VERSION 5.8 ;
BUSBITCHARS "[]" ;
DIVIDERCHAR "/" ;
UNITS
    DATABASE MICRONS 1000 ;
END UNITS

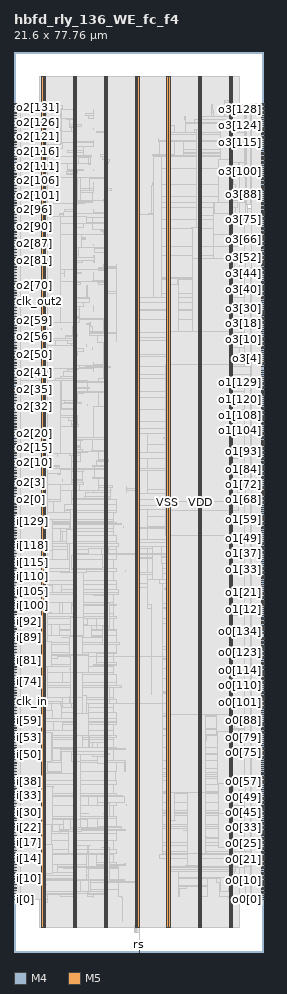
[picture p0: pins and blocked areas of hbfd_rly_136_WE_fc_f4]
MACRO hbfd_rly_136_WE_fc_f4
  FOREIGN hbfd_rly_136_WE_fc_f4 0 0 ;
  CLASS BLOCK ;
  SIZE 21.6 BY 77.76 ;
  PIN clk_in
    DIRECTION INPUT ;
    USE SIGNAL ;
    PORT
      LAYER M4 ;
        RECT  0 21.6 0.192 21.624 ;
    END
  END clk_in
  PIN clk_out0
    DIRECTION OUTPUT ;
    USE SIGNAL ;
    PORT
      LAYER M4 ;
        RECT  21.408 15.84 21.6 15.864 ;
    END
  END clk_out0
  PIN clk_out1
    DIRECTION OUTPUT ;
    USE SIGNAL ;
    PORT
      LAYER M4 ;
        RECT  21.408 38.88 21.6 38.904 ;
    END
  END clk_out1
  PIN clk_out2
    DIRECTION OUTPUT ;
    USE SIGNAL ;
    PORT
      LAYER M4 ;
        RECT  0 56.16 0.192 56.184 ;
    END
  END clk_out2
  PIN clk_out3
    DIRECTION OUTPUT ;
    USE SIGNAL ;
    PORT
      LAYER M4 ;
        RECT  21.408 61.92 21.6 61.944 ;
    END
  END clk_out3
  PIN i[0]
    DIRECTION INPUT ;
    USE SIGNAL ;
    PORT
      LAYER M4 ;
        RECT  0 4.512 0.192 4.536 ;
    END
  END i[0]
  PIN i[100]
    DIRECTION INPUT ;
    USE SIGNAL ;
    PORT
      LAYER M4 ;
        RECT  0 29.904 0.192 29.928 ;
    END
  END i[100]
  PIN i[101]
    DIRECTION INPUT ;
    USE SIGNAL ;
    PORT
      LAYER M4 ;
        RECT  0 30.144 0.192 30.168 ;
    END
  END i[101]
  PIN i[102]
    DIRECTION INPUT ;
    USE SIGNAL ;
    PORT
      LAYER M4 ;
        RECT  0 30.384 0.192 30.408 ;
    END
  END i[102]
  PIN i[103]
    DIRECTION INPUT ;
    USE SIGNAL ;
    PORT
      LAYER M4 ;
        RECT  0 30.672 0.192 30.696 ;
    END
  END i[103]
  PIN i[104]
    DIRECTION INPUT ;
    USE SIGNAL ;
    PORT
      LAYER M4 ;
        RECT  0 30.912 0.192 30.936 ;
    END
  END i[104]
  PIN i[105]
    DIRECTION INPUT ;
    USE SIGNAL ;
    PORT
      LAYER M4 ;
        RECT  0 31.152 0.192 31.176 ;
    END
  END i[105]
  PIN i[106]
    DIRECTION INPUT ;
    USE SIGNAL ;
    PORT
      LAYER M4 ;
        RECT  0 31.392 0.192 31.416 ;
    END
  END i[106]
  PIN i[107]
    DIRECTION INPUT ;
    USE SIGNAL ;
    PORT
      LAYER M4 ;
        RECT  0 31.68 0.192 31.704 ;
    END
  END i[107]
  PIN i[108]
    DIRECTION INPUT ;
    USE SIGNAL ;
    PORT
      LAYER M4 ;
        RECT  0 31.92 0.192 31.944 ;
    END
  END i[108]
  PIN i[109]
    DIRECTION INPUT ;
    USE SIGNAL ;
    PORT
      LAYER M4 ;
        RECT  0 32.16 0.192 32.184 ;
    END
  END i[109]
  PIN i[10]
    DIRECTION INPUT ;
    USE SIGNAL ;
    PORT
      LAYER M4 ;
        RECT  0 7.056 0.192 7.08 ;
    END
  END i[10]
  PIN i[110]
    DIRECTION INPUT ;
    USE SIGNAL ;
    PORT
      LAYER M4 ;
        RECT  0 32.4 0.192 32.424 ;
    END
  END i[110]
  PIN i[111]
    DIRECTION INPUT ;
    USE SIGNAL ;
    PORT
      LAYER M4 ;
        RECT  0 32.64 0.192 32.664 ;
    END
  END i[111]
  PIN i[112]
    DIRECTION INPUT ;
    USE SIGNAL ;
    PORT
      LAYER M4 ;
        RECT  0 32.928 0.192 32.952 ;
    END
  END i[112]
  PIN i[113]
    DIRECTION INPUT ;
    USE SIGNAL ;
    PORT
      LAYER M4 ;
        RECT  0 33.168 0.192 33.192 ;
    END
  END i[113]
  PIN i[114]
    DIRECTION INPUT ;
    USE SIGNAL ;
    PORT
      LAYER M4 ;
        RECT  0 33.408 0.192 33.432 ;
    END
  END i[114]
  PIN i[115]
    DIRECTION INPUT ;
    USE SIGNAL ;
    PORT
      LAYER M4 ;
        RECT  0 33.648 0.192 33.672 ;
    END
  END i[115]
  PIN i[116]
    DIRECTION INPUT ;
    USE SIGNAL ;
    PORT
      LAYER M4 ;
        RECT  0 33.936 0.192 33.96 ;
    END
  END i[116]
  PIN i[117]
    DIRECTION INPUT ;
    USE SIGNAL ;
    PORT
      LAYER M4 ;
        RECT  0 34.176 0.192 34.2 ;
    END
  END i[117]
  PIN i[118]
    DIRECTION INPUT ;
    USE SIGNAL ;
    PORT
      LAYER M4 ;
        RECT  0 34.416 0.192 34.44 ;
    END
  END i[118]
  PIN i[119]
    DIRECTION INPUT ;
    USE SIGNAL ;
    PORT
      LAYER M4 ;
        RECT  0 34.656 0.192 34.68 ;
    END
  END i[119]
  PIN i[11]
    DIRECTION INPUT ;
    USE SIGNAL ;
    PORT
      LAYER M4 ;
        RECT  0 7.296 0.192 7.32 ;
    END
  END i[11]
  PIN i[120]
    DIRECTION INPUT ;
    USE SIGNAL ;
    PORT
      LAYER M4 ;
        RECT  0 34.944 0.192 34.968 ;
    END
  END i[120]
  PIN i[121]
    DIRECTION INPUT ;
    USE SIGNAL ;
    PORT
      LAYER M4 ;
        RECT  0 35.184 0.192 35.208 ;
    END
  END i[121]
  PIN i[122]
    DIRECTION INPUT ;
    USE SIGNAL ;
    PORT
      LAYER M4 ;
        RECT  0 35.424 0.192 35.448 ;
    END
  END i[122]
  PIN i[123]
    DIRECTION INPUT ;
    USE SIGNAL ;
    PORT
      LAYER M4 ;
        RECT  0 35.664 0.192 35.688 ;
    END
  END i[123]
  PIN i[124]
    DIRECTION INPUT ;
    USE SIGNAL ;
    PORT
      LAYER M4 ;
        RECT  0 35.952 0.192 35.976 ;
    END
  END i[124]
  PIN i[125]
    DIRECTION INPUT ;
    USE SIGNAL ;
    PORT
      LAYER M4 ;
        RECT  0 36.192 0.192 36.216 ;
    END
  END i[125]
  PIN i[126]
    DIRECTION INPUT ;
    USE SIGNAL ;
    PORT
      LAYER M4 ;
        RECT  0 36.432 0.192 36.456 ;
    END
  END i[126]
  PIN i[127]
    DIRECTION INPUT ;
    USE SIGNAL ;
    PORT
      LAYER M4 ;
        RECT  0 36.672 0.192 36.696 ;
    END
  END i[127]
  PIN i[128]
    DIRECTION INPUT ;
    USE SIGNAL ;
    PORT
      LAYER M4 ;
        RECT  0 36.912 0.192 36.936 ;
    END
  END i[128]
  PIN i[129]
    DIRECTION INPUT ;
    USE SIGNAL ;
    PORT
      LAYER M4 ;
        RECT  0 37.2 0.192 37.224 ;
    END
  END i[129]
  PIN i[12]
    DIRECTION INPUT ;
    USE SIGNAL ;
    PORT
      LAYER M4 ;
        RECT  0 7.536 0.192 7.56 ;
    END
  END i[12]
  PIN i[130]
    DIRECTION INPUT ;
    USE SIGNAL ;
    PORT
      LAYER M4 ;
        RECT  0 37.44 0.192 37.464 ;
    END
  END i[130]
  PIN i[131]
    DIRECTION INPUT ;
    USE SIGNAL ;
    PORT
      LAYER M4 ;
        RECT  0 37.68 0.192 37.704 ;
    END
  END i[131]
  PIN i[132]
    DIRECTION INPUT ;
    USE SIGNAL ;
    PORT
      LAYER M4 ;
        RECT  0 37.92 0.192 37.944 ;
    END
  END i[132]
  PIN i[133]
    DIRECTION INPUT ;
    USE SIGNAL ;
    PORT
      LAYER M4 ;
        RECT  0 38.208 0.192 38.232 ;
    END
  END i[133]
  PIN i[134]
    DIRECTION INPUT ;
    USE SIGNAL ;
    PORT
      LAYER M4 ;
        RECT  0 38.448 0.192 38.472 ;
    END
  END i[134]
  PIN i[135]
    DIRECTION INPUT ;
    USE SIGNAL ;
    PORT
      LAYER M4 ;
        RECT  0 38.688 0.192 38.712 ;
    END
  END i[135]
  PIN i[13]
    DIRECTION INPUT ;
    USE SIGNAL ;
    PORT
      LAYER M4 ;
        RECT  0 7.776 0.192 7.8 ;
    END
  END i[13]
  PIN i[14]
    DIRECTION INPUT ;
    USE SIGNAL ;
    PORT
      LAYER M4 ;
        RECT  0 8.064 0.192 8.088 ;
    END
  END i[14]
  PIN i[15]
    DIRECTION INPUT ;
    USE SIGNAL ;
    PORT
      LAYER M4 ;
        RECT  0 8.304 0.192 8.328 ;
    END
  END i[15]
  PIN i[16]
    DIRECTION INPUT ;
    USE SIGNAL ;
    PORT
      LAYER M4 ;
        RECT  0 8.544 0.192 8.568 ;
    END
  END i[16]
  PIN i[17]
    DIRECTION INPUT ;
    USE SIGNAL ;
    PORT
      LAYER M4 ;
        RECT  0 8.784 0.192 8.808 ;
    END
  END i[17]
  PIN i[18]
    DIRECTION INPUT ;
    USE SIGNAL ;
    PORT
      LAYER M4 ;
        RECT  0 9.072 0.192 9.096 ;
    END
  END i[18]
  PIN i[19]
    DIRECTION INPUT ;
    USE SIGNAL ;
    PORT
      LAYER M4 ;
        RECT  0 9.312 0.192 9.336 ;
    END
  END i[19]
  PIN i[1]
    DIRECTION INPUT ;
    USE SIGNAL ;
    PORT
      LAYER M4 ;
        RECT  0 4.8 0.192 4.824 ;
    END
  END i[1]
  PIN i[20]
    DIRECTION INPUT ;
    USE SIGNAL ;
    PORT
      LAYER M4 ;
        RECT  0 9.552 0.192 9.576 ;
    END
  END i[20]
  PIN i[21]
    DIRECTION INPUT ;
    USE SIGNAL ;
    PORT
      LAYER M4 ;
        RECT  0 9.792 0.192 9.816 ;
    END
  END i[21]
  PIN i[22]
    DIRECTION INPUT ;
    USE SIGNAL ;
    PORT
      LAYER M4 ;
        RECT  0 10.08 0.192 10.104 ;
    END
  END i[22]
  PIN i[23]
    DIRECTION INPUT ;
    USE SIGNAL ;
    PORT
      LAYER M4 ;
        RECT  0 10.32 0.192 10.344 ;
    END
  END i[23]
  PIN i[24]
    DIRECTION INPUT ;
    USE SIGNAL ;
    PORT
      LAYER M4 ;
        RECT  0 10.56 0.192 10.584 ;
    END
  END i[24]
  PIN i[25]
    DIRECTION INPUT ;
    USE SIGNAL ;
    PORT
      LAYER M4 ;
        RECT  0 10.8 0.192 10.824 ;
    END
  END i[25]
  PIN i[26]
    DIRECTION INPUT ;
    USE SIGNAL ;
    PORT
      LAYER M4 ;
        RECT  0 11.04 0.192 11.064 ;
    END
  END i[26]
  PIN i[27]
    DIRECTION INPUT ;
    USE SIGNAL ;
    PORT
      LAYER M4 ;
        RECT  0 11.328 0.192 11.352 ;
    END
  END i[27]
  PIN i[28]
    DIRECTION INPUT ;
    USE SIGNAL ;
    PORT
      LAYER M4 ;
        RECT  0 11.568 0.192 11.592 ;
    END
  END i[28]
  PIN i[29]
    DIRECTION INPUT ;
    USE SIGNAL ;
    PORT
      LAYER M4 ;
        RECT  0 11.808 0.192 11.832 ;
    END
  END i[29]
  PIN i[2]
    DIRECTION INPUT ;
    USE SIGNAL ;
    PORT
      LAYER M4 ;
        RECT  0 5.04 0.192 5.064 ;
    END
  END i[2]
  PIN i[30]
    DIRECTION INPUT ;
    USE SIGNAL ;
    PORT
      LAYER M4 ;
        RECT  0 12.048 0.192 12.072 ;
    END
  END i[30]
  PIN i[31]
    DIRECTION INPUT ;
    USE SIGNAL ;
    PORT
      LAYER M4 ;
        RECT  0 12.336 0.192 12.36 ;
    END
  END i[31]
  PIN i[32]
    DIRECTION INPUT ;
    USE SIGNAL ;
    PORT
      LAYER M4 ;
        RECT  0 12.576 0.192 12.6 ;
    END
  END i[32]
  PIN i[33]
    DIRECTION INPUT ;
    USE SIGNAL ;
    PORT
      LAYER M4 ;
        RECT  0 12.816 0.192 12.84 ;
    END
  END i[33]
  PIN i[34]
    DIRECTION INPUT ;
    USE SIGNAL ;
    PORT
      LAYER M4 ;
        RECT  0 13.056 0.192 13.08 ;
    END
  END i[34]
  PIN i[35]
    DIRECTION INPUT ;
    USE SIGNAL ;
    PORT
      LAYER M4 ;
        RECT  0 13.344 0.192 13.368 ;
    END
  END i[35]
  PIN i[36]
    DIRECTION INPUT ;
    USE SIGNAL ;
    PORT
      LAYER M4 ;
        RECT  0 13.584 0.192 13.608 ;
    END
  END i[36]
  PIN i[37]
    DIRECTION INPUT ;
    USE SIGNAL ;
    PORT
      LAYER M4 ;
        RECT  0 13.824 0.192 13.848 ;
    END
  END i[37]
  PIN i[38]
    DIRECTION INPUT ;
    USE SIGNAL ;
    PORT
      LAYER M4 ;
        RECT  0 14.064 0.192 14.088 ;
    END
  END i[38]
  PIN i[39]
    DIRECTION INPUT ;
    USE SIGNAL ;
    PORT
      LAYER M4 ;
        RECT  0 14.304 0.192 14.328 ;
    END
  END i[39]
  PIN i[3]
    DIRECTION INPUT ;
    USE SIGNAL ;
    PORT
      LAYER M4 ;
        RECT  0 5.28 0.192 5.304 ;
    END
  END i[3]
  PIN i[40]
    DIRECTION INPUT ;
    USE SIGNAL ;
    PORT
      LAYER M4 ;
        RECT  0 14.592 0.192 14.616 ;
    END
  END i[40]
  PIN i[41]
    DIRECTION INPUT ;
    USE SIGNAL ;
    PORT
      LAYER M4 ;
        RECT  0 14.832 0.192 14.856 ;
    END
  END i[41]
  PIN i[42]
    DIRECTION INPUT ;
    USE SIGNAL ;
    PORT
      LAYER M4 ;
        RECT  0 15.072 0.192 15.096 ;
    END
  END i[42]
  PIN i[43]
    DIRECTION INPUT ;
    USE SIGNAL ;
    PORT
      LAYER M4 ;
        RECT  0 15.312 0.192 15.336 ;
    END
  END i[43]
  PIN i[44]
    DIRECTION INPUT ;
    USE SIGNAL ;
    PORT
      LAYER M4 ;
        RECT  0 15.6 0.192 15.624 ;
    END
  END i[44]
  PIN i[45]
    DIRECTION INPUT ;
    USE SIGNAL ;
    PORT
      LAYER M4 ;
        RECT  0 15.84 0.192 15.864 ;
    END
  END i[45]
  PIN i[46]
    DIRECTION INPUT ;
    USE SIGNAL ;
    PORT
      LAYER M4 ;
        RECT  0 16.08 0.192 16.104 ;
    END
  END i[46]
  PIN i[47]
    DIRECTION INPUT ;
    USE SIGNAL ;
    PORT
      LAYER M4 ;
        RECT  0 16.32 0.192 16.344 ;
    END
  END i[47]
  PIN i[48]
    DIRECTION INPUT ;
    USE SIGNAL ;
    PORT
      LAYER M4 ;
        RECT  0 16.608 0.192 16.632 ;
    END
  END i[48]
  PIN i[49]
    DIRECTION INPUT ;
    USE SIGNAL ;
    PORT
      LAYER M4 ;
        RECT  0 16.848 0.192 16.872 ;
    END
  END i[49]
  PIN i[4]
    DIRECTION INPUT ;
    USE SIGNAL ;
    PORT
      LAYER M4 ;
        RECT  0 5.52 0.192 5.544 ;
    END
  END i[4]
  PIN i[50]
    DIRECTION INPUT ;
    USE SIGNAL ;
    PORT
      LAYER M4 ;
        RECT  0 17.088 0.192 17.112 ;
    END
  END i[50]
  PIN i[51]
    DIRECTION INPUT ;
    USE SIGNAL ;
    PORT
      LAYER M4 ;
        RECT  0 17.328 0.192 17.352 ;
    END
  END i[51]
  PIN i[52]
    DIRECTION INPUT ;
    USE SIGNAL ;
    PORT
      LAYER M4 ;
        RECT  0 17.616 0.192 17.64 ;
    END
  END i[52]
  PIN i[53]
    DIRECTION INPUT ;
    USE SIGNAL ;
    PORT
      LAYER M4 ;
        RECT  0 17.856 0.192 17.88 ;
    END
  END i[53]
  PIN i[54]
    DIRECTION INPUT ;
    USE SIGNAL ;
    PORT
      LAYER M4 ;
        RECT  0 18.096 0.192 18.12 ;
    END
  END i[54]
  PIN i[55]
    DIRECTION INPUT ;
    USE SIGNAL ;
    PORT
      LAYER M4 ;
        RECT  0 18.336 0.192 18.36 ;
    END
  END i[55]
  PIN i[56]
    DIRECTION INPUT ;
    USE SIGNAL ;
    PORT
      LAYER M4 ;
        RECT  0 18.576 0.192 18.6 ;
    END
  END i[56]
  PIN i[57]
    DIRECTION INPUT ;
    USE SIGNAL ;
    PORT
      LAYER M4 ;
        RECT  0 18.864 0.192 18.888 ;
    END
  END i[57]
  PIN i[58]
    DIRECTION INPUT ;
    USE SIGNAL ;
    PORT
      LAYER M4 ;
        RECT  0 19.104 0.192 19.128 ;
    END
  END i[58]
  PIN i[59]
    DIRECTION INPUT ;
    USE SIGNAL ;
    PORT
      LAYER M4 ;
        RECT  0 19.344 0.192 19.368 ;
    END
  END i[59]
  PIN i[5]
    DIRECTION INPUT ;
    USE SIGNAL ;
    PORT
      LAYER M4 ;
        RECT  0 5.808 0.192 5.832 ;
    END
  END i[5]
  PIN i[60]
    DIRECTION INPUT ;
    USE SIGNAL ;
    PORT
      LAYER M4 ;
        RECT  0 19.584 0.192 19.608 ;
    END
  END i[60]
  PIN i[61]
    DIRECTION INPUT ;
    USE SIGNAL ;
    PORT
      LAYER M4 ;
        RECT  0 19.872 0.192 19.896 ;
    END
  END i[61]
  PIN i[62]
    DIRECTION INPUT ;
    USE SIGNAL ;
    PORT
      LAYER M4 ;
        RECT  0 20.112 0.192 20.136 ;
    END
  END i[62]
  PIN i[63]
    DIRECTION INPUT ;
    USE SIGNAL ;
    PORT
      LAYER M4 ;
        RECT  0 20.352 0.192 20.376 ;
    END
  END i[63]
  PIN i[64]
    DIRECTION INPUT ;
    USE SIGNAL ;
    PORT
      LAYER M4 ;
        RECT  0 20.592 0.192 20.616 ;
    END
  END i[64]
  PIN i[65]
    DIRECTION INPUT ;
    USE SIGNAL ;
    PORT
      LAYER M4 ;
        RECT  0 20.88 0.192 20.904 ;
    END
  END i[65]
  PIN i[66]
    DIRECTION INPUT ;
    USE SIGNAL ;
    PORT
      LAYER M4 ;
        RECT  0 21.12 0.192 21.144 ;
    END
  END i[66]
  PIN i[67]
    DIRECTION INPUT ;
    USE SIGNAL ;
    PORT
      LAYER M4 ;
        RECT  0 21.36 0.192 21.384 ;
    END
  END i[67]
  PIN i[68]
    DIRECTION INPUT ;
    USE SIGNAL ;
    PORT
      LAYER M4 ;
        RECT  0 21.84 0.192 21.864 ;
    END
  END i[68]
  PIN i[69]
    DIRECTION INPUT ;
    USE SIGNAL ;
    PORT
      LAYER M4 ;
        RECT  0 22.128 0.192 22.152 ;
    END
  END i[69]
  PIN i[6]
    DIRECTION INPUT ;
    USE SIGNAL ;
    PORT
      LAYER M4 ;
        RECT  0 6.048 0.192 6.072 ;
    END
  END i[6]
  PIN i[70]
    DIRECTION INPUT ;
    USE SIGNAL ;
    PORT
      LAYER M4 ;
        RECT  0 22.368 0.192 22.392 ;
    END
  END i[70]
  PIN i[71]
    DIRECTION INPUT ;
    USE SIGNAL ;
    PORT
      LAYER M4 ;
        RECT  0 22.608 0.192 22.632 ;
    END
  END i[71]
  PIN i[72]
    DIRECTION INPUT ;
    USE SIGNAL ;
    PORT
      LAYER M4 ;
        RECT  0 22.848 0.192 22.872 ;
    END
  END i[72]
  PIN i[73]
    DIRECTION INPUT ;
    USE SIGNAL ;
    PORT
      LAYER M4 ;
        RECT  0 23.136 0.192 23.16 ;
    END
  END i[73]
  PIN i[74]
    DIRECTION INPUT ;
    USE SIGNAL ;
    PORT
      LAYER M4 ;
        RECT  0 23.376 0.192 23.4 ;
    END
  END i[74]
  PIN i[75]
    DIRECTION INPUT ;
    USE SIGNAL ;
    PORT
      LAYER M4 ;
        RECT  0 23.616 0.192 23.64 ;
    END
  END i[75]
  PIN i[76]
    DIRECTION INPUT ;
    USE SIGNAL ;
    PORT
      LAYER M4 ;
        RECT  0 23.856 0.192 23.88 ;
    END
  END i[76]
  PIN i[77]
    DIRECTION INPUT ;
    USE SIGNAL ;
    PORT
      LAYER M4 ;
        RECT  0 24.144 0.192 24.168 ;
    END
  END i[77]
  PIN i[78]
    DIRECTION INPUT ;
    USE SIGNAL ;
    PORT
      LAYER M4 ;
        RECT  0 24.384 0.192 24.408 ;
    END
  END i[78]
  PIN i[79]
    DIRECTION INPUT ;
    USE SIGNAL ;
    PORT
      LAYER M4 ;
        RECT  0 24.624 0.192 24.648 ;
    END
  END i[79]
  PIN i[7]
    DIRECTION INPUT ;
    USE SIGNAL ;
    PORT
      LAYER M4 ;
        RECT  0 6.288 0.192 6.312 ;
    END
  END i[7]
  PIN i[80]
    DIRECTION INPUT ;
    USE SIGNAL ;
    PORT
      LAYER M4 ;
        RECT  0 24.864 0.192 24.888 ;
    END
  END i[80]
  PIN i[81]
    DIRECTION INPUT ;
    USE SIGNAL ;
    PORT
      LAYER M4 ;
        RECT  0 25.152 0.192 25.176 ;
    END
  END i[81]
  PIN i[82]
    DIRECTION INPUT ;
    USE SIGNAL ;
    PORT
      LAYER M4 ;
        RECT  0 25.392 0.192 25.416 ;
    END
  END i[82]
  PIN i[83]
    DIRECTION INPUT ;
    USE SIGNAL ;
    PORT
      LAYER M4 ;
        RECT  0 25.632 0.192 25.656 ;
    END
  END i[83]
  PIN i[84]
    DIRECTION INPUT ;
    USE SIGNAL ;
    PORT
      LAYER M4 ;
        RECT  0 25.872 0.192 25.896 ;
    END
  END i[84]
  PIN i[85]
    DIRECTION INPUT ;
    USE SIGNAL ;
    PORT
      LAYER M4 ;
        RECT  0 26.112 0.192 26.136 ;
    END
  END i[85]
  PIN i[86]
    DIRECTION INPUT ;
    USE SIGNAL ;
    PORT
      LAYER M4 ;
        RECT  0 26.4 0.192 26.424 ;
    END
  END i[86]
  PIN i[87]
    DIRECTION INPUT ;
    USE SIGNAL ;
    PORT
      LAYER M4 ;
        RECT  0 26.64 0.192 26.664 ;
    END
  END i[87]
  PIN i[88]
    DIRECTION INPUT ;
    USE SIGNAL ;
    PORT
      LAYER M4 ;
        RECT  0 26.88 0.192 26.904 ;
    END
  END i[88]
  PIN i[89]
    DIRECTION INPUT ;
    USE SIGNAL ;
    PORT
      LAYER M4 ;
        RECT  0 27.12 0.192 27.144 ;
    END
  END i[89]
  PIN i[8]
    DIRECTION INPUT ;
    USE SIGNAL ;
    PORT
      LAYER M4 ;
        RECT  0 6.528 0.192 6.552 ;
    END
  END i[8]
  PIN i[90]
    DIRECTION INPUT ;
    USE SIGNAL ;
    PORT
      LAYER M4 ;
        RECT  0 27.408 0.192 27.432 ;
    END
  END i[90]
  PIN i[91]
    DIRECTION INPUT ;
    USE SIGNAL ;
    PORT
      LAYER M4 ;
        RECT  0 27.648 0.192 27.672 ;
    END
  END i[91]
  PIN i[92]
    DIRECTION INPUT ;
    USE SIGNAL ;
    PORT
      LAYER M4 ;
        RECT  0 27.888 0.192 27.912 ;
    END
  END i[92]
  PIN i[93]
    DIRECTION INPUT ;
    USE SIGNAL ;
    PORT
      LAYER M4 ;
        RECT  0 28.128 0.192 28.152 ;
    END
  END i[93]
  PIN i[94]
    DIRECTION INPUT ;
    USE SIGNAL ;
    PORT
      LAYER M4 ;
        RECT  0 28.416 0.192 28.44 ;
    END
  END i[94]
  PIN i[95]
    DIRECTION INPUT ;
    USE SIGNAL ;
    PORT
      LAYER M4 ;
        RECT  0 28.656 0.192 28.68 ;
    END
  END i[95]
  PIN i[96]
    DIRECTION INPUT ;
    USE SIGNAL ;
    PORT
      LAYER M4 ;
        RECT  0 28.896 0.192 28.92 ;
    END
  END i[96]
  PIN i[97]
    DIRECTION INPUT ;
    USE SIGNAL ;
    PORT
      LAYER M4 ;
        RECT  0 29.136 0.192 29.16 ;
    END
  END i[97]
  PIN i[98]
    DIRECTION INPUT ;
    USE SIGNAL ;
    PORT
      LAYER M4 ;
        RECT  0 29.376 0.192 29.4 ;
    END
  END i[98]
  PIN i[99]
    DIRECTION INPUT ;
    USE SIGNAL ;
    PORT
      LAYER M4 ;
        RECT  0 29.664 0.192 29.688 ;
    END
  END i[99]
  PIN i[9]
    DIRECTION INPUT ;
    USE SIGNAL ;
    PORT
      LAYER M4 ;
        RECT  0 6.816 0.192 6.84 ;
    END
  END i[9]
  PIN o0[0]
    DIRECTION OUTPUT ;
    USE SIGNAL ;
    PORT
      LAYER M4 ;
        RECT  21.408 4.512 21.6 4.536 ;
    END
  END o0[0]
  PIN o0[100]
    DIRECTION OUTPUT ;
    USE SIGNAL ;
    PORT
      LAYER M4 ;
        RECT  21.408 21.36 21.6 21.384 ;
    END
  END o0[100]
  PIN o0[101]
    DIRECTION OUTPUT ;
    USE SIGNAL ;
    PORT
      LAYER M4 ;
        RECT  21.408 21.504 21.6 21.528 ;
    END
  END o0[101]
  PIN o0[102]
    DIRECTION OUTPUT ;
    USE SIGNAL ;
    PORT
      LAYER M4 ;
        RECT  21.408 21.696 21.6 21.72 ;
    END
  END o0[102]
  PIN o0[103]
    DIRECTION OUTPUT ;
    USE SIGNAL ;
    PORT
      LAYER M4 ;
        RECT  21.408 21.84 21.6 21.864 ;
    END
  END o0[103]
  PIN o0[104]
    DIRECTION OUTPUT ;
    USE SIGNAL ;
    PORT
      LAYER M4 ;
        RECT  21.408 22.032 21.6 22.056 ;
    END
  END o0[104]
  PIN o0[105]
    DIRECTION OUTPUT ;
    USE SIGNAL ;
    PORT
      LAYER M4 ;
        RECT  21.408 22.176 21.6 22.2 ;
    END
  END o0[105]
  PIN o0[106]
    DIRECTION OUTPUT ;
    USE SIGNAL ;
    PORT
      LAYER M4 ;
        RECT  21.408 22.368 21.6 22.392 ;
    END
  END o0[106]
  PIN o0[107]
    DIRECTION OUTPUT ;
    USE SIGNAL ;
    PORT
      LAYER M4 ;
        RECT  21.408 22.512 21.6 22.536 ;
    END
  END o0[107]
  PIN o0[108]
    DIRECTION OUTPUT ;
    USE SIGNAL ;
    PORT
      LAYER M4 ;
        RECT  21.408 22.656 21.6 22.68 ;
    END
  END o0[108]
  PIN o0[109]
    DIRECTION OUTPUT ;
    USE SIGNAL ;
    PORT
      LAYER M4 ;
        RECT  21.408 22.848 21.6 22.872 ;
    END
  END o0[109]
  PIN o0[10]
    DIRECTION OUTPUT ;
    USE SIGNAL ;
    PORT
      LAYER M4 ;
        RECT  21.408 6.192 21.6 6.216 ;
    END
  END o0[10]
  PIN o0[110]
    DIRECTION OUTPUT ;
    USE SIGNAL ;
    PORT
      LAYER M4 ;
        RECT  21.408 22.992 21.6 23.016 ;
    END
  END o0[110]
  PIN o0[111]
    DIRECTION OUTPUT ;
    USE SIGNAL ;
    PORT
      LAYER M4 ;
        RECT  21.408 23.184 21.6 23.208 ;
    END
  END o0[111]
  PIN o0[112]
    DIRECTION OUTPUT ;
    USE SIGNAL ;
    PORT
      LAYER M4 ;
        RECT  21.408 23.328 21.6 23.352 ;
    END
  END o0[112]
  PIN o0[113]
    DIRECTION OUTPUT ;
    USE SIGNAL ;
    PORT
      LAYER M4 ;
        RECT  21.408 23.52 21.6 23.544 ;
    END
  END o0[113]
  PIN o0[114]
    DIRECTION OUTPUT ;
    USE SIGNAL ;
    PORT
      LAYER M4 ;
        RECT  21.408 23.664 21.6 23.688 ;
    END
  END o0[114]
  PIN o0[115]
    DIRECTION OUTPUT ;
    USE SIGNAL ;
    PORT
      LAYER M4 ;
        RECT  21.408 23.856 21.6 23.88 ;
    END
  END o0[115]
  PIN o0[116]
    DIRECTION OUTPUT ;
    USE SIGNAL ;
    PORT
      LAYER M4 ;
        RECT  21.408 24 21.6 24.024 ;
    END
  END o0[116]
  PIN o0[117]
    DIRECTION OUTPUT ;
    USE SIGNAL ;
    PORT
      LAYER M4 ;
        RECT  21.408 24.192 21.6 24.216 ;
    END
  END o0[117]
  PIN o0[118]
    DIRECTION OUTPUT ;
    USE SIGNAL ;
    PORT
      LAYER M4 ;
        RECT  21.408 24.336 21.6 24.36 ;
    END
  END o0[118]
  PIN o0[119]
    DIRECTION OUTPUT ;
    USE SIGNAL ;
    PORT
      LAYER M4 ;
        RECT  21.408 24.528 21.6 24.552 ;
    END
  END o0[119]
  PIN o0[11]
    DIRECTION OUTPUT ;
    USE SIGNAL ;
    PORT
      LAYER M4 ;
        RECT  21.408 6.384 21.6 6.408 ;
    END
  END o0[11]
  PIN o0[120]
    DIRECTION OUTPUT ;
    USE SIGNAL ;
    PORT
      LAYER M4 ;
        RECT  21.408 24.672 21.6 24.696 ;
    END
  END o0[120]
  PIN o0[121]
    DIRECTION OUTPUT ;
    USE SIGNAL ;
    PORT
      LAYER M4 ;
        RECT  21.408 24.864 21.6 24.888 ;
    END
  END o0[121]
  PIN o0[122]
    DIRECTION OUTPUT ;
    USE SIGNAL ;
    PORT
      LAYER M4 ;
        RECT  21.408 25.008 21.6 25.032 ;
    END
  END o0[122]
  PIN o0[123]
    DIRECTION OUTPUT ;
    USE SIGNAL ;
    PORT
      LAYER M4 ;
        RECT  21.408 25.152 21.6 25.176 ;
    END
  END o0[123]
  PIN o0[124]
    DIRECTION OUTPUT ;
    USE SIGNAL ;
    PORT
      LAYER M4 ;
        RECT  21.408 25.344 21.6 25.368 ;
    END
  END o0[124]
  PIN o0[125]
    DIRECTION OUTPUT ;
    USE SIGNAL ;
    PORT
      LAYER M4 ;
        RECT  21.408 25.488 21.6 25.512 ;
    END
  END o0[125]
  PIN o0[126]
    DIRECTION OUTPUT ;
    USE SIGNAL ;
    PORT
      LAYER M4 ;
        RECT  21.408 25.68 21.6 25.704 ;
    END
  END o0[126]
  PIN o0[127]
    DIRECTION OUTPUT ;
    USE SIGNAL ;
    PORT
      LAYER M4 ;
        RECT  21.408 25.824 21.6 25.848 ;
    END
  END o0[127]
  PIN o0[128]
    DIRECTION OUTPUT ;
    USE SIGNAL ;
    PORT
      LAYER M4 ;
        RECT  21.408 26.016 21.6 26.04 ;
    END
  END o0[128]
  PIN o0[129]
    DIRECTION OUTPUT ;
    USE SIGNAL ;
    PORT
      LAYER M4 ;
        RECT  21.408 26.16 21.6 26.184 ;
    END
  END o0[129]
  PIN o0[12]
    DIRECTION OUTPUT ;
    USE SIGNAL ;
    PORT
      LAYER M4 ;
        RECT  21.408 6.528 21.6 6.552 ;
    END
  END o0[12]
  PIN o0[130]
    DIRECTION OUTPUT ;
    USE SIGNAL ;
    PORT
      LAYER M4 ;
        RECT  21.408 26.352 21.6 26.376 ;
    END
  END o0[130]
  PIN o0[131]
    DIRECTION OUTPUT ;
    USE SIGNAL ;
    PORT
      LAYER M4 ;
        RECT  21.408 26.496 21.6 26.52 ;
    END
  END o0[131]
  PIN o0[132]
    DIRECTION OUTPUT ;
    USE SIGNAL ;
    PORT
      LAYER M4 ;
        RECT  21.408 26.688 21.6 26.712 ;
    END
  END o0[132]
  PIN o0[133]
    DIRECTION OUTPUT ;
    USE SIGNAL ;
    PORT
      LAYER M4 ;
        RECT  21.408 26.832 21.6 26.856 ;
    END
  END o0[133]
  PIN o0[134]
    DIRECTION OUTPUT ;
    USE SIGNAL ;
    PORT
      LAYER M4 ;
        RECT  21.408 27.024 21.6 27.048 ;
    END
  END o0[134]
  PIN o0[135]
    DIRECTION OUTPUT ;
    USE SIGNAL ;
    PORT
      LAYER M4 ;
        RECT  21.408 27.168 21.6 27.192 ;
    END
  END o0[135]
  PIN o0[13]
    DIRECTION OUTPUT ;
    USE SIGNAL ;
    PORT
      LAYER M4 ;
        RECT  21.408 6.72 21.6 6.744 ;
    END
  END o0[13]
  PIN o0[14]
    DIRECTION OUTPUT ;
    USE SIGNAL ;
    PORT
      LAYER M4 ;
        RECT  21.408 6.864 21.6 6.888 ;
    END
  END o0[14]
  PIN o0[15]
    DIRECTION OUTPUT ;
    USE SIGNAL ;
    PORT
      LAYER M4 ;
        RECT  21.408 7.008 21.6 7.032 ;
    END
  END o0[15]
  PIN o0[16]
    DIRECTION OUTPUT ;
    USE SIGNAL ;
    PORT
      LAYER M4 ;
        RECT  21.408 7.2 21.6 7.224 ;
    END
  END o0[16]
  PIN o0[17]
    DIRECTION OUTPUT ;
    USE SIGNAL ;
    PORT
      LAYER M4 ;
        RECT  21.408 7.344 21.6 7.368 ;
    END
  END o0[17]
  PIN o0[18]
    DIRECTION OUTPUT ;
    USE SIGNAL ;
    PORT
      LAYER M4 ;
        RECT  21.408 7.536 21.6 7.56 ;
    END
  END o0[18]
  PIN o0[19]
    DIRECTION OUTPUT ;
    USE SIGNAL ;
    PORT
      LAYER M4 ;
        RECT  21.408 7.68 21.6 7.704 ;
    END
  END o0[19]
  PIN o0[1]
    DIRECTION OUTPUT ;
    USE SIGNAL ;
    PORT
      LAYER M4 ;
        RECT  21.408 4.704 21.6 4.728 ;
    END
  END o0[1]
  PIN o0[20]
    DIRECTION OUTPUT ;
    USE SIGNAL ;
    PORT
      LAYER M4 ;
        RECT  21.408 7.872 21.6 7.896 ;
    END
  END o0[20]
  PIN o0[21]
    DIRECTION OUTPUT ;
    USE SIGNAL ;
    PORT
      LAYER M4 ;
        RECT  21.408 8.016 21.6 8.04 ;
    END
  END o0[21]
  PIN o0[22]
    DIRECTION OUTPUT ;
    USE SIGNAL ;
    PORT
      LAYER M4 ;
        RECT  21.408 8.208 21.6 8.232 ;
    END
  END o0[22]
  PIN o0[23]
    DIRECTION OUTPUT ;
    USE SIGNAL ;
    PORT
      LAYER M4 ;
        RECT  21.408 8.352 21.6 8.376 ;
    END
  END o0[23]
  PIN o0[24]
    DIRECTION OUTPUT ;
    USE SIGNAL ;
    PORT
      LAYER M4 ;
        RECT  21.408 8.544 21.6 8.568 ;
    END
  END o0[24]
  PIN o0[25]
    DIRECTION OUTPUT ;
    USE SIGNAL ;
    PORT
      LAYER M4 ;
        RECT  21.408 8.688 21.6 8.712 ;
    END
  END o0[25]
  PIN o0[26]
    DIRECTION OUTPUT ;
    USE SIGNAL ;
    PORT
      LAYER M4 ;
        RECT  21.408 8.88 21.6 8.904 ;
    END
  END o0[26]
  PIN o0[27]
    DIRECTION OUTPUT ;
    USE SIGNAL ;
    PORT
      LAYER M4 ;
        RECT  21.408 9.024 21.6 9.048 ;
    END
  END o0[27]
  PIN o0[28]
    DIRECTION OUTPUT ;
    USE SIGNAL ;
    PORT
      LAYER M4 ;
        RECT  21.408 9.216 21.6 9.24 ;
    END
  END o0[28]
  PIN o0[29]
    DIRECTION OUTPUT ;
    USE SIGNAL ;
    PORT
      LAYER M4 ;
        RECT  21.408 9.36 21.6 9.384 ;
    END
  END o0[29]
  PIN o0[2]
    DIRECTION OUTPUT ;
    USE SIGNAL ;
    PORT
      LAYER M4 ;
        RECT  21.408 4.848 21.6 4.872 ;
    END
  END o0[2]
  PIN o0[30]
    DIRECTION OUTPUT ;
    USE SIGNAL ;
    PORT
      LAYER M4 ;
        RECT  21.408 9.504 21.6 9.528 ;
    END
  END o0[30]
  PIN o0[31]
    DIRECTION OUTPUT ;
    USE SIGNAL ;
    PORT
      LAYER M4 ;
        RECT  21.408 9.696 21.6 9.72 ;
    END
  END o0[31]
  PIN o0[32]
    DIRECTION OUTPUT ;
    USE SIGNAL ;
    PORT
      LAYER M4 ;
        RECT  21.408 9.84 21.6 9.864 ;
    END
  END o0[32]
  PIN o0[33]
    DIRECTION OUTPUT ;
    USE SIGNAL ;
    PORT
      LAYER M4 ;
        RECT  21.408 10.032 21.6 10.056 ;
    END
  END o0[33]
  PIN o0[34]
    DIRECTION OUTPUT ;
    USE SIGNAL ;
    PORT
      LAYER M4 ;
        RECT  21.408 10.176 21.6 10.2 ;
    END
  END o0[34]
  PIN o0[35]
    DIRECTION OUTPUT ;
    USE SIGNAL ;
    PORT
      LAYER M4 ;
        RECT  21.408 10.368 21.6 10.392 ;
    END
  END o0[35]
  PIN o0[36]
    DIRECTION OUTPUT ;
    USE SIGNAL ;
    PORT
      LAYER M4 ;
        RECT  21.408 10.512 21.6 10.536 ;
    END
  END o0[36]
  PIN o0[37]
    DIRECTION OUTPUT ;
    USE SIGNAL ;
    PORT
      LAYER M4 ;
        RECT  21.408 10.704 21.6 10.728 ;
    END
  END o0[37]
  PIN o0[38]
    DIRECTION OUTPUT ;
    USE SIGNAL ;
    PORT
      LAYER M4 ;
        RECT  21.408 10.848 21.6 10.872 ;
    END
  END o0[38]
  PIN o0[39]
    DIRECTION OUTPUT ;
    USE SIGNAL ;
    PORT
      LAYER M4 ;
        RECT  21.408 11.04 21.6 11.064 ;
    END
  END o0[39]
  PIN o0[3]
    DIRECTION OUTPUT ;
    USE SIGNAL ;
    PORT
      LAYER M4 ;
        RECT  21.408 5.04 21.6 5.064 ;
    END
  END o0[3]
  PIN o0[40]
    DIRECTION OUTPUT ;
    USE SIGNAL ;
    PORT
      LAYER M4 ;
        RECT  21.408 11.184 21.6 11.208 ;
    END
  END o0[40]
  PIN o0[41]
    DIRECTION OUTPUT ;
    USE SIGNAL ;
    PORT
      LAYER M4 ;
        RECT  21.408 11.376 21.6 11.4 ;
    END
  END o0[41]
  PIN o0[42]
    DIRECTION OUTPUT ;
    USE SIGNAL ;
    PORT
      LAYER M4 ;
        RECT  21.408 11.52 21.6 11.544 ;
    END
  END o0[42]
  PIN o0[43]
    DIRECTION OUTPUT ;
    USE SIGNAL ;
    PORT
      LAYER M4 ;
        RECT  21.408 11.712 21.6 11.736 ;
    END
  END o0[43]
  PIN o0[44]
    DIRECTION OUTPUT ;
    USE SIGNAL ;
    PORT
      LAYER M4 ;
        RECT  21.408 11.856 21.6 11.88 ;
    END
  END o0[44]
  PIN o0[45]
    DIRECTION OUTPUT ;
    USE SIGNAL ;
    PORT
      LAYER M4 ;
        RECT  21.408 12 21.6 12.024 ;
    END
  END o0[45]
  PIN o0[46]
    DIRECTION OUTPUT ;
    USE SIGNAL ;
    PORT
      LAYER M4 ;
        RECT  21.408 12.192 21.6 12.216 ;
    END
  END o0[46]
  PIN o0[47]
    DIRECTION OUTPUT ;
    USE SIGNAL ;
    PORT
      LAYER M4 ;
        RECT  21.408 12.336 21.6 12.36 ;
    END
  END o0[47]
  PIN o0[48]
    DIRECTION OUTPUT ;
    USE SIGNAL ;
    PORT
      LAYER M4 ;
        RECT  21.408 12.528 21.6 12.552 ;
    END
  END o0[48]
  PIN o0[49]
    DIRECTION OUTPUT ;
    USE SIGNAL ;
    PORT
      LAYER M4 ;
        RECT  21.408 12.672 21.6 12.696 ;
    END
  END o0[49]
  PIN o0[4]
    DIRECTION OUTPUT ;
    USE SIGNAL ;
    PORT
      LAYER M4 ;
        RECT  21.408 5.184 21.6 5.208 ;
    END
  END o0[4]
  PIN o0[50]
    DIRECTION OUTPUT ;
    USE SIGNAL ;
    PORT
      LAYER M4 ;
        RECT  21.408 12.864 21.6 12.888 ;
    END
  END o0[50]
  PIN o0[51]
    DIRECTION OUTPUT ;
    USE SIGNAL ;
    PORT
      LAYER M4 ;
        RECT  21.408 13.008 21.6 13.032 ;
    END
  END o0[51]
  PIN o0[52]
    DIRECTION OUTPUT ;
    USE SIGNAL ;
    PORT
      LAYER M4 ;
        RECT  21.408 13.2 21.6 13.224 ;
    END
  END o0[52]
  PIN o0[53]
    DIRECTION OUTPUT ;
    USE SIGNAL ;
    PORT
      LAYER M4 ;
        RECT  21.408 13.344 21.6 13.368 ;
    END
  END o0[53]
  PIN o0[54]
    DIRECTION OUTPUT ;
    USE SIGNAL ;
    PORT
      LAYER M4 ;
        RECT  21.408 13.536 21.6 13.56 ;
    END
  END o0[54]
  PIN o0[55]
    DIRECTION OUTPUT ;
    USE SIGNAL ;
    PORT
      LAYER M4 ;
        RECT  21.408 13.68 21.6 13.704 ;
    END
  END o0[55]
  PIN o0[56]
    DIRECTION OUTPUT ;
    USE SIGNAL ;
    PORT
      LAYER M4 ;
        RECT  21.408 13.872 21.6 13.896 ;
    END
  END o0[56]
  PIN o0[57]
    DIRECTION OUTPUT ;
    USE SIGNAL ;
    PORT
      LAYER M4 ;
        RECT  21.408 14.016 21.6 14.04 ;
    END
  END o0[57]
  PIN o0[58]
    DIRECTION OUTPUT ;
    USE SIGNAL ;
    PORT
      LAYER M4 ;
        RECT  21.408 14.208 21.6 14.232 ;
    END
  END o0[58]
  PIN o0[59]
    DIRECTION OUTPUT ;
    USE SIGNAL ;
    PORT
      LAYER M4 ;
        RECT  21.408 14.352 21.6 14.376 ;
    END
  END o0[59]
  PIN o0[5]
    DIRECTION OUTPUT ;
    USE SIGNAL ;
    PORT
      LAYER M4 ;
        RECT  21.408 5.376 21.6 5.4 ;
    END
  END o0[5]
  PIN o0[60]
    DIRECTION OUTPUT ;
    USE SIGNAL ;
    PORT
      LAYER M4 ;
        RECT  21.408 14.544 21.6 14.568 ;
    END
  END o0[60]
  PIN o0[61]
    DIRECTION OUTPUT ;
    USE SIGNAL ;
    PORT
      LAYER M4 ;
        RECT  21.408 14.688 21.6 14.712 ;
    END
  END o0[61]
  PIN o0[62]
    DIRECTION OUTPUT ;
    USE SIGNAL ;
    PORT
      LAYER M4 ;
        RECT  21.408 14.832 21.6 14.856 ;
    END
  END o0[62]
  PIN o0[63]
    DIRECTION OUTPUT ;
    USE SIGNAL ;
    PORT
      LAYER M4 ;
        RECT  21.408 15.024 21.6 15.048 ;
    END
  END o0[63]
  PIN o0[64]
    DIRECTION OUTPUT ;
    USE SIGNAL ;
    PORT
      LAYER M4 ;
        RECT  21.408 15.168 21.6 15.192 ;
    END
  END o0[64]
  PIN o0[65]
    DIRECTION OUTPUT ;
    USE SIGNAL ;
    PORT
      LAYER M4 ;
        RECT  21.408 15.36 21.6 15.384 ;
    END
  END o0[65]
  PIN o0[66]
    DIRECTION OUTPUT ;
    USE SIGNAL ;
    PORT
      LAYER M4 ;
        RECT  21.408 15.504 21.6 15.528 ;
    END
  END o0[66]
  PIN o0[67]
    DIRECTION OUTPUT ;
    USE SIGNAL ;
    PORT
      LAYER M4 ;
        RECT  21.408 15.696 21.6 15.72 ;
    END
  END o0[67]
  PIN o0[68]
    DIRECTION OUTPUT ;
    USE SIGNAL ;
    PORT
      LAYER M4 ;
        RECT  21.408 16.032 21.6 16.056 ;
    END
  END o0[68]
  PIN o0[69]
    DIRECTION OUTPUT ;
    USE SIGNAL ;
    PORT
      LAYER M4 ;
        RECT  21.408 16.176 21.6 16.2 ;
    END
  END o0[69]
  PIN o0[6]
    DIRECTION OUTPUT ;
    USE SIGNAL ;
    PORT
      LAYER M4 ;
        RECT  21.408 5.52 21.6 5.544 ;
    END
  END o0[6]
  PIN o0[70]
    DIRECTION OUTPUT ;
    USE SIGNAL ;
    PORT
      LAYER M4 ;
        RECT  21.408 16.368 21.6 16.392 ;
    END
  END o0[70]
  PIN o0[71]
    DIRECTION OUTPUT ;
    USE SIGNAL ;
    PORT
      LAYER M4 ;
        RECT  21.408 16.512 21.6 16.536 ;
    END
  END o0[71]
  PIN o0[72]
    DIRECTION OUTPUT ;
    USE SIGNAL ;
    PORT
      LAYER M4 ;
        RECT  21.408 16.704 21.6 16.728 ;
    END
  END o0[72]
  PIN o0[73]
    DIRECTION OUTPUT ;
    USE SIGNAL ;
    PORT
      LAYER M4 ;
        RECT  21.408 16.848 21.6 16.872 ;
    END
  END o0[73]
  PIN o0[74]
    DIRECTION OUTPUT ;
    USE SIGNAL ;
    PORT
      LAYER M4 ;
        RECT  21.408 17.04 21.6 17.064 ;
    END
  END o0[74]
  PIN o0[75]
    DIRECTION OUTPUT ;
    USE SIGNAL ;
    PORT
      LAYER M4 ;
        RECT  21.408 17.184 21.6 17.208 ;
    END
  END o0[75]
  PIN o0[76]
    DIRECTION OUTPUT ;
    USE SIGNAL ;
    PORT
      LAYER M4 ;
        RECT  21.408 17.328 21.6 17.352 ;
    END
  END o0[76]
  PIN o0[77]
    DIRECTION OUTPUT ;
    USE SIGNAL ;
    PORT
      LAYER M4 ;
        RECT  21.408 17.52 21.6 17.544 ;
    END
  END o0[77]
  PIN o0[78]
    DIRECTION OUTPUT ;
    USE SIGNAL ;
    PORT
      LAYER M4 ;
        RECT  21.408 17.664 21.6 17.688 ;
    END
  END o0[78]
  PIN o0[79]
    DIRECTION OUTPUT ;
    USE SIGNAL ;
    PORT
      LAYER M4 ;
        RECT  21.408 17.856 21.6 17.88 ;
    END
  END o0[79]
  PIN o0[7]
    DIRECTION OUTPUT ;
    USE SIGNAL ;
    PORT
      LAYER M4 ;
        RECT  21.408 5.712 21.6 5.736 ;
    END
  END o0[7]
  PIN o0[80]
    DIRECTION OUTPUT ;
    USE SIGNAL ;
    PORT
      LAYER M4 ;
        RECT  21.408 18 21.6 18.024 ;
    END
  END o0[80]
  PIN o0[81]
    DIRECTION OUTPUT ;
    USE SIGNAL ;
    PORT
      LAYER M4 ;
        RECT  21.408 18.192 21.6 18.216 ;
    END
  END o0[81]
  PIN o0[82]
    DIRECTION OUTPUT ;
    USE SIGNAL ;
    PORT
      LAYER M4 ;
        RECT  21.408 18.336 21.6 18.36 ;
    END
  END o0[82]
  PIN o0[83]
    DIRECTION OUTPUT ;
    USE SIGNAL ;
    PORT
      LAYER M4 ;
        RECT  21.408 18.528 21.6 18.552 ;
    END
  END o0[83]
  PIN o0[84]
    DIRECTION OUTPUT ;
    USE SIGNAL ;
    PORT
      LAYER M4 ;
        RECT  21.408 18.672 21.6 18.696 ;
    END
  END o0[84]
  PIN o0[85]
    DIRECTION OUTPUT ;
    USE SIGNAL ;
    PORT
      LAYER M4 ;
        RECT  21.408 18.864 21.6 18.888 ;
    END
  END o0[85]
  PIN o0[86]
    DIRECTION OUTPUT ;
    USE SIGNAL ;
    PORT
      LAYER M4 ;
        RECT  21.408 19.008 21.6 19.032 ;
    END
  END o0[86]
  PIN o0[87]
    DIRECTION OUTPUT ;
    USE SIGNAL ;
    PORT
      LAYER M4 ;
        RECT  21.408 19.2 21.6 19.224 ;
    END
  END o0[87]
  PIN o0[88]
    DIRECTION OUTPUT ;
    USE SIGNAL ;
    PORT
      LAYER M4 ;
        RECT  21.408 19.344 21.6 19.368 ;
    END
  END o0[88]
  PIN o0[89]
    DIRECTION OUTPUT ;
    USE SIGNAL ;
    PORT
      LAYER M4 ;
        RECT  21.408 19.536 21.6 19.56 ;
    END
  END o0[89]
  PIN o0[8]
    DIRECTION OUTPUT ;
    USE SIGNAL ;
    PORT
      LAYER M4 ;
        RECT  21.408 5.856 21.6 5.88 ;
    END
  END o0[8]
  PIN o0[90]
    DIRECTION OUTPUT ;
    USE SIGNAL ;
    PORT
      LAYER M4 ;
        RECT  21.408 19.68 21.6 19.704 ;
    END
  END o0[90]
  PIN o0[91]
    DIRECTION OUTPUT ;
    USE SIGNAL ;
    PORT
      LAYER M4 ;
        RECT  21.408 19.824 21.6 19.848 ;
    END
  END o0[91]
  PIN o0[92]
    DIRECTION OUTPUT ;
    USE SIGNAL ;
    PORT
      LAYER M4 ;
        RECT  21.408 20.016 21.6 20.04 ;
    END
  END o0[92]
  PIN o0[93]
    DIRECTION OUTPUT ;
    USE SIGNAL ;
    PORT
      LAYER M4 ;
        RECT  21.408 20.16 21.6 20.184 ;
    END
  END o0[93]
  PIN o0[94]
    DIRECTION OUTPUT ;
    USE SIGNAL ;
    PORT
      LAYER M4 ;
        RECT  21.408 20.352 21.6 20.376 ;
    END
  END o0[94]
  PIN o0[95]
    DIRECTION OUTPUT ;
    USE SIGNAL ;
    PORT
      LAYER M4 ;
        RECT  21.408 20.496 21.6 20.52 ;
    END
  END o0[95]
  PIN o0[96]
    DIRECTION OUTPUT ;
    USE SIGNAL ;
    PORT
      LAYER M4 ;
        RECT  21.408 20.688 21.6 20.712 ;
    END
  END o0[96]
  PIN o0[97]
    DIRECTION OUTPUT ;
    USE SIGNAL ;
    PORT
      LAYER M4 ;
        RECT  21.408 20.832 21.6 20.856 ;
    END
  END o0[97]
  PIN o0[98]
    DIRECTION OUTPUT ;
    USE SIGNAL ;
    PORT
      LAYER M4 ;
        RECT  21.408 21.024 21.6 21.048 ;
    END
  END o0[98]
  PIN o0[99]
    DIRECTION OUTPUT ;
    USE SIGNAL ;
    PORT
      LAYER M4 ;
        RECT  21.408 21.168 21.6 21.192 ;
    END
  END o0[99]
  PIN o0[9]
    DIRECTION OUTPUT ;
    USE SIGNAL ;
    PORT
      LAYER M4 ;
        RECT  21.408 6.048 21.6 6.072 ;
    END
  END o0[9]
  PIN o1[0]
    DIRECTION OUTPUT ;
    USE SIGNAL ;
    PORT
      LAYER M4 ;
        RECT  21.408 27.552 21.6 27.576 ;
    END
  END o1[0]
  PIN o1[100]
    DIRECTION OUTPUT ;
    USE SIGNAL ;
    PORT
      LAYER M4 ;
        RECT  21.408 44.4 21.6 44.424 ;
    END
  END o1[100]
  PIN o1[101]
    DIRECTION OUTPUT ;
    USE SIGNAL ;
    PORT
      LAYER M4 ;
        RECT  21.408 44.544 21.6 44.568 ;
    END
  END o1[101]
  PIN o1[102]
    DIRECTION OUTPUT ;
    USE SIGNAL ;
    PORT
      LAYER M4 ;
        RECT  21.408 44.736 21.6 44.76 ;
    END
  END o1[102]
  PIN o1[103]
    DIRECTION OUTPUT ;
    USE SIGNAL ;
    PORT
      LAYER M4 ;
        RECT  21.408 44.88 21.6 44.904 ;
    END
  END o1[103]
  PIN o1[104]
    DIRECTION OUTPUT ;
    USE SIGNAL ;
    PORT
      LAYER M4 ;
        RECT  21.408 45.072 21.6 45.096 ;
    END
  END o1[104]
  PIN o1[105]
    DIRECTION OUTPUT ;
    USE SIGNAL ;
    PORT
      LAYER M4 ;
        RECT  21.408 45.216 21.6 45.24 ;
    END
  END o1[105]
  PIN o1[106]
    DIRECTION OUTPUT ;
    USE SIGNAL ;
    PORT
      LAYER M4 ;
        RECT  21.408 45.408 21.6 45.432 ;
    END
  END o1[106]
  PIN o1[107]
    DIRECTION OUTPUT ;
    USE SIGNAL ;
    PORT
      LAYER M4 ;
        RECT  21.408 45.552 21.6 45.576 ;
    END
  END o1[107]
  PIN o1[108]
    DIRECTION OUTPUT ;
    USE SIGNAL ;
    PORT
      LAYER M4 ;
        RECT  21.408 45.696 21.6 45.72 ;
    END
  END o1[108]
  PIN o1[109]
    DIRECTION OUTPUT ;
    USE SIGNAL ;
    PORT
      LAYER M4 ;
        RECT  21.408 45.888 21.6 45.912 ;
    END
  END o1[109]
  PIN o1[10]
    DIRECTION OUTPUT ;
    USE SIGNAL ;
    PORT
      LAYER M4 ;
        RECT  21.408 29.232 21.6 29.256 ;
    END
  END o1[10]
  PIN o1[110]
    DIRECTION OUTPUT ;
    USE SIGNAL ;
    PORT
      LAYER M4 ;
        RECT  21.408 46.032 21.6 46.056 ;
    END
  END o1[110]
  PIN o1[111]
    DIRECTION OUTPUT ;
    USE SIGNAL ;
    PORT
      LAYER M4 ;
        RECT  21.408 46.224 21.6 46.248 ;
    END
  END o1[111]
  PIN o1[112]
    DIRECTION OUTPUT ;
    USE SIGNAL ;
    PORT
      LAYER M4 ;
        RECT  21.408 46.368 21.6 46.392 ;
    END
  END o1[112]
  PIN o1[113]
    DIRECTION OUTPUT ;
    USE SIGNAL ;
    PORT
      LAYER M4 ;
        RECT  21.408 46.56 21.6 46.584 ;
    END
  END o1[113]
  PIN o1[114]
    DIRECTION OUTPUT ;
    USE SIGNAL ;
    PORT
      LAYER M4 ;
        RECT  21.408 46.704 21.6 46.728 ;
    END
  END o1[114]
  PIN o1[115]
    DIRECTION OUTPUT ;
    USE SIGNAL ;
    PORT
      LAYER M4 ;
        RECT  21.408 46.896 21.6 46.92 ;
    END
  END o1[115]
  PIN o1[116]
    DIRECTION OUTPUT ;
    USE SIGNAL ;
    PORT
      LAYER M4 ;
        RECT  21.408 47.04 21.6 47.064 ;
    END
  END o1[116]
  PIN o1[117]
    DIRECTION OUTPUT ;
    USE SIGNAL ;
    PORT
      LAYER M4 ;
        RECT  21.408 47.232 21.6 47.256 ;
    END
  END o1[117]
  PIN o1[118]
    DIRECTION OUTPUT ;
    USE SIGNAL ;
    PORT
      LAYER M4 ;
        RECT  21.408 47.376 21.6 47.4 ;
    END
  END o1[118]
  PIN o1[119]
    DIRECTION OUTPUT ;
    USE SIGNAL ;
    PORT
      LAYER M4 ;
        RECT  21.408 47.568 21.6 47.592 ;
    END
  END o1[119]
  PIN o1[11]
    DIRECTION OUTPUT ;
    USE SIGNAL ;
    PORT
      LAYER M4 ;
        RECT  21.408 29.424 21.6 29.448 ;
    END
  END o1[11]
  PIN o1[120]
    DIRECTION OUTPUT ;
    USE SIGNAL ;
    PORT
      LAYER M4 ;
        RECT  21.408 47.712 21.6 47.736 ;
    END
  END o1[120]
  PIN o1[121]
    DIRECTION OUTPUT ;
    USE SIGNAL ;
    PORT
      LAYER M4 ;
        RECT  21.408 47.904 21.6 47.928 ;
    END
  END o1[121]
  PIN o1[122]
    DIRECTION OUTPUT ;
    USE SIGNAL ;
    PORT
      LAYER M4 ;
        RECT  21.408 48.048 21.6 48.072 ;
    END
  END o1[122]
  PIN o1[123]
    DIRECTION OUTPUT ;
    USE SIGNAL ;
    PORT
      LAYER M4 ;
        RECT  21.408 48.192 21.6 48.216 ;
    END
  END o1[123]
  PIN o1[124]
    DIRECTION OUTPUT ;
    USE SIGNAL ;
    PORT
      LAYER M4 ;
        RECT  21.408 48.384 21.6 48.408 ;
    END
  END o1[124]
  PIN o1[125]
    DIRECTION OUTPUT ;
    USE SIGNAL ;
    PORT
      LAYER M4 ;
        RECT  21.408 48.528 21.6 48.552 ;
    END
  END o1[125]
  PIN o1[126]
    DIRECTION OUTPUT ;
    USE SIGNAL ;
    PORT
      LAYER M4 ;
        RECT  21.408 48.72 21.6 48.744 ;
    END
  END o1[126]
  PIN o1[127]
    DIRECTION OUTPUT ;
    USE SIGNAL ;
    PORT
      LAYER M4 ;
        RECT  21.408 48.864 21.6 48.888 ;
    END
  END o1[127]
  PIN o1[128]
    DIRECTION OUTPUT ;
    USE SIGNAL ;
    PORT
      LAYER M4 ;
        RECT  21.408 49.056 21.6 49.08 ;
    END
  END o1[128]
  PIN o1[129]
    DIRECTION OUTPUT ;
    USE SIGNAL ;
    PORT
      LAYER M4 ;
        RECT  21.408 49.2 21.6 49.224 ;
    END
  END o1[129]
  PIN o1[12]
    DIRECTION OUTPUT ;
    USE SIGNAL ;
    PORT
      LAYER M4 ;
        RECT  21.408 29.568 21.6 29.592 ;
    END
  END o1[12]
  PIN o1[130]
    DIRECTION OUTPUT ;
    USE SIGNAL ;
    PORT
      LAYER M4 ;
        RECT  21.408 49.392 21.6 49.416 ;
    END
  END o1[130]
  PIN o1[131]
    DIRECTION OUTPUT ;
    USE SIGNAL ;
    PORT
      LAYER M4 ;
        RECT  21.408 49.536 21.6 49.56 ;
    END
  END o1[131]
  PIN o1[132]
    DIRECTION OUTPUT ;
    USE SIGNAL ;
    PORT
      LAYER M4 ;
        RECT  21.408 49.728 21.6 49.752 ;
    END
  END o1[132]
  PIN o1[133]
    DIRECTION OUTPUT ;
    USE SIGNAL ;
    PORT
      LAYER M4 ;
        RECT  21.408 49.872 21.6 49.896 ;
    END
  END o1[133]
  PIN o1[134]
    DIRECTION OUTPUT ;
    USE SIGNAL ;
    PORT
      LAYER M4 ;
        RECT  21.408 50.064 21.6 50.088 ;
    END
  END o1[134]
  PIN o1[135]
    DIRECTION OUTPUT ;
    USE SIGNAL ;
    PORT
      LAYER M4 ;
        RECT  21.408 50.208 21.6 50.232 ;
    END
  END o1[135]
  PIN o1[13]
    DIRECTION OUTPUT ;
    USE SIGNAL ;
    PORT
      LAYER M4 ;
        RECT  21.408 29.76 21.6 29.784 ;
    END
  END o1[13]
  PIN o1[14]
    DIRECTION OUTPUT ;
    USE SIGNAL ;
    PORT
      LAYER M4 ;
        RECT  21.408 29.904 21.6 29.928 ;
    END
  END o1[14]
  PIN o1[15]
    DIRECTION OUTPUT ;
    USE SIGNAL ;
    PORT
      LAYER M4 ;
        RECT  21.408 30.048 21.6 30.072 ;
    END
  END o1[15]
  PIN o1[16]
    DIRECTION OUTPUT ;
    USE SIGNAL ;
    PORT
      LAYER M4 ;
        RECT  21.408 30.24 21.6 30.264 ;
    END
  END o1[16]
  PIN o1[17]
    DIRECTION OUTPUT ;
    USE SIGNAL ;
    PORT
      LAYER M4 ;
        RECT  21.408 30.384 21.6 30.408 ;
    END
  END o1[17]
  PIN o1[18]
    DIRECTION OUTPUT ;
    USE SIGNAL ;
    PORT
      LAYER M4 ;
        RECT  21.408 30.576 21.6 30.6 ;
    END
  END o1[18]
  PIN o1[19]
    DIRECTION OUTPUT ;
    USE SIGNAL ;
    PORT
      LAYER M4 ;
        RECT  21.408 30.72 21.6 30.744 ;
    END
  END o1[19]
  PIN o1[1]
    DIRECTION OUTPUT ;
    USE SIGNAL ;
    PORT
      LAYER M4 ;
        RECT  21.408 27.744 21.6 27.768 ;
    END
  END o1[1]
  PIN o1[20]
    DIRECTION OUTPUT ;
    USE SIGNAL ;
    PORT
      LAYER M4 ;
        RECT  21.408 30.912 21.6 30.936 ;
    END
  END o1[20]
  PIN o1[21]
    DIRECTION OUTPUT ;
    USE SIGNAL ;
    PORT
      LAYER M4 ;
        RECT  21.408 31.056 21.6 31.08 ;
    END
  END o1[21]
  PIN o1[22]
    DIRECTION OUTPUT ;
    USE SIGNAL ;
    PORT
      LAYER M4 ;
        RECT  21.408 31.248 21.6 31.272 ;
    END
  END o1[22]
  PIN o1[23]
    DIRECTION OUTPUT ;
    USE SIGNAL ;
    PORT
      LAYER M4 ;
        RECT  21.408 31.392 21.6 31.416 ;
    END
  END o1[23]
  PIN o1[24]
    DIRECTION OUTPUT ;
    USE SIGNAL ;
    PORT
      LAYER M4 ;
        RECT  21.408 31.584 21.6 31.608 ;
    END
  END o1[24]
  PIN o1[25]
    DIRECTION OUTPUT ;
    USE SIGNAL ;
    PORT
      LAYER M4 ;
        RECT  21.408 31.728 21.6 31.752 ;
    END
  END o1[25]
  PIN o1[26]
    DIRECTION OUTPUT ;
    USE SIGNAL ;
    PORT
      LAYER M4 ;
        RECT  21.408 31.92 21.6 31.944 ;
    END
  END o1[26]
  PIN o1[27]
    DIRECTION OUTPUT ;
    USE SIGNAL ;
    PORT
      LAYER M4 ;
        RECT  21.408 32.064 21.6 32.088 ;
    END
  END o1[27]
  PIN o1[28]
    DIRECTION OUTPUT ;
    USE SIGNAL ;
    PORT
      LAYER M4 ;
        RECT  21.408 32.256 21.6 32.28 ;
    END
  END o1[28]
  PIN o1[29]
    DIRECTION OUTPUT ;
    USE SIGNAL ;
    PORT
      LAYER M4 ;
        RECT  21.408 32.4 21.6 32.424 ;
    END
  END o1[29]
  PIN o1[2]
    DIRECTION OUTPUT ;
    USE SIGNAL ;
    PORT
      LAYER M4 ;
        RECT  21.408 27.888 21.6 27.912 ;
    END
  END o1[2]
  PIN o1[30]
    DIRECTION OUTPUT ;
    USE SIGNAL ;
    PORT
      LAYER M4 ;
        RECT  21.408 32.544 21.6 32.568 ;
    END
  END o1[30]
  PIN o1[31]
    DIRECTION OUTPUT ;
    USE SIGNAL ;
    PORT
      LAYER M4 ;
        RECT  21.408 32.736 21.6 32.76 ;
    END
  END o1[31]
  PIN o1[32]
    DIRECTION OUTPUT ;
    USE SIGNAL ;
    PORT
      LAYER M4 ;
        RECT  21.408 32.88 21.6 32.904 ;
    END
  END o1[32]
  PIN o1[33]
    DIRECTION OUTPUT ;
    USE SIGNAL ;
    PORT
      LAYER M4 ;
        RECT  21.408 33.072 21.6 33.096 ;
    END
  END o1[33]
  PIN o1[34]
    DIRECTION OUTPUT ;
    USE SIGNAL ;
    PORT
      LAYER M4 ;
        RECT  21.408 33.216 21.6 33.24 ;
    END
  END o1[34]
  PIN o1[35]
    DIRECTION OUTPUT ;
    USE SIGNAL ;
    PORT
      LAYER M4 ;
        RECT  21.408 33.408 21.6 33.432 ;
    END
  END o1[35]
  PIN o1[36]
    DIRECTION OUTPUT ;
    USE SIGNAL ;
    PORT
      LAYER M4 ;
        RECT  21.408 33.552 21.6 33.576 ;
    END
  END o1[36]
  PIN o1[37]
    DIRECTION OUTPUT ;
    USE SIGNAL ;
    PORT
      LAYER M4 ;
        RECT  21.408 33.744 21.6 33.768 ;
    END
  END o1[37]
  PIN o1[38]
    DIRECTION OUTPUT ;
    USE SIGNAL ;
    PORT
      LAYER M4 ;
        RECT  21.408 33.888 21.6 33.912 ;
    END
  END o1[38]
  PIN o1[39]
    DIRECTION OUTPUT ;
    USE SIGNAL ;
    PORT
      LAYER M4 ;
        RECT  21.408 34.08 21.6 34.104 ;
    END
  END o1[39]
  PIN o1[3]
    DIRECTION OUTPUT ;
    USE SIGNAL ;
    PORT
      LAYER M4 ;
        RECT  21.408 28.08 21.6 28.104 ;
    END
  END o1[3]
  PIN o1[40]
    DIRECTION OUTPUT ;
    USE SIGNAL ;
    PORT
      LAYER M4 ;
        RECT  21.408 34.224 21.6 34.248 ;
    END
  END o1[40]
  PIN o1[41]
    DIRECTION OUTPUT ;
    USE SIGNAL ;
    PORT
      LAYER M4 ;
        RECT  21.408 34.416 21.6 34.44 ;
    END
  END o1[41]
  PIN o1[42]
    DIRECTION OUTPUT ;
    USE SIGNAL ;
    PORT
      LAYER M4 ;
        RECT  21.408 34.56 21.6 34.584 ;
    END
  END o1[42]
  PIN o1[43]
    DIRECTION OUTPUT ;
    USE SIGNAL ;
    PORT
      LAYER M4 ;
        RECT  21.408 34.752 21.6 34.776 ;
    END
  END o1[43]
  PIN o1[44]
    DIRECTION OUTPUT ;
    USE SIGNAL ;
    PORT
      LAYER M4 ;
        RECT  21.408 34.896 21.6 34.92 ;
    END
  END o1[44]
  PIN o1[45]
    DIRECTION OUTPUT ;
    USE SIGNAL ;
    PORT
      LAYER M4 ;
        RECT  21.408 35.04 21.6 35.064 ;
    END
  END o1[45]
  PIN o1[46]
    DIRECTION OUTPUT ;
    USE SIGNAL ;
    PORT
      LAYER M4 ;
        RECT  21.408 35.232 21.6 35.256 ;
    END
  END o1[46]
  PIN o1[47]
    DIRECTION OUTPUT ;
    USE SIGNAL ;
    PORT
      LAYER M4 ;
        RECT  21.408 35.376 21.6 35.4 ;
    END
  END o1[47]
  PIN o1[48]
    DIRECTION OUTPUT ;
    USE SIGNAL ;
    PORT
      LAYER M4 ;
        RECT  21.408 35.568 21.6 35.592 ;
    END
  END o1[48]
  PIN o1[49]
    DIRECTION OUTPUT ;
    USE SIGNAL ;
    PORT
      LAYER M4 ;
        RECT  21.408 35.712 21.6 35.736 ;
    END
  END o1[49]
  PIN o1[4]
    DIRECTION OUTPUT ;
    USE SIGNAL ;
    PORT
      LAYER M4 ;
        RECT  21.408 28.224 21.6 28.248 ;
    END
  END o1[4]
  PIN o1[50]
    DIRECTION OUTPUT ;
    USE SIGNAL ;
    PORT
      LAYER M4 ;
        RECT  21.408 35.904 21.6 35.928 ;
    END
  END o1[50]
  PIN o1[51]
    DIRECTION OUTPUT ;
    USE SIGNAL ;
    PORT
      LAYER M4 ;
        RECT  21.408 36.048 21.6 36.072 ;
    END
  END o1[51]
  PIN o1[52]
    DIRECTION OUTPUT ;
    USE SIGNAL ;
    PORT
      LAYER M4 ;
        RECT  21.408 36.24 21.6 36.264 ;
    END
  END o1[52]
  PIN o1[53]
    DIRECTION OUTPUT ;
    USE SIGNAL ;
    PORT
      LAYER M4 ;
        RECT  21.408 36.384 21.6 36.408 ;
    END
  END o1[53]
  PIN o1[54]
    DIRECTION OUTPUT ;
    USE SIGNAL ;
    PORT
      LAYER M4 ;
        RECT  21.408 36.576 21.6 36.6 ;
    END
  END o1[54]
  PIN o1[55]
    DIRECTION OUTPUT ;
    USE SIGNAL ;
    PORT
      LAYER M4 ;
        RECT  21.408 36.72 21.6 36.744 ;
    END
  END o1[55]
  PIN o1[56]
    DIRECTION OUTPUT ;
    USE SIGNAL ;
    PORT
      LAYER M4 ;
        RECT  21.408 36.912 21.6 36.936 ;
    END
  END o1[56]
  PIN o1[57]
    DIRECTION OUTPUT ;
    USE SIGNAL ;
    PORT
      LAYER M4 ;
        RECT  21.408 37.056 21.6 37.08 ;
    END
  END o1[57]
  PIN o1[58]
    DIRECTION OUTPUT ;
    USE SIGNAL ;
    PORT
      LAYER M4 ;
        RECT  21.408 37.248 21.6 37.272 ;
    END
  END o1[58]
  PIN o1[59]
    DIRECTION OUTPUT ;
    USE SIGNAL ;
    PORT
      LAYER M4 ;
        RECT  21.408 37.392 21.6 37.416 ;
    END
  END o1[59]
  PIN o1[5]
    DIRECTION OUTPUT ;
    USE SIGNAL ;
    PORT
      LAYER M4 ;
        RECT  21.408 28.416 21.6 28.44 ;
    END
  END o1[5]
  PIN o1[60]
    DIRECTION OUTPUT ;
    USE SIGNAL ;
    PORT
      LAYER M4 ;
        RECT  21.408 37.584 21.6 37.608 ;
    END
  END o1[60]
  PIN o1[61]
    DIRECTION OUTPUT ;
    USE SIGNAL ;
    PORT
      LAYER M4 ;
        RECT  21.408 37.728 21.6 37.752 ;
    END
  END o1[61]
  PIN o1[62]
    DIRECTION OUTPUT ;
    USE SIGNAL ;
    PORT
      LAYER M4 ;
        RECT  21.408 37.872 21.6 37.896 ;
    END
  END o1[62]
  PIN o1[63]
    DIRECTION OUTPUT ;
    USE SIGNAL ;
    PORT
      LAYER M4 ;
        RECT  21.408 38.064 21.6 38.088 ;
    END
  END o1[63]
  PIN o1[64]
    DIRECTION OUTPUT ;
    USE SIGNAL ;
    PORT
      LAYER M4 ;
        RECT  21.408 38.208 21.6 38.232 ;
    END
  END o1[64]
  PIN o1[65]
    DIRECTION OUTPUT ;
    USE SIGNAL ;
    PORT
      LAYER M4 ;
        RECT  21.408 38.4 21.6 38.424 ;
    END
  END o1[65]
  PIN o1[66]
    DIRECTION OUTPUT ;
    USE SIGNAL ;
    PORT
      LAYER M4 ;
        RECT  21.408 38.544 21.6 38.568 ;
    END
  END o1[66]
  PIN o1[67]
    DIRECTION OUTPUT ;
    USE SIGNAL ;
    PORT
      LAYER M4 ;
        RECT  21.408 38.736 21.6 38.76 ;
    END
  END o1[67]
  PIN o1[68]
    DIRECTION OUTPUT ;
    USE SIGNAL ;
    PORT
      LAYER M4 ;
        RECT  21.408 39.072 21.6 39.096 ;
    END
  END o1[68]
  PIN o1[69]
    DIRECTION OUTPUT ;
    USE SIGNAL ;
    PORT
      LAYER M4 ;
        RECT  21.408 39.216 21.6 39.24 ;
    END
  END o1[69]
  PIN o1[6]
    DIRECTION OUTPUT ;
    USE SIGNAL ;
    PORT
      LAYER M4 ;
        RECT  21.408 28.56 21.6 28.584 ;
    END
  END o1[6]
  PIN o1[70]
    DIRECTION OUTPUT ;
    USE SIGNAL ;
    PORT
      LAYER M4 ;
        RECT  21.408 39.408 21.6 39.432 ;
    END
  END o1[70]
  PIN o1[71]
    DIRECTION OUTPUT ;
    USE SIGNAL ;
    PORT
      LAYER M4 ;
        RECT  21.408 39.552 21.6 39.576 ;
    END
  END o1[71]
  PIN o1[72]
    DIRECTION OUTPUT ;
    USE SIGNAL ;
    PORT
      LAYER M4 ;
        RECT  21.408 39.744 21.6 39.768 ;
    END
  END o1[72]
  PIN o1[73]
    DIRECTION OUTPUT ;
    USE SIGNAL ;
    PORT
      LAYER M4 ;
        RECT  21.408 39.888 21.6 39.912 ;
    END
  END o1[73]
  PIN o1[74]
    DIRECTION OUTPUT ;
    USE SIGNAL ;
    PORT
      LAYER M4 ;
        RECT  21.408 40.08 21.6 40.104 ;
    END
  END o1[74]
  PIN o1[75]
    DIRECTION OUTPUT ;
    USE SIGNAL ;
    PORT
      LAYER M4 ;
        RECT  21.408 40.224 21.6 40.248 ;
    END
  END o1[75]
  PIN o1[76]
    DIRECTION OUTPUT ;
    USE SIGNAL ;
    PORT
      LAYER M4 ;
        RECT  21.408 40.368 21.6 40.392 ;
    END
  END o1[76]
  PIN o1[77]
    DIRECTION OUTPUT ;
    USE SIGNAL ;
    PORT
      LAYER M4 ;
        RECT  21.408 40.56 21.6 40.584 ;
    END
  END o1[77]
  PIN o1[78]
    DIRECTION OUTPUT ;
    USE SIGNAL ;
    PORT
      LAYER M4 ;
        RECT  21.408 40.704 21.6 40.728 ;
    END
  END o1[78]
  PIN o1[79]
    DIRECTION OUTPUT ;
    USE SIGNAL ;
    PORT
      LAYER M4 ;
        RECT  21.408 40.896 21.6 40.92 ;
    END
  END o1[79]
  PIN o1[7]
    DIRECTION OUTPUT ;
    USE SIGNAL ;
    PORT
      LAYER M4 ;
        RECT  21.408 28.752 21.6 28.776 ;
    END
  END o1[7]
  PIN o1[80]
    DIRECTION OUTPUT ;
    USE SIGNAL ;
    PORT
      LAYER M4 ;
        RECT  21.408 41.04 21.6 41.064 ;
    END
  END o1[80]
  PIN o1[81]
    DIRECTION OUTPUT ;
    USE SIGNAL ;
    PORT
      LAYER M4 ;
        RECT  21.408 41.232 21.6 41.256 ;
    END
  END o1[81]
  PIN o1[82]
    DIRECTION OUTPUT ;
    USE SIGNAL ;
    PORT
      LAYER M4 ;
        RECT  21.408 41.376 21.6 41.4 ;
    END
  END o1[82]
  PIN o1[83]
    DIRECTION OUTPUT ;
    USE SIGNAL ;
    PORT
      LAYER M4 ;
        RECT  21.408 41.568 21.6 41.592 ;
    END
  END o1[83]
  PIN o1[84]
    DIRECTION OUTPUT ;
    USE SIGNAL ;
    PORT
      LAYER M4 ;
        RECT  21.408 41.712 21.6 41.736 ;
    END
  END o1[84]
  PIN o1[85]
    DIRECTION OUTPUT ;
    USE SIGNAL ;
    PORT
      LAYER M4 ;
        RECT  21.408 41.904 21.6 41.928 ;
    END
  END o1[85]
  PIN o1[86]
    DIRECTION OUTPUT ;
    USE SIGNAL ;
    PORT
      LAYER M4 ;
        RECT  21.408 42.048 21.6 42.072 ;
    END
  END o1[86]
  PIN o1[87]
    DIRECTION OUTPUT ;
    USE SIGNAL ;
    PORT
      LAYER M4 ;
        RECT  21.408 42.24 21.6 42.264 ;
    END
  END o1[87]
  PIN o1[88]
    DIRECTION OUTPUT ;
    USE SIGNAL ;
    PORT
      LAYER M4 ;
        RECT  21.408 42.384 21.6 42.408 ;
    END
  END o1[88]
  PIN o1[89]
    DIRECTION OUTPUT ;
    USE SIGNAL ;
    PORT
      LAYER M4 ;
        RECT  21.408 42.576 21.6 42.6 ;
    END
  END o1[89]
  PIN o1[8]
    DIRECTION OUTPUT ;
    USE SIGNAL ;
    PORT
      LAYER M4 ;
        RECT  21.408 28.896 21.6 28.92 ;
    END
  END o1[8]
  PIN o1[90]
    DIRECTION OUTPUT ;
    USE SIGNAL ;
    PORT
      LAYER M4 ;
        RECT  21.408 42.72 21.6 42.744 ;
    END
  END o1[90]
  PIN o1[91]
    DIRECTION OUTPUT ;
    USE SIGNAL ;
    PORT
      LAYER M4 ;
        RECT  21.408 42.864 21.6 42.888 ;
    END
  END o1[91]
  PIN o1[92]
    DIRECTION OUTPUT ;
    USE SIGNAL ;
    PORT
      LAYER M4 ;
        RECT  21.408 43.056 21.6 43.08 ;
    END
  END o1[92]
  PIN o1[93]
    DIRECTION OUTPUT ;
    USE SIGNAL ;
    PORT
      LAYER M4 ;
        RECT  21.408 43.2 21.6 43.224 ;
    END
  END o1[93]
  PIN o1[94]
    DIRECTION OUTPUT ;
    USE SIGNAL ;
    PORT
      LAYER M4 ;
        RECT  21.408 43.392 21.6 43.416 ;
    END
  END o1[94]
  PIN o1[95]
    DIRECTION OUTPUT ;
    USE SIGNAL ;
    PORT
      LAYER M4 ;
        RECT  21.408 43.536 21.6 43.56 ;
    END
  END o1[95]
  PIN o1[96]
    DIRECTION OUTPUT ;
    USE SIGNAL ;
    PORT
      LAYER M4 ;
        RECT  21.408 43.728 21.6 43.752 ;
    END
  END o1[96]
  PIN o1[97]
    DIRECTION OUTPUT ;
    USE SIGNAL ;
    PORT
      LAYER M4 ;
        RECT  21.408 43.872 21.6 43.896 ;
    END
  END o1[97]
  PIN o1[98]
    DIRECTION OUTPUT ;
    USE SIGNAL ;
    PORT
      LAYER M4 ;
        RECT  21.408 44.064 21.6 44.088 ;
    END
  END o1[98]
  PIN o1[99]
    DIRECTION OUTPUT ;
    USE SIGNAL ;
    PORT
      LAYER M4 ;
        RECT  21.408 44.208 21.6 44.232 ;
    END
  END o1[99]
  PIN o1[9]
    DIRECTION OUTPUT ;
    USE SIGNAL ;
    PORT
      LAYER M4 ;
        RECT  21.408 29.088 21.6 29.112 ;
    END
  END o1[9]
  PIN o2[0]
    DIRECTION OUTPUT ;
    USE SIGNAL ;
    PORT
      LAYER M4 ;
        RECT  0 39.072 0.192 39.096 ;
    END
  END o2[0]
  PIN o2[100]
    DIRECTION OUTPUT ;
    USE SIGNAL ;
    PORT
      LAYER M4 ;
        RECT  0 64.464 0.192 64.488 ;
    END
  END o2[100]
  PIN o2[101]
    DIRECTION OUTPUT ;
    USE SIGNAL ;
    PORT
      LAYER M4 ;
        RECT  0 64.704 0.192 64.728 ;
    END
  END o2[101]
  PIN o2[102]
    DIRECTION OUTPUT ;
    USE SIGNAL ;
    PORT
      LAYER M4 ;
        RECT  0 64.944 0.192 64.968 ;
    END
  END o2[102]
  PIN o2[103]
    DIRECTION OUTPUT ;
    USE SIGNAL ;
    PORT
      LAYER M4 ;
        RECT  0 65.232 0.192 65.256 ;
    END
  END o2[103]
  PIN o2[104]
    DIRECTION OUTPUT ;
    USE SIGNAL ;
    PORT
      LAYER M4 ;
        RECT  0 65.472 0.192 65.496 ;
    END
  END o2[104]
  PIN o2[105]
    DIRECTION OUTPUT ;
    USE SIGNAL ;
    PORT
      LAYER M4 ;
        RECT  0 65.712 0.192 65.736 ;
    END
  END o2[105]
  PIN o2[106]
    DIRECTION OUTPUT ;
    USE SIGNAL ;
    PORT
      LAYER M4 ;
        RECT  0 65.952 0.192 65.976 ;
    END
  END o2[106]
  PIN o2[107]
    DIRECTION OUTPUT ;
    USE SIGNAL ;
    PORT
      LAYER M4 ;
        RECT  0 66.24 0.192 66.264 ;
    END
  END o2[107]
  PIN o2[108]
    DIRECTION OUTPUT ;
    USE SIGNAL ;
    PORT
      LAYER M4 ;
        RECT  0 66.48 0.192 66.504 ;
    END
  END o2[108]
  PIN o2[109]
    DIRECTION OUTPUT ;
    USE SIGNAL ;
    PORT
      LAYER M4 ;
        RECT  0 66.72 0.192 66.744 ;
    END
  END o2[109]
  PIN o2[10]
    DIRECTION OUTPUT ;
    USE SIGNAL ;
    PORT
      LAYER M4 ;
        RECT  0 41.616 0.192 41.64 ;
    END
  END o2[10]
  PIN o2[110]
    DIRECTION OUTPUT ;
    USE SIGNAL ;
    PORT
      LAYER M4 ;
        RECT  0 66.96 0.192 66.984 ;
    END
  END o2[110]
  PIN o2[111]
    DIRECTION OUTPUT ;
    USE SIGNAL ;
    PORT
      LAYER M4 ;
        RECT  0 67.2 0.192 67.224 ;
    END
  END o2[111]
  PIN o2[112]
    DIRECTION OUTPUT ;
    USE SIGNAL ;
    PORT
      LAYER M4 ;
        RECT  0 67.488 0.192 67.512 ;
    END
  END o2[112]
  PIN o2[113]
    DIRECTION OUTPUT ;
    USE SIGNAL ;
    PORT
      LAYER M4 ;
        RECT  0 67.728 0.192 67.752 ;
    END
  END o2[113]
  PIN o2[114]
    DIRECTION OUTPUT ;
    USE SIGNAL ;
    PORT
      LAYER M4 ;
        RECT  0 67.968 0.192 67.992 ;
    END
  END o2[114]
  PIN o2[115]
    DIRECTION OUTPUT ;
    USE SIGNAL ;
    PORT
      LAYER M4 ;
        RECT  0 68.208 0.192 68.232 ;
    END
  END o2[115]
  PIN o2[116]
    DIRECTION OUTPUT ;
    USE SIGNAL ;
    PORT
      LAYER M4 ;
        RECT  0 68.496 0.192 68.52 ;
    END
  END o2[116]
  PIN o2[117]
    DIRECTION OUTPUT ;
    USE SIGNAL ;
    PORT
      LAYER M4 ;
        RECT  0 68.736 0.192 68.76 ;
    END
  END o2[117]
  PIN o2[118]
    DIRECTION OUTPUT ;
    USE SIGNAL ;
    PORT
      LAYER M4 ;
        RECT  0 68.976 0.192 69 ;
    END
  END o2[118]
  PIN o2[119]
    DIRECTION OUTPUT ;
    USE SIGNAL ;
    PORT
      LAYER M4 ;
        RECT  0 69.216 0.192 69.24 ;
    END
  END o2[119]
  PIN o2[11]
    DIRECTION OUTPUT ;
    USE SIGNAL ;
    PORT
      LAYER M4 ;
        RECT  0 41.856 0.192 41.88 ;
    END
  END o2[11]
  PIN o2[120]
    DIRECTION OUTPUT ;
    USE SIGNAL ;
    PORT
      LAYER M4 ;
        RECT  0 69.504 0.192 69.528 ;
    END
  END o2[120]
  PIN o2[121]
    DIRECTION OUTPUT ;
    USE SIGNAL ;
    PORT
      LAYER M4 ;
        RECT  0 69.744 0.192 69.768 ;
    END
  END o2[121]
  PIN o2[122]
    DIRECTION OUTPUT ;
    USE SIGNAL ;
    PORT
      LAYER M4 ;
        RECT  0 69.984 0.192 70.008 ;
    END
  END o2[122]
  PIN o2[123]
    DIRECTION OUTPUT ;
    USE SIGNAL ;
    PORT
      LAYER M4 ;
        RECT  0 70.224 0.192 70.248 ;
    END
  END o2[123]
  PIN o2[124]
    DIRECTION OUTPUT ;
    USE SIGNAL ;
    PORT
      LAYER M4 ;
        RECT  0 70.512 0.192 70.536 ;
    END
  END o2[124]
  PIN o2[125]
    DIRECTION OUTPUT ;
    USE SIGNAL ;
    PORT
      LAYER M4 ;
        RECT  0 70.752 0.192 70.776 ;
    END
  END o2[125]
  PIN o2[126]
    DIRECTION OUTPUT ;
    USE SIGNAL ;
    PORT
      LAYER M4 ;
        RECT  0 70.992 0.192 71.016 ;
    END
  END o2[126]
  PIN o2[127]
    DIRECTION OUTPUT ;
    USE SIGNAL ;
    PORT
      LAYER M4 ;
        RECT  0 71.232 0.192 71.256 ;
    END
  END o2[127]
  PIN o2[128]
    DIRECTION OUTPUT ;
    USE SIGNAL ;
    PORT
      LAYER M4 ;
        RECT  0 71.472 0.192 71.496 ;
    END
  END o2[128]
  PIN o2[129]
    DIRECTION OUTPUT ;
    USE SIGNAL ;
    PORT
      LAYER M4 ;
        RECT  0 71.76 0.192 71.784 ;
    END
  END o2[129]
  PIN o2[12]
    DIRECTION OUTPUT ;
    USE SIGNAL ;
    PORT
      LAYER M4 ;
        RECT  0 42.096 0.192 42.12 ;
    END
  END o2[12]
  PIN o2[130]
    DIRECTION OUTPUT ;
    USE SIGNAL ;
    PORT
      LAYER M4 ;
        RECT  0 72 0.192 72.024 ;
    END
  END o2[130]
  PIN o2[131]
    DIRECTION OUTPUT ;
    USE SIGNAL ;
    PORT
      LAYER M4 ;
        RECT  0 72.24 0.192 72.264 ;
    END
  END o2[131]
  PIN o2[132]
    DIRECTION OUTPUT ;
    USE SIGNAL ;
    PORT
      LAYER M4 ;
        RECT  0 72.48 0.192 72.504 ;
    END
  END o2[132]
  PIN o2[133]
    DIRECTION OUTPUT ;
    USE SIGNAL ;
    PORT
      LAYER M4 ;
        RECT  0 72.768 0.192 72.792 ;
    END
  END o2[133]
  PIN o2[134]
    DIRECTION OUTPUT ;
    USE SIGNAL ;
    PORT
      LAYER M4 ;
        RECT  0 73.008 0.192 73.032 ;
    END
  END o2[134]
  PIN o2[135]
    DIRECTION OUTPUT ;
    USE SIGNAL ;
    PORT
      LAYER M4 ;
        RECT  0 73.248 0.192 73.272 ;
    END
  END o2[135]
  PIN o2[13]
    DIRECTION OUTPUT ;
    USE SIGNAL ;
    PORT
      LAYER M4 ;
        RECT  0 42.336 0.192 42.36 ;
    END
  END o2[13]
  PIN o2[14]
    DIRECTION OUTPUT ;
    USE SIGNAL ;
    PORT
      LAYER M4 ;
        RECT  0 42.624 0.192 42.648 ;
    END
  END o2[14]
  PIN o2[15]
    DIRECTION OUTPUT ;
    USE SIGNAL ;
    PORT
      LAYER M4 ;
        RECT  0 42.864 0.192 42.888 ;
    END
  END o2[15]
  PIN o2[16]
    DIRECTION OUTPUT ;
    USE SIGNAL ;
    PORT
      LAYER M4 ;
        RECT  0 43.104 0.192 43.128 ;
    END
  END o2[16]
  PIN o2[17]
    DIRECTION OUTPUT ;
    USE SIGNAL ;
    PORT
      LAYER M4 ;
        RECT  0 43.344 0.192 43.368 ;
    END
  END o2[17]
  PIN o2[18]
    DIRECTION OUTPUT ;
    USE SIGNAL ;
    PORT
      LAYER M4 ;
        RECT  0 43.632 0.192 43.656 ;
    END
  END o2[18]
  PIN o2[19]
    DIRECTION OUTPUT ;
    USE SIGNAL ;
    PORT
      LAYER M4 ;
        RECT  0 43.872 0.192 43.896 ;
    END
  END o2[19]
  PIN o2[1]
    DIRECTION OUTPUT ;
    USE SIGNAL ;
    PORT
      LAYER M4 ;
        RECT  0 39.36 0.192 39.384 ;
    END
  END o2[1]
  PIN o2[20]
    DIRECTION OUTPUT ;
    USE SIGNAL ;
    PORT
      LAYER M4 ;
        RECT  0 44.112 0.192 44.136 ;
    END
  END o2[20]
  PIN o2[21]
    DIRECTION OUTPUT ;
    USE SIGNAL ;
    PORT
      LAYER M4 ;
        RECT  0 44.352 0.192 44.376 ;
    END
  END o2[21]
  PIN o2[22]
    DIRECTION OUTPUT ;
    USE SIGNAL ;
    PORT
      LAYER M4 ;
        RECT  0 44.64 0.192 44.664 ;
    END
  END o2[22]
  PIN o2[23]
    DIRECTION OUTPUT ;
    USE SIGNAL ;
    PORT
      LAYER M4 ;
        RECT  0 44.88 0.192 44.904 ;
    END
  END o2[23]
  PIN o2[24]
    DIRECTION OUTPUT ;
    USE SIGNAL ;
    PORT
      LAYER M4 ;
        RECT  0 45.12 0.192 45.144 ;
    END
  END o2[24]
  PIN o2[25]
    DIRECTION OUTPUT ;
    USE SIGNAL ;
    PORT
      LAYER M4 ;
        RECT  0 45.36 0.192 45.384 ;
    END
  END o2[25]
  PIN o2[26]
    DIRECTION OUTPUT ;
    USE SIGNAL ;
    PORT
      LAYER M4 ;
        RECT  0 45.6 0.192 45.624 ;
    END
  END o2[26]
  PIN o2[27]
    DIRECTION OUTPUT ;
    USE SIGNAL ;
    PORT
      LAYER M4 ;
        RECT  0 45.888 0.192 45.912 ;
    END
  END o2[27]
  PIN o2[28]
    DIRECTION OUTPUT ;
    USE SIGNAL ;
    PORT
      LAYER M4 ;
        RECT  0 46.128 0.192 46.152 ;
    END
  END o2[28]
  PIN o2[29]
    DIRECTION OUTPUT ;
    USE SIGNAL ;
    PORT
      LAYER M4 ;
        RECT  0 46.368 0.192 46.392 ;
    END
  END o2[29]
  PIN o2[2]
    DIRECTION OUTPUT ;
    USE SIGNAL ;
    PORT
      LAYER M4 ;
        RECT  0 39.6 0.192 39.624 ;
    END
  END o2[2]
  PIN o2[30]
    DIRECTION OUTPUT ;
    USE SIGNAL ;
    PORT
      LAYER M4 ;
        RECT  0 46.608 0.192 46.632 ;
    END
  END o2[30]
  PIN o2[31]
    DIRECTION OUTPUT ;
    USE SIGNAL ;
    PORT
      LAYER M4 ;
        RECT  0 46.896 0.192 46.92 ;
    END
  END o2[31]
  PIN o2[32]
    DIRECTION OUTPUT ;
    USE SIGNAL ;
    PORT
      LAYER M4 ;
        RECT  0 47.136 0.192 47.16 ;
    END
  END o2[32]
  PIN o2[33]
    DIRECTION OUTPUT ;
    USE SIGNAL ;
    PORT
      LAYER M4 ;
        RECT  0 47.376 0.192 47.4 ;
    END
  END o2[33]
  PIN o2[34]
    DIRECTION OUTPUT ;
    USE SIGNAL ;
    PORT
      LAYER M4 ;
        RECT  0 47.616 0.192 47.64 ;
    END
  END o2[34]
  PIN o2[35]
    DIRECTION OUTPUT ;
    USE SIGNAL ;
    PORT
      LAYER M4 ;
        RECT  0 47.904 0.192 47.928 ;
    END
  END o2[35]
  PIN o2[36]
    DIRECTION OUTPUT ;
    USE SIGNAL ;
    PORT
      LAYER M4 ;
        RECT  0 48.144 0.192 48.168 ;
    END
  END o2[36]
  PIN o2[37]
    DIRECTION OUTPUT ;
    USE SIGNAL ;
    PORT
      LAYER M4 ;
        RECT  0 48.384 0.192 48.408 ;
    END
  END o2[37]
  PIN o2[38]
    DIRECTION OUTPUT ;
    USE SIGNAL ;
    PORT
      LAYER M4 ;
        RECT  0 48.624 0.192 48.648 ;
    END
  END o2[38]
  PIN o2[39]
    DIRECTION OUTPUT ;
    USE SIGNAL ;
    PORT
      LAYER M4 ;
        RECT  0 48.864 0.192 48.888 ;
    END
  END o2[39]
  PIN o2[3]
    DIRECTION OUTPUT ;
    USE SIGNAL ;
    PORT
      LAYER M4 ;
        RECT  0 39.84 0.192 39.864 ;
    END
  END o2[3]
  PIN o2[40]
    DIRECTION OUTPUT ;
    USE SIGNAL ;
    PORT
      LAYER M4 ;
        RECT  0 49.152 0.192 49.176 ;
    END
  END o2[40]
  PIN o2[41]
    DIRECTION OUTPUT ;
    USE SIGNAL ;
    PORT
      LAYER M4 ;
        RECT  0 49.392 0.192 49.416 ;
    END
  END o2[41]
  PIN o2[42]
    DIRECTION OUTPUT ;
    USE SIGNAL ;
    PORT
      LAYER M4 ;
        RECT  0 49.632 0.192 49.656 ;
    END
  END o2[42]
  PIN o2[43]
    DIRECTION OUTPUT ;
    USE SIGNAL ;
    PORT
      LAYER M4 ;
        RECT  0 49.872 0.192 49.896 ;
    END
  END o2[43]
  PIN o2[44]
    DIRECTION OUTPUT ;
    USE SIGNAL ;
    PORT
      LAYER M4 ;
        RECT  0 50.16 0.192 50.184 ;
    END
  END o2[44]
  PIN o2[45]
    DIRECTION OUTPUT ;
    USE SIGNAL ;
    PORT
      LAYER M4 ;
        RECT  0 50.4 0.192 50.424 ;
    END
  END o2[45]
  PIN o2[46]
    DIRECTION OUTPUT ;
    USE SIGNAL ;
    PORT
      LAYER M4 ;
        RECT  0 50.64 0.192 50.664 ;
    END
  END o2[46]
  PIN o2[47]
    DIRECTION OUTPUT ;
    USE SIGNAL ;
    PORT
      LAYER M4 ;
        RECT  0 50.88 0.192 50.904 ;
    END
  END o2[47]
  PIN o2[48]
    DIRECTION OUTPUT ;
    USE SIGNAL ;
    PORT
      LAYER M4 ;
        RECT  0 51.168 0.192 51.192 ;
    END
  END o2[48]
  PIN o2[49]
    DIRECTION OUTPUT ;
    USE SIGNAL ;
    PORT
      LAYER M4 ;
        RECT  0 51.408 0.192 51.432 ;
    END
  END o2[49]
  PIN o2[4]
    DIRECTION OUTPUT ;
    USE SIGNAL ;
    PORT
      LAYER M4 ;
        RECT  0 40.08 0.192 40.104 ;
    END
  END o2[4]
  PIN o2[50]
    DIRECTION OUTPUT ;
    USE SIGNAL ;
    PORT
      LAYER M4 ;
        RECT  0 51.648 0.192 51.672 ;
    END
  END o2[50]
  PIN o2[51]
    DIRECTION OUTPUT ;
    USE SIGNAL ;
    PORT
      LAYER M4 ;
        RECT  0 51.888 0.192 51.912 ;
    END
  END o2[51]
  PIN o2[52]
    DIRECTION OUTPUT ;
    USE SIGNAL ;
    PORT
      LAYER M4 ;
        RECT  0 52.176 0.192 52.2 ;
    END
  END o2[52]
  PIN o2[53]
    DIRECTION OUTPUT ;
    USE SIGNAL ;
    PORT
      LAYER M4 ;
        RECT  0 52.416 0.192 52.44 ;
    END
  END o2[53]
  PIN o2[54]
    DIRECTION OUTPUT ;
    USE SIGNAL ;
    PORT
      LAYER M4 ;
        RECT  0 52.656 0.192 52.68 ;
    END
  END o2[54]
  PIN o2[55]
    DIRECTION OUTPUT ;
    USE SIGNAL ;
    PORT
      LAYER M4 ;
        RECT  0 52.896 0.192 52.92 ;
    END
  END o2[55]
  PIN o2[56]
    DIRECTION OUTPUT ;
    USE SIGNAL ;
    PORT
      LAYER M4 ;
        RECT  0 53.136 0.192 53.16 ;
    END
  END o2[56]
  PIN o2[57]
    DIRECTION OUTPUT ;
    USE SIGNAL ;
    PORT
      LAYER M4 ;
        RECT  0 53.424 0.192 53.448 ;
    END
  END o2[57]
  PIN o2[58]
    DIRECTION OUTPUT ;
    USE SIGNAL ;
    PORT
      LAYER M4 ;
        RECT  0 53.664 0.192 53.688 ;
    END
  END o2[58]
  PIN o2[59]
    DIRECTION OUTPUT ;
    USE SIGNAL ;
    PORT
      LAYER M4 ;
        RECT  0 53.904 0.192 53.928 ;
    END
  END o2[59]
  PIN o2[5]
    DIRECTION OUTPUT ;
    USE SIGNAL ;
    PORT
      LAYER M4 ;
        RECT  0 40.368 0.192 40.392 ;
    END
  END o2[5]
  PIN o2[60]
    DIRECTION OUTPUT ;
    USE SIGNAL ;
    PORT
      LAYER M4 ;
        RECT  0 54.144 0.192 54.168 ;
    END
  END o2[60]
  PIN o2[61]
    DIRECTION OUTPUT ;
    USE SIGNAL ;
    PORT
      LAYER M4 ;
        RECT  0 54.432 0.192 54.456 ;
    END
  END o2[61]
  PIN o2[62]
    DIRECTION OUTPUT ;
    USE SIGNAL ;
    PORT
      LAYER M4 ;
        RECT  0 54.672 0.192 54.696 ;
    END
  END o2[62]
  PIN o2[63]
    DIRECTION OUTPUT ;
    USE SIGNAL ;
    PORT
      LAYER M4 ;
        RECT  0 54.912 0.192 54.936 ;
    END
  END o2[63]
  PIN o2[64]
    DIRECTION OUTPUT ;
    USE SIGNAL ;
    PORT
      LAYER M4 ;
        RECT  0 55.152 0.192 55.176 ;
    END
  END o2[64]
  PIN o2[65]
    DIRECTION OUTPUT ;
    USE SIGNAL ;
    PORT
      LAYER M4 ;
        RECT  0 55.44 0.192 55.464 ;
    END
  END o2[65]
  PIN o2[66]
    DIRECTION OUTPUT ;
    USE SIGNAL ;
    PORT
      LAYER M4 ;
        RECT  0 55.68 0.192 55.704 ;
    END
  END o2[66]
  PIN o2[67]
    DIRECTION OUTPUT ;
    USE SIGNAL ;
    PORT
      LAYER M4 ;
        RECT  0 55.92 0.192 55.944 ;
    END
  END o2[67]
  PIN o2[68]
    DIRECTION OUTPUT ;
    USE SIGNAL ;
    PORT
      LAYER M4 ;
        RECT  0 56.4 0.192 56.424 ;
    END
  END o2[68]
  PIN o2[69]
    DIRECTION OUTPUT ;
    USE SIGNAL ;
    PORT
      LAYER M4 ;
        RECT  0 56.688 0.192 56.712 ;
    END
  END o2[69]
  PIN o2[6]
    DIRECTION OUTPUT ;
    USE SIGNAL ;
    PORT
      LAYER M4 ;
        RECT  0 40.608 0.192 40.632 ;
    END
  END o2[6]
  PIN o2[70]
    DIRECTION OUTPUT ;
    USE SIGNAL ;
    PORT
      LAYER M4 ;
        RECT  0 56.928 0.192 56.952 ;
    END
  END o2[70]
  PIN o2[71]
    DIRECTION OUTPUT ;
    USE SIGNAL ;
    PORT
      LAYER M4 ;
        RECT  0 57.168 0.192 57.192 ;
    END
  END o2[71]
  PIN o2[72]
    DIRECTION OUTPUT ;
    USE SIGNAL ;
    PORT
      LAYER M4 ;
        RECT  0 57.408 0.192 57.432 ;
    END
  END o2[72]
  PIN o2[73]
    DIRECTION OUTPUT ;
    USE SIGNAL ;
    PORT
      LAYER M4 ;
        RECT  0 57.696 0.192 57.72 ;
    END
  END o2[73]
  PIN o2[74]
    DIRECTION OUTPUT ;
    USE SIGNAL ;
    PORT
      LAYER M4 ;
        RECT  0 57.936 0.192 57.96 ;
    END
  END o2[74]
  PIN o2[75]
    DIRECTION OUTPUT ;
    USE SIGNAL ;
    PORT
      LAYER M4 ;
        RECT  0 58.176 0.192 58.2 ;
    END
  END o2[75]
  PIN o2[76]
    DIRECTION OUTPUT ;
    USE SIGNAL ;
    PORT
      LAYER M4 ;
        RECT  0 58.416 0.192 58.44 ;
    END
  END o2[76]
  PIN o2[77]
    DIRECTION OUTPUT ;
    USE SIGNAL ;
    PORT
      LAYER M4 ;
        RECT  0 58.704 0.192 58.728 ;
    END
  END o2[77]
  PIN o2[78]
    DIRECTION OUTPUT ;
    USE SIGNAL ;
    PORT
      LAYER M4 ;
        RECT  0 58.944 0.192 58.968 ;
    END
  END o2[78]
  PIN o2[79]
    DIRECTION OUTPUT ;
    USE SIGNAL ;
    PORT
      LAYER M4 ;
        RECT  0 59.184 0.192 59.208 ;
    END
  END o2[79]
  PIN o2[7]
    DIRECTION OUTPUT ;
    USE SIGNAL ;
    PORT
      LAYER M4 ;
        RECT  0 40.848 0.192 40.872 ;
    END
  END o2[7]
  PIN o2[80]
    DIRECTION OUTPUT ;
    USE SIGNAL ;
    PORT
      LAYER M4 ;
        RECT  0 59.424 0.192 59.448 ;
    END
  END o2[80]
  PIN o2[81]
    DIRECTION OUTPUT ;
    USE SIGNAL ;
    PORT
      LAYER M4 ;
        RECT  0 59.712 0.192 59.736 ;
    END
  END o2[81]
  PIN o2[82]
    DIRECTION OUTPUT ;
    USE SIGNAL ;
    PORT
      LAYER M4 ;
        RECT  0 59.952 0.192 59.976 ;
    END
  END o2[82]
  PIN o2[83]
    DIRECTION OUTPUT ;
    USE SIGNAL ;
    PORT
      LAYER M4 ;
        RECT  0 60.192 0.192 60.216 ;
    END
  END o2[83]
  PIN o2[84]
    DIRECTION OUTPUT ;
    USE SIGNAL ;
    PORT
      LAYER M4 ;
        RECT  0 60.432 0.192 60.456 ;
    END
  END o2[84]
  PIN o2[85]
    DIRECTION OUTPUT ;
    USE SIGNAL ;
    PORT
      LAYER M4 ;
        RECT  0 60.672 0.192 60.696 ;
    END
  END o2[85]
  PIN o2[86]
    DIRECTION OUTPUT ;
    USE SIGNAL ;
    PORT
      LAYER M4 ;
        RECT  0 60.96 0.192 60.984 ;
    END
  END o2[86]
  PIN o2[87]
    DIRECTION OUTPUT ;
    USE SIGNAL ;
    PORT
      LAYER M4 ;
        RECT  0 61.2 0.192 61.224 ;
    END
  END o2[87]
  PIN o2[88]
    DIRECTION OUTPUT ;
    USE SIGNAL ;
    PORT
      LAYER M4 ;
        RECT  0 61.44 0.192 61.464 ;
    END
  END o2[88]
  PIN o2[89]
    DIRECTION OUTPUT ;
    USE SIGNAL ;
    PORT
      LAYER M4 ;
        RECT  0 61.68 0.192 61.704 ;
    END
  END o2[89]
  PIN o2[8]
    DIRECTION OUTPUT ;
    USE SIGNAL ;
    PORT
      LAYER M4 ;
        RECT  0 41.088 0.192 41.112 ;
    END
  END o2[8]
  PIN o2[90]
    DIRECTION OUTPUT ;
    USE SIGNAL ;
    PORT
      LAYER M4 ;
        RECT  0 61.968 0.192 61.992 ;
    END
  END o2[90]
  PIN o2[91]
    DIRECTION OUTPUT ;
    USE SIGNAL ;
    PORT
      LAYER M4 ;
        RECT  0 62.208 0.192 62.232 ;
    END
  END o2[91]
  PIN o2[92]
    DIRECTION OUTPUT ;
    USE SIGNAL ;
    PORT
      LAYER M4 ;
        RECT  0 62.448 0.192 62.472 ;
    END
  END o2[92]
  PIN o2[93]
    DIRECTION OUTPUT ;
    USE SIGNAL ;
    PORT
      LAYER M4 ;
        RECT  0 62.688 0.192 62.712 ;
    END
  END o2[93]
  PIN o2[94]
    DIRECTION OUTPUT ;
    USE SIGNAL ;
    PORT
      LAYER M4 ;
        RECT  0 62.976 0.192 63 ;
    END
  END o2[94]
  PIN o2[95]
    DIRECTION OUTPUT ;
    USE SIGNAL ;
    PORT
      LAYER M4 ;
        RECT  0 63.216 0.192 63.24 ;
    END
  END o2[95]
  PIN o2[96]
    DIRECTION OUTPUT ;
    USE SIGNAL ;
    PORT
      LAYER M4 ;
        RECT  0 63.456 0.192 63.48 ;
    END
  END o2[96]
  PIN o2[97]
    DIRECTION OUTPUT ;
    USE SIGNAL ;
    PORT
      LAYER M4 ;
        RECT  0 63.696 0.192 63.72 ;
    END
  END o2[97]
  PIN o2[98]
    DIRECTION OUTPUT ;
    USE SIGNAL ;
    PORT
      LAYER M4 ;
        RECT  0 63.936 0.192 63.96 ;
    END
  END o2[98]
  PIN o2[99]
    DIRECTION OUTPUT ;
    USE SIGNAL ;
    PORT
      LAYER M4 ;
        RECT  0 64.224 0.192 64.248 ;
    END
  END o2[99]
  PIN o2[9]
    DIRECTION OUTPUT ;
    USE SIGNAL ;
    PORT
      LAYER M4 ;
        RECT  0 41.376 0.192 41.4 ;
    END
  END o2[9]
  PIN o3[0]
    DIRECTION OUTPUT ;
    USE SIGNAL ;
    PORT
      LAYER M4 ;
        RECT  21.408 50.592 21.6 50.616 ;
    END
  END o3[0]
  PIN o3[100]
    DIRECTION OUTPUT ;
    USE SIGNAL ;
    PORT
      LAYER M4 ;
        RECT  21.408 67.44 21.6 67.464 ;
    END
  END o3[100]
  PIN o3[101]
    DIRECTION OUTPUT ;
    USE SIGNAL ;
    PORT
      LAYER M4 ;
        RECT  21.408 67.584 21.6 67.608 ;
    END
  END o3[101]
  PIN o3[102]
    DIRECTION OUTPUT ;
    USE SIGNAL ;
    PORT
      LAYER M4 ;
        RECT  21.408 67.776 21.6 67.8 ;
    END
  END o3[102]
  PIN o3[103]
    DIRECTION OUTPUT ;
    USE SIGNAL ;
    PORT
      LAYER M4 ;
        RECT  21.408 67.92 21.6 67.944 ;
    END
  END o3[103]
  PIN o3[104]
    DIRECTION OUTPUT ;
    USE SIGNAL ;
    PORT
      LAYER M4 ;
        RECT  21.408 68.112 21.6 68.136 ;
    END
  END o3[104]
  PIN o3[105]
    DIRECTION OUTPUT ;
    USE SIGNAL ;
    PORT
      LAYER M4 ;
        RECT  21.408 68.256 21.6 68.28 ;
    END
  END o3[105]
  PIN o3[106]
    DIRECTION OUTPUT ;
    USE SIGNAL ;
    PORT
      LAYER M4 ;
        RECT  21.408 68.448 21.6 68.472 ;
    END
  END o3[106]
  PIN o3[107]
    DIRECTION OUTPUT ;
    USE SIGNAL ;
    PORT
      LAYER M4 ;
        RECT  21.408 68.592 21.6 68.616 ;
    END
  END o3[107]
  PIN o3[108]
    DIRECTION OUTPUT ;
    USE SIGNAL ;
    PORT
      LAYER M4 ;
        RECT  21.408 68.736 21.6 68.76 ;
    END
  END o3[108]
  PIN o3[109]
    DIRECTION OUTPUT ;
    USE SIGNAL ;
    PORT
      LAYER M4 ;
        RECT  21.408 68.928 21.6 68.952 ;
    END
  END o3[109]
  PIN o3[10]
    DIRECTION OUTPUT ;
    USE SIGNAL ;
    PORT
      LAYER M4 ;
        RECT  21.408 52.272 21.6 52.296 ;
    END
  END o3[10]
  PIN o3[110]
    DIRECTION OUTPUT ;
    USE SIGNAL ;
    PORT
      LAYER M4 ;
        RECT  21.408 69.072 21.6 69.096 ;
    END
  END o3[110]
  PIN o3[111]
    DIRECTION OUTPUT ;
    USE SIGNAL ;
    PORT
      LAYER M4 ;
        RECT  21.408 69.264 21.6 69.288 ;
    END
  END o3[111]
  PIN o3[112]
    DIRECTION OUTPUT ;
    USE SIGNAL ;
    PORT
      LAYER M4 ;
        RECT  21.408 69.408 21.6 69.432 ;
    END
  END o3[112]
  PIN o3[113]
    DIRECTION OUTPUT ;
    USE SIGNAL ;
    PORT
      LAYER M4 ;
        RECT  21.408 69.6 21.6 69.624 ;
    END
  END o3[113]
  PIN o3[114]
    DIRECTION OUTPUT ;
    USE SIGNAL ;
    PORT
      LAYER M4 ;
        RECT  21.408 69.744 21.6 69.768 ;
    END
  END o3[114]
  PIN o3[115]
    DIRECTION OUTPUT ;
    USE SIGNAL ;
    PORT
      LAYER M4 ;
        RECT  21.408 69.936 21.6 69.96 ;
    END
  END o3[115]
  PIN o3[116]
    DIRECTION OUTPUT ;
    USE SIGNAL ;
    PORT
      LAYER M4 ;
        RECT  21.408 70.08 21.6 70.104 ;
    END
  END o3[116]
  PIN o3[117]
    DIRECTION OUTPUT ;
    USE SIGNAL ;
    PORT
      LAYER M4 ;
        RECT  21.408 70.272 21.6 70.296 ;
    END
  END o3[117]
  PIN o3[118]
    DIRECTION OUTPUT ;
    USE SIGNAL ;
    PORT
      LAYER M4 ;
        RECT  21.408 70.416 21.6 70.44 ;
    END
  END o3[118]
  PIN o3[119]
    DIRECTION OUTPUT ;
    USE SIGNAL ;
    PORT
      LAYER M4 ;
        RECT  21.408 70.608 21.6 70.632 ;
    END
  END o3[119]
  PIN o3[11]
    DIRECTION OUTPUT ;
    USE SIGNAL ;
    PORT
      LAYER M4 ;
        RECT  21.408 52.464 21.6 52.488 ;
    END
  END o3[11]
  PIN o3[120]
    DIRECTION OUTPUT ;
    USE SIGNAL ;
    PORT
      LAYER M4 ;
        RECT  21.408 70.752 21.6 70.776 ;
    END
  END o3[120]
  PIN o3[121]
    DIRECTION OUTPUT ;
    USE SIGNAL ;
    PORT
      LAYER M4 ;
        RECT  21.408 70.944 21.6 70.968 ;
    END
  END o3[121]
  PIN o3[122]
    DIRECTION OUTPUT ;
    USE SIGNAL ;
    PORT
      LAYER M4 ;
        RECT  21.408 71.088 21.6 71.112 ;
    END
  END o3[122]
  PIN o3[123]
    DIRECTION OUTPUT ;
    USE SIGNAL ;
    PORT
      LAYER M4 ;
        RECT  21.408 71.232 21.6 71.256 ;
    END
  END o3[123]
  PIN o3[124]
    DIRECTION OUTPUT ;
    USE SIGNAL ;
    PORT
      LAYER M4 ;
        RECT  21.408 71.424 21.6 71.448 ;
    END
  END o3[124]
  PIN o3[125]
    DIRECTION OUTPUT ;
    USE SIGNAL ;
    PORT
      LAYER M4 ;
        RECT  21.408 71.568 21.6 71.592 ;
    END
  END o3[125]
  PIN o3[126]
    DIRECTION OUTPUT ;
    USE SIGNAL ;
    PORT
      LAYER M4 ;
        RECT  21.408 71.76 21.6 71.784 ;
    END
  END o3[126]
  PIN o3[127]
    DIRECTION OUTPUT ;
    USE SIGNAL ;
    PORT
      LAYER M4 ;
        RECT  21.408 71.904 21.6 71.928 ;
    END
  END o3[127]
  PIN o3[128]
    DIRECTION OUTPUT ;
    USE SIGNAL ;
    PORT
      LAYER M4 ;
        RECT  21.408 72.096 21.6 72.12 ;
    END
  END o3[128]
  PIN o3[129]
    DIRECTION OUTPUT ;
    USE SIGNAL ;
    PORT
      LAYER M4 ;
        RECT  21.408 72.24 21.6 72.264 ;
    END
  END o3[129]
  PIN o3[12]
    DIRECTION OUTPUT ;
    USE SIGNAL ;
    PORT
      LAYER M4 ;
        RECT  21.408 52.608 21.6 52.632 ;
    END
  END o3[12]
  PIN o3[130]
    DIRECTION OUTPUT ;
    USE SIGNAL ;
    PORT
      LAYER M4 ;
        RECT  21.408 72.432 21.6 72.456 ;
    END
  END o3[130]
  PIN o3[131]
    DIRECTION OUTPUT ;
    USE SIGNAL ;
    PORT
      LAYER M4 ;
        RECT  21.408 72.576 21.6 72.6 ;
    END
  END o3[131]
  PIN o3[132]
    DIRECTION OUTPUT ;
    USE SIGNAL ;
    PORT
      LAYER M4 ;
        RECT  21.408 72.768 21.6 72.792 ;
    END
  END o3[132]
  PIN o3[133]
    DIRECTION OUTPUT ;
    USE SIGNAL ;
    PORT
      LAYER M4 ;
        RECT  21.408 72.912 21.6 72.936 ;
    END
  END o3[133]
  PIN o3[134]
    DIRECTION OUTPUT ;
    USE SIGNAL ;
    PORT
      LAYER M4 ;
        RECT  21.408 73.104 21.6 73.128 ;
    END
  END o3[134]
  PIN o3[135]
    DIRECTION OUTPUT ;
    USE SIGNAL ;
    PORT
      LAYER M4 ;
        RECT  21.408 73.248 21.6 73.272 ;
    END
  END o3[135]
  PIN o3[13]
    DIRECTION OUTPUT ;
    USE SIGNAL ;
    PORT
      LAYER M4 ;
        RECT  21.408 52.8 21.6 52.824 ;
    END
  END o3[13]
  PIN o3[14]
    DIRECTION OUTPUT ;
    USE SIGNAL ;
    PORT
      LAYER M4 ;
        RECT  21.408 52.944 21.6 52.968 ;
    END
  END o3[14]
  PIN o3[15]
    DIRECTION OUTPUT ;
    USE SIGNAL ;
    PORT
      LAYER M4 ;
        RECT  21.408 53.088 21.6 53.112 ;
    END
  END o3[15]
  PIN o3[16]
    DIRECTION OUTPUT ;
    USE SIGNAL ;
    PORT
      LAYER M4 ;
        RECT  21.408 53.28 21.6 53.304 ;
    END
  END o3[16]
  PIN o3[17]
    DIRECTION OUTPUT ;
    USE SIGNAL ;
    PORT
      LAYER M4 ;
        RECT  21.408 53.424 21.6 53.448 ;
    END
  END o3[17]
  PIN o3[18]
    DIRECTION OUTPUT ;
    USE SIGNAL ;
    PORT
      LAYER M4 ;
        RECT  21.408 53.616 21.6 53.64 ;
    END
  END o3[18]
  PIN o3[19]
    DIRECTION OUTPUT ;
    USE SIGNAL ;
    PORT
      LAYER M4 ;
        RECT  21.408 53.76 21.6 53.784 ;
    END
  END o3[19]
  PIN o3[1]
    DIRECTION OUTPUT ;
    USE SIGNAL ;
    PORT
      LAYER M4 ;
        RECT  21.408 50.784 21.6 50.808 ;
    END
  END o3[1]
  PIN o3[20]
    DIRECTION OUTPUT ;
    USE SIGNAL ;
    PORT
      LAYER M4 ;
        RECT  21.408 53.952 21.6 53.976 ;
    END
  END o3[20]
  PIN o3[21]
    DIRECTION OUTPUT ;
    USE SIGNAL ;
    PORT
      LAYER M4 ;
        RECT  21.408 54.096 21.6 54.12 ;
    END
  END o3[21]
  PIN o3[22]
    DIRECTION OUTPUT ;
    USE SIGNAL ;
    PORT
      LAYER M4 ;
        RECT  21.408 54.288 21.6 54.312 ;
    END
  END o3[22]
  PIN o3[23]
    DIRECTION OUTPUT ;
    USE SIGNAL ;
    PORT
      LAYER M4 ;
        RECT  21.408 54.432 21.6 54.456 ;
    END
  END o3[23]
  PIN o3[24]
    DIRECTION OUTPUT ;
    USE SIGNAL ;
    PORT
      LAYER M4 ;
        RECT  21.408 54.624 21.6 54.648 ;
    END
  END o3[24]
  PIN o3[25]
    DIRECTION OUTPUT ;
    USE SIGNAL ;
    PORT
      LAYER M4 ;
        RECT  21.408 54.768 21.6 54.792 ;
    END
  END o3[25]
  PIN o3[26]
    DIRECTION OUTPUT ;
    USE SIGNAL ;
    PORT
      LAYER M4 ;
        RECT  21.408 54.96 21.6 54.984 ;
    END
  END o3[26]
  PIN o3[27]
    DIRECTION OUTPUT ;
    USE SIGNAL ;
    PORT
      LAYER M4 ;
        RECT  21.408 55.104 21.6 55.128 ;
    END
  END o3[27]
  PIN o3[28]
    DIRECTION OUTPUT ;
    USE SIGNAL ;
    PORT
      LAYER M4 ;
        RECT  21.408 55.296 21.6 55.32 ;
    END
  END o3[28]
  PIN o3[29]
    DIRECTION OUTPUT ;
    USE SIGNAL ;
    PORT
      LAYER M4 ;
        RECT  21.408 55.44 21.6 55.464 ;
    END
  END o3[29]
  PIN o3[2]
    DIRECTION OUTPUT ;
    USE SIGNAL ;
    PORT
      LAYER M4 ;
        RECT  21.408 50.928 21.6 50.952 ;
    END
  END o3[2]
  PIN o3[30]
    DIRECTION OUTPUT ;
    USE SIGNAL ;
    PORT
      LAYER M4 ;
        RECT  21.408 55.584 21.6 55.608 ;
    END
  END o3[30]
  PIN o3[31]
    DIRECTION OUTPUT ;
    USE SIGNAL ;
    PORT
      LAYER M4 ;
        RECT  21.408 55.776 21.6 55.8 ;
    END
  END o3[31]
  PIN o3[32]
    DIRECTION OUTPUT ;
    USE SIGNAL ;
    PORT
      LAYER M4 ;
        RECT  21.408 55.92 21.6 55.944 ;
    END
  END o3[32]
  PIN o3[33]
    DIRECTION OUTPUT ;
    USE SIGNAL ;
    PORT
      LAYER M4 ;
        RECT  21.408 56.112 21.6 56.136 ;
    END
  END o3[33]
  PIN o3[34]
    DIRECTION OUTPUT ;
    USE SIGNAL ;
    PORT
      LAYER M4 ;
        RECT  21.408 56.256 21.6 56.28 ;
    END
  END o3[34]
  PIN o3[35]
    DIRECTION OUTPUT ;
    USE SIGNAL ;
    PORT
      LAYER M4 ;
        RECT  21.408 56.448 21.6 56.472 ;
    END
  END o3[35]
  PIN o3[36]
    DIRECTION OUTPUT ;
    USE SIGNAL ;
    PORT
      LAYER M4 ;
        RECT  21.408 56.592 21.6 56.616 ;
    END
  END o3[36]
  PIN o3[37]
    DIRECTION OUTPUT ;
    USE SIGNAL ;
    PORT
      LAYER M4 ;
        RECT  21.408 56.784 21.6 56.808 ;
    END
  END o3[37]
  PIN o3[38]
    DIRECTION OUTPUT ;
    USE SIGNAL ;
    PORT
      LAYER M4 ;
        RECT  21.408 56.928 21.6 56.952 ;
    END
  END o3[38]
  PIN o3[39]
    DIRECTION OUTPUT ;
    USE SIGNAL ;
    PORT
      LAYER M4 ;
        RECT  21.408 57.12 21.6 57.144 ;
    END
  END o3[39]
  PIN o3[3]
    DIRECTION OUTPUT ;
    USE SIGNAL ;
    PORT
      LAYER M4 ;
        RECT  21.408 51.12 21.6 51.144 ;
    END
  END o3[3]
  PIN o3[40]
    DIRECTION OUTPUT ;
    USE SIGNAL ;
    PORT
      LAYER M4 ;
        RECT  21.408 57.264 21.6 57.288 ;
    END
  END o3[40]
  PIN o3[41]
    DIRECTION OUTPUT ;
    USE SIGNAL ;
    PORT
      LAYER M4 ;
        RECT  21.408 57.456 21.6 57.48 ;
    END
  END o3[41]
  PIN o3[42]
    DIRECTION OUTPUT ;
    USE SIGNAL ;
    PORT
      LAYER M4 ;
        RECT  21.408 57.6 21.6 57.624 ;
    END
  END o3[42]
  PIN o3[43]
    DIRECTION OUTPUT ;
    USE SIGNAL ;
    PORT
      LAYER M4 ;
        RECT  21.408 57.792 21.6 57.816 ;
    END
  END o3[43]
  PIN o3[44]
    DIRECTION OUTPUT ;
    USE SIGNAL ;
    PORT
      LAYER M4 ;
        RECT  21.408 57.936 21.6 57.96 ;
    END
  END o3[44]
  PIN o3[45]
    DIRECTION OUTPUT ;
    USE SIGNAL ;
    PORT
      LAYER M4 ;
        RECT  21.408 58.08 21.6 58.104 ;
    END
  END o3[45]
  PIN o3[46]
    DIRECTION OUTPUT ;
    USE SIGNAL ;
    PORT
      LAYER M4 ;
        RECT  21.408 58.272 21.6 58.296 ;
    END
  END o3[46]
  PIN o3[47]
    DIRECTION OUTPUT ;
    USE SIGNAL ;
    PORT
      LAYER M4 ;
        RECT  21.408 58.416 21.6 58.44 ;
    END
  END o3[47]
  PIN o3[48]
    DIRECTION OUTPUT ;
    USE SIGNAL ;
    PORT
      LAYER M4 ;
        RECT  21.408 58.608 21.6 58.632 ;
    END
  END o3[48]
  PIN o3[49]
    DIRECTION OUTPUT ;
    USE SIGNAL ;
    PORT
      LAYER M4 ;
        RECT  21.408 58.752 21.6 58.776 ;
    END
  END o3[49]
  PIN o3[4]
    DIRECTION OUTPUT ;
    USE SIGNAL ;
    PORT
      LAYER M4 ;
        RECT  21.408 51.264 21.6 51.288 ;
    END
  END o3[4]
  PIN o3[50]
    DIRECTION OUTPUT ;
    USE SIGNAL ;
    PORT
      LAYER M4 ;
        RECT  21.408 58.944 21.6 58.968 ;
    END
  END o3[50]
  PIN o3[51]
    DIRECTION OUTPUT ;
    USE SIGNAL ;
    PORT
      LAYER M4 ;
        RECT  21.408 59.088 21.6 59.112 ;
    END
  END o3[51]
  PIN o3[52]
    DIRECTION OUTPUT ;
    USE SIGNAL ;
    PORT
      LAYER M4 ;
        RECT  21.408 59.28 21.6 59.304 ;
    END
  END o3[52]
  PIN o3[53]
    DIRECTION OUTPUT ;
    USE SIGNAL ;
    PORT
      LAYER M4 ;
        RECT  21.408 59.424 21.6 59.448 ;
    END
  END o3[53]
  PIN o3[54]
    DIRECTION OUTPUT ;
    USE SIGNAL ;
    PORT
      LAYER M4 ;
        RECT  21.408 59.616 21.6 59.64 ;
    END
  END o3[54]
  PIN o3[55]
    DIRECTION OUTPUT ;
    USE SIGNAL ;
    PORT
      LAYER M4 ;
        RECT  21.408 59.76 21.6 59.784 ;
    END
  END o3[55]
  PIN o3[56]
    DIRECTION OUTPUT ;
    USE SIGNAL ;
    PORT
      LAYER M4 ;
        RECT  21.408 59.952 21.6 59.976 ;
    END
  END o3[56]
  PIN o3[57]
    DIRECTION OUTPUT ;
    USE SIGNAL ;
    PORT
      LAYER M4 ;
        RECT  21.408 60.096 21.6 60.12 ;
    END
  END o3[57]
  PIN o3[58]
    DIRECTION OUTPUT ;
    USE SIGNAL ;
    PORT
      LAYER M4 ;
        RECT  21.408 60.288 21.6 60.312 ;
    END
  END o3[58]
  PIN o3[59]
    DIRECTION OUTPUT ;
    USE SIGNAL ;
    PORT
      LAYER M4 ;
        RECT  21.408 60.432 21.6 60.456 ;
    END
  END o3[59]
  PIN o3[5]
    DIRECTION OUTPUT ;
    USE SIGNAL ;
    PORT
      LAYER M4 ;
        RECT  21.408 51.456 21.6 51.48 ;
    END
  END o3[5]
  PIN o3[60]
    DIRECTION OUTPUT ;
    USE SIGNAL ;
    PORT
      LAYER M4 ;
        RECT  21.408 60.624 21.6 60.648 ;
    END
  END o3[60]
  PIN o3[61]
    DIRECTION OUTPUT ;
    USE SIGNAL ;
    PORT
      LAYER M4 ;
        RECT  21.408 60.768 21.6 60.792 ;
    END
  END o3[61]
  PIN o3[62]
    DIRECTION OUTPUT ;
    USE SIGNAL ;
    PORT
      LAYER M4 ;
        RECT  21.408 60.912 21.6 60.936 ;
    END
  END o3[62]
  PIN o3[63]
    DIRECTION OUTPUT ;
    USE SIGNAL ;
    PORT
      LAYER M4 ;
        RECT  21.408 61.104 21.6 61.128 ;
    END
  END o3[63]
  PIN o3[64]
    DIRECTION OUTPUT ;
    USE SIGNAL ;
    PORT
      LAYER M4 ;
        RECT  21.408 61.248 21.6 61.272 ;
    END
  END o3[64]
  PIN o3[65]
    DIRECTION OUTPUT ;
    USE SIGNAL ;
    PORT
      LAYER M4 ;
        RECT  21.408 61.44 21.6 61.464 ;
    END
  END o3[65]
  PIN o3[66]
    DIRECTION OUTPUT ;
    USE SIGNAL ;
    PORT
      LAYER M4 ;
        RECT  21.408 61.584 21.6 61.608 ;
    END
  END o3[66]
  PIN o3[67]
    DIRECTION OUTPUT ;
    USE SIGNAL ;
    PORT
      LAYER M4 ;
        RECT  21.408 61.776 21.6 61.8 ;
    END
  END o3[67]
  PIN o3[68]
    DIRECTION OUTPUT ;
    USE SIGNAL ;
    PORT
      LAYER M4 ;
        RECT  21.408 62.112 21.6 62.136 ;
    END
  END o3[68]
  PIN o3[69]
    DIRECTION OUTPUT ;
    USE SIGNAL ;
    PORT
      LAYER M4 ;
        RECT  21.408 62.256 21.6 62.28 ;
    END
  END o3[69]
  PIN o3[6]
    DIRECTION OUTPUT ;
    USE SIGNAL ;
    PORT
      LAYER M4 ;
        RECT  21.408 51.6 21.6 51.624 ;
    END
  END o3[6]
  PIN o3[70]
    DIRECTION OUTPUT ;
    USE SIGNAL ;
    PORT
      LAYER M4 ;
        RECT  21.408 62.448 21.6 62.472 ;
    END
  END o3[70]
  PIN o3[71]
    DIRECTION OUTPUT ;
    USE SIGNAL ;
    PORT
      LAYER M4 ;
        RECT  21.408 62.592 21.6 62.616 ;
    END
  END o3[71]
  PIN o3[72]
    DIRECTION OUTPUT ;
    USE SIGNAL ;
    PORT
      LAYER M4 ;
        RECT  21.408 62.784 21.6 62.808 ;
    END
  END o3[72]
  PIN o3[73]
    DIRECTION OUTPUT ;
    USE SIGNAL ;
    PORT
      LAYER M4 ;
        RECT  21.408 62.928 21.6 62.952 ;
    END
  END o3[73]
  PIN o3[74]
    DIRECTION OUTPUT ;
    USE SIGNAL ;
    PORT
      LAYER M4 ;
        RECT  21.408 63.12 21.6 63.144 ;
    END
  END o3[74]
  PIN o3[75]
    DIRECTION OUTPUT ;
    USE SIGNAL ;
    PORT
      LAYER M4 ;
        RECT  21.408 63.264 21.6 63.288 ;
    END
  END o3[75]
  PIN o3[76]
    DIRECTION OUTPUT ;
    USE SIGNAL ;
    PORT
      LAYER M4 ;
        RECT  21.408 63.408 21.6 63.432 ;
    END
  END o3[76]
  PIN o3[77]
    DIRECTION OUTPUT ;
    USE SIGNAL ;
    PORT
      LAYER M4 ;
        RECT  21.408 63.6 21.6 63.624 ;
    END
  END o3[77]
  PIN o3[78]
    DIRECTION OUTPUT ;
    USE SIGNAL ;
    PORT
      LAYER M4 ;
        RECT  21.408 63.744 21.6 63.768 ;
    END
  END o3[78]
  PIN o3[79]
    DIRECTION OUTPUT ;
    USE SIGNAL ;
    PORT
      LAYER M4 ;
        RECT  21.408 63.936 21.6 63.96 ;
    END
  END o3[79]
  PIN o3[7]
    DIRECTION OUTPUT ;
    USE SIGNAL ;
    PORT
      LAYER M4 ;
        RECT  21.408 51.792 21.6 51.816 ;
    END
  END o3[7]
  PIN o3[80]
    DIRECTION OUTPUT ;
    USE SIGNAL ;
    PORT
      LAYER M4 ;
        RECT  21.408 64.08 21.6 64.104 ;
    END
  END o3[80]
  PIN o3[81]
    DIRECTION OUTPUT ;
    USE SIGNAL ;
    PORT
      LAYER M4 ;
        RECT  21.408 64.272 21.6 64.296 ;
    END
  END o3[81]
  PIN o3[82]
    DIRECTION OUTPUT ;
    USE SIGNAL ;
    PORT
      LAYER M4 ;
        RECT  21.408 64.416 21.6 64.44 ;
    END
  END o3[82]
  PIN o3[83]
    DIRECTION OUTPUT ;
    USE SIGNAL ;
    PORT
      LAYER M4 ;
        RECT  21.408 64.608 21.6 64.632 ;
    END
  END o3[83]
  PIN o3[84]
    DIRECTION OUTPUT ;
    USE SIGNAL ;
    PORT
      LAYER M4 ;
        RECT  21.408 64.752 21.6 64.776 ;
    END
  END o3[84]
  PIN o3[85]
    DIRECTION OUTPUT ;
    USE SIGNAL ;
    PORT
      LAYER M4 ;
        RECT  21.408 64.944 21.6 64.968 ;
    END
  END o3[85]
  PIN o3[86]
    DIRECTION OUTPUT ;
    USE SIGNAL ;
    PORT
      LAYER M4 ;
        RECT  21.408 65.088 21.6 65.112 ;
    END
  END o3[86]
  PIN o3[87]
    DIRECTION OUTPUT ;
    USE SIGNAL ;
    PORT
      LAYER M4 ;
        RECT  21.408 65.28 21.6 65.304 ;
    END
  END o3[87]
  PIN o3[88]
    DIRECTION OUTPUT ;
    USE SIGNAL ;
    PORT
      LAYER M4 ;
        RECT  21.408 65.424 21.6 65.448 ;
    END
  END o3[88]
  PIN o3[89]
    DIRECTION OUTPUT ;
    USE SIGNAL ;
    PORT
      LAYER M4 ;
        RECT  21.408 65.616 21.6 65.64 ;
    END
  END o3[89]
  PIN o3[8]
    DIRECTION OUTPUT ;
    USE SIGNAL ;
    PORT
      LAYER M4 ;
        RECT  21.408 51.936 21.6 51.96 ;
    END
  END o3[8]
  PIN o3[90]
    DIRECTION OUTPUT ;
    USE SIGNAL ;
    PORT
      LAYER M4 ;
        RECT  21.408 65.76 21.6 65.784 ;
    END
  END o3[90]
  PIN o3[91]
    DIRECTION OUTPUT ;
    USE SIGNAL ;
    PORT
      LAYER M4 ;
        RECT  21.408 65.904 21.6 65.928 ;
    END
  END o3[91]
  PIN o3[92]
    DIRECTION OUTPUT ;
    USE SIGNAL ;
    PORT
      LAYER M4 ;
        RECT  21.408 66.096 21.6 66.12 ;
    END
  END o3[92]
  PIN o3[93]
    DIRECTION OUTPUT ;
    USE SIGNAL ;
    PORT
      LAYER M4 ;
        RECT  21.408 66.24 21.6 66.264 ;
    END
  END o3[93]
  PIN o3[94]
    DIRECTION OUTPUT ;
    USE SIGNAL ;
    PORT
      LAYER M4 ;
        RECT  21.408 66.432 21.6 66.456 ;
    END
  END o3[94]
  PIN o3[95]
    DIRECTION OUTPUT ;
    USE SIGNAL ;
    PORT
      LAYER M4 ;
        RECT  21.408 66.576 21.6 66.6 ;
    END
  END o3[95]
  PIN o3[96]
    DIRECTION OUTPUT ;
    USE SIGNAL ;
    PORT
      LAYER M4 ;
        RECT  21.408 66.768 21.6 66.792 ;
    END
  END o3[96]
  PIN o3[97]
    DIRECTION OUTPUT ;
    USE SIGNAL ;
    PORT
      LAYER M4 ;
        RECT  21.408 66.912 21.6 66.936 ;
    END
  END o3[97]
  PIN o3[98]
    DIRECTION OUTPUT ;
    USE SIGNAL ;
    PORT
      LAYER M4 ;
        RECT  21.408 67.104 21.6 67.128 ;
    END
  END o3[98]
  PIN o3[99]
    DIRECTION OUTPUT ;
    USE SIGNAL ;
    PORT
      LAYER M4 ;
        RECT  21.408 67.248 21.6 67.272 ;
    END
  END o3[99]
  PIN o3[9]
    DIRECTION OUTPUT ;
    USE SIGNAL ;
    PORT
      LAYER M4 ;
        RECT  21.408 52.128 21.6 52.152 ;
    END
  END o3[9]
  PIN rs
    DIRECTION INPUT ;
    USE SIGNAL ;
    PORT
      LAYER M5 ;
        RECT  10.8 0 10.824 0.192 ;
    END
  END rs
  PIN VDD
    DIRECTION INOUT ;
    USE POWER ;
    PORT
      LAYER M5 ;
        RECT  18.792 2.151 18.912 75.609 ;
        RECT  16.092 2.151 16.212 75.609 ;
        RECT  13.392 2.151 13.512 75.609 ;
        RECT  10.692 2.151 10.812 75.609 ;
        RECT  7.992 2.151 8.112 75.609 ;
        RECT  5.292 2.151 5.412 75.609 ;
        RECT  2.592 2.151 2.712 75.609 ;
    END
  END VDD
  PIN VSS
    DIRECTION INOUT ;
    USE GROUND ;
    PORT
      LAYER M5 ;
        RECT  18.6 2.137 18.72 75.623 ;
        RECT  15.9 2.137 16.02 75.623 ;
        RECT  13.2 2.137 13.32 75.623 ;
        RECT  10.5 2.137 10.62 75.623 ;
        RECT  7.8 2.137 7.92 75.623 ;
        RECT  5.1 2.137 5.22 75.623 ;
        RECT  2.4 2.137 2.52 75.623 ;
    END
  END VSS
  OBS
    LAYER RVTN ;
     RECT  2.16 2.16 19.44 2.295 ;
     RECT  2.16 2.565 19.44 2.835 ;
     RECT  2.16 3.105 19.44 3.375 ;
     RECT  2.16 3.645 19.44 3.915 ;
     RECT  2.16 4.185 19.44 4.455 ;
     RECT  2.16 4.725 19.44 4.995 ;
     RECT  2.16 5.265 19.44 5.535 ;
     RECT  2.16 5.805 19.44 6.075 ;
     RECT  2.16 6.345 19.44 6.615 ;
     RECT  2.16 6.885 19.44 7.155 ;
     RECT  2.16 7.425 19.44 7.695 ;
     RECT  2.16 7.965 19.44 8.235 ;
     RECT  2.16 8.505 19.44 8.775 ;
     RECT  2.16 9.045 19.44 9.315 ;
     RECT  2.16 9.585 19.44 9.855 ;
     RECT  2.16 10.125 19.44 10.395 ;
     RECT  2.16 10.665 19.44 10.935 ;
     RECT  2.16 11.205 19.44 11.475 ;
     RECT  2.16 11.745 19.44 12.015 ;
     RECT  2.16 12.285 19.44 12.555 ;
     RECT  2.16 12.825 19.44 13.095 ;
     RECT  2.16 13.365 19.44 13.635 ;
     RECT  2.16 13.905 19.44 14.175 ;
     RECT  2.16 14.445 19.44 14.715 ;
     RECT  2.16 14.985 19.44 15.255 ;
     RECT  2.16 15.525 19.44 15.795 ;
     RECT  2.16 16.065 19.44 16.335 ;
     RECT  2.16 16.605 19.44 16.875 ;
     RECT  2.16 17.145 19.44 17.415 ;
     RECT  2.16 17.685 19.44 17.955 ;
     RECT  2.16 18.225 19.44 18.495 ;
     RECT  2.16 18.765 19.44 19.035 ;
     RECT  2.16 19.305 19.44 19.575 ;
     RECT  2.16 19.845 19.44 20.115 ;
     RECT  2.16 20.385 19.44 20.655 ;
     RECT  2.16 20.925 19.44 21.195 ;
     RECT  2.16 21.465 19.44 21.735 ;
     RECT  2.16 22.005 19.44 22.275 ;
     RECT  2.16 22.545 19.44 22.815 ;
     RECT  2.16 23.085 19.44 23.355 ;
     RECT  2.16 23.625 19.44 23.895 ;
     RECT  2.16 24.165 19.44 24.435 ;
     RECT  2.16 24.705 19.44 24.975 ;
     RECT  2.16 25.245 19.44 25.515 ;
     RECT  2.16 25.785 19.44 26.055 ;
     RECT  2.16 26.325 19.44 26.595 ;
     RECT  2.16 26.865 19.44 27.135 ;
     RECT  2.16 27.405 19.44 27.675 ;
     RECT  2.16 27.945 19.44 28.215 ;
     RECT  2.16 28.485 19.44 28.755 ;
     RECT  2.16 29.025 19.44 29.295 ;
     RECT  2.16 29.565 19.44 29.835 ;
     RECT  2.16 30.105 19.44 30.375 ;
     RECT  2.16 30.645 19.44 30.915 ;
     RECT  2.16 31.185 19.44 31.455 ;
     RECT  2.16 31.725 19.44 31.995 ;
     RECT  2.16 32.265 19.44 32.535 ;
     RECT  2.16 32.805 19.44 33.075 ;
     RECT  2.16 33.345 19.44 33.615 ;
     RECT  2.16 33.885 19.44 34.155 ;
     RECT  2.16 34.425 19.44 34.695 ;
     RECT  2.16 34.965 19.44 35.235 ;
     RECT  2.16 35.505 19.44 35.775 ;
     RECT  2.16 36.045 19.44 36.315 ;
     RECT  2.16 36.585 19.44 36.855 ;
     RECT  2.16 37.125 19.44 37.395 ;
     RECT  2.16 37.665 19.44 37.935 ;
     RECT  2.16 38.205 19.44 38.475 ;
     RECT  2.16 38.745 19.44 39.015 ;
     RECT  2.16 39.285 19.44 39.555 ;
     RECT  2.16 39.825 19.44 40.095 ;
     RECT  2.16 40.365 19.44 40.635 ;
     RECT  2.16 40.905 19.44 41.175 ;
     RECT  2.16 41.445 19.44 41.715 ;
     RECT  2.16 41.985 19.44 42.255 ;
     RECT  2.16 42.525 19.44 42.795 ;
     RECT  2.16 43.065 19.44 43.335 ;
     RECT  2.16 43.605 19.44 43.875 ;
     RECT  2.16 44.145 19.44 44.415 ;
     RECT  2.16 44.685 19.44 44.955 ;
     RECT  2.16 45.225 19.44 45.495 ;
     RECT  2.16 45.765 19.44 46.035 ;
     RECT  2.16 46.305 19.44 46.575 ;
     RECT  2.16 46.845 19.44 47.115 ;
     RECT  2.16 47.385 19.44 47.655 ;
     RECT  2.16 47.925 19.44 48.195 ;
     RECT  2.16 48.465 19.44 48.735 ;
     RECT  2.16 49.005 19.44 49.275 ;
     RECT  2.16 49.545 19.44 49.815 ;
     RECT  2.16 50.085 19.44 50.355 ;
     RECT  2.16 50.625 19.44 50.895 ;
     RECT  2.16 51.165 19.44 51.435 ;
     RECT  2.16 51.705 19.44 51.975 ;
     RECT  2.16 52.245 19.44 52.515 ;
     RECT  2.16 52.785 19.44 53.055 ;
     RECT  2.16 53.325 19.44 53.595 ;
     RECT  2.16 53.865 19.44 54.135 ;
     RECT  2.16 54.405 19.44 54.675 ;
     RECT  2.16 54.945 19.44 55.215 ;
     RECT  2.16 55.485 19.44 55.755 ;
     RECT  2.16 56.025 19.44 56.295 ;
     RECT  2.16 56.565 19.44 56.835 ;
     RECT  2.16 57.105 19.44 57.375 ;
     RECT  2.16 57.645 19.44 57.915 ;
     RECT  2.16 58.185 19.44 58.455 ;
     RECT  2.16 58.725 19.44 58.995 ;
     RECT  2.16 59.265 19.44 59.535 ;
     RECT  2.16 59.805 19.44 60.075 ;
     RECT  2.16 60.345 19.44 60.615 ;
     RECT  2.16 60.885 19.44 61.155 ;
     RECT  2.16 61.425 19.44 61.695 ;
     RECT  2.16 61.965 19.44 62.235 ;
     RECT  2.16 62.505 19.44 62.775 ;
     RECT  2.16 63.045 19.44 63.315 ;
     RECT  2.16 63.585 19.44 63.855 ;
     RECT  2.16 64.125 19.44 64.395 ;
     RECT  2.16 64.665 19.44 64.935 ;
     RECT  2.16 65.205 19.44 65.475 ;
     RECT  2.16 65.745 19.44 66.015 ;
     RECT  2.16 66.285 19.44 66.555 ;
     RECT  2.16 66.825 19.44 67.095 ;
     RECT  2.16 67.365 19.44 67.635 ;
     RECT  2.16 67.905 19.44 68.175 ;
     RECT  2.16 68.445 19.44 68.715 ;
     RECT  2.16 68.985 19.44 69.255 ;
     RECT  2.16 69.525 19.44 69.795 ;
     RECT  2.16 70.065 19.44 70.335 ;
     RECT  2.16 70.605 19.44 70.875 ;
     RECT  2.16 71.145 19.44 71.415 ;
     RECT  2.16 71.685 19.44 71.955 ;
     RECT  2.16 72.225 19.44 72.495 ;
     RECT  2.16 72.765 19.44 73.035 ;
     RECT  2.16 73.305 19.44 73.575 ;
     RECT  2.16 73.845 19.44 74.115 ;
     RECT  2.16 74.385 19.44 74.655 ;
     RECT  2.16 74.925 19.44 75.195 ;
     RECT  2.16 75.465 19.44 75.6 ;
    LAYER RVTP ;
     RECT  2.16 2.295 19.44 2.565 ;
     RECT  2.16 2.835 19.44 3.105 ;
     RECT  2.16 3.375 19.44 3.645 ;
     RECT  2.16 3.915 19.44 4.185 ;
     RECT  2.16 4.455 19.44 4.725 ;
     RECT  2.16 4.995 19.44 5.265 ;
     RECT  2.16 5.535 19.44 5.805 ;
     RECT  2.16 6.075 19.44 6.345 ;
     RECT  2.16 6.615 19.44 6.885 ;
     RECT  2.16 7.155 19.44 7.425 ;
     RECT  2.16 7.695 19.44 7.965 ;
     RECT  2.16 8.235 19.44 8.505 ;
     RECT  2.16 8.775 19.44 9.045 ;
     RECT  2.16 9.315 19.44 9.585 ;
     RECT  2.16 9.855 19.44 10.125 ;
     RECT  2.16 10.395 19.44 10.665 ;
     RECT  2.16 10.935 19.44 11.205 ;
     RECT  2.16 11.475 19.44 11.745 ;
     RECT  2.16 12.015 19.44 12.285 ;
     RECT  2.16 12.555 19.44 12.825 ;
     RECT  2.16 13.095 19.44 13.365 ;
     RECT  2.16 13.635 19.44 13.905 ;
     RECT  2.16 14.175 19.44 14.445 ;
     RECT  2.16 14.715 19.44 14.985 ;
     RECT  2.16 15.255 19.44 15.525 ;
     RECT  2.16 15.795 19.44 16.065 ;
     RECT  2.16 16.335 19.44 16.605 ;
     RECT  2.16 16.875 19.44 17.145 ;
     RECT  2.16 17.415 19.44 17.685 ;
     RECT  2.16 17.955 19.44 18.225 ;
     RECT  2.16 18.495 19.44 18.765 ;
     RECT  2.16 19.035 19.44 19.305 ;
     RECT  2.16 19.575 19.44 19.845 ;
     RECT  2.16 20.115 19.44 20.385 ;
     RECT  2.16 20.655 19.44 20.925 ;
     RECT  2.16 21.195 19.44 21.465 ;
     RECT  2.16 21.735 19.44 22.005 ;
     RECT  2.16 22.275 19.44 22.545 ;
     RECT  2.16 22.815 19.44 23.085 ;
     RECT  2.16 23.355 19.44 23.625 ;
     RECT  2.16 23.895 19.44 24.165 ;
     RECT  2.16 24.435 19.44 24.705 ;
     RECT  2.16 24.975 19.44 25.245 ;
     RECT  2.16 25.515 19.44 25.785 ;
     RECT  2.16 26.055 19.44 26.325 ;
     RECT  2.16 26.595 19.44 26.865 ;
     RECT  2.16 27.135 19.44 27.405 ;
     RECT  2.16 27.675 19.44 27.945 ;
     RECT  2.16 28.215 19.44 28.485 ;
     RECT  2.16 28.755 19.44 29.025 ;
     RECT  2.16 29.295 19.44 29.565 ;
     RECT  2.16 29.835 19.44 30.105 ;
     RECT  2.16 30.375 19.44 30.645 ;
     RECT  2.16 30.915 19.44 31.185 ;
     RECT  2.16 31.455 19.44 31.725 ;
     RECT  2.16 31.995 19.44 32.265 ;
     RECT  2.16 32.535 19.44 32.805 ;
     RECT  2.16 33.075 19.44 33.345 ;
     RECT  2.16 33.615 19.44 33.885 ;
     RECT  2.16 34.155 19.44 34.425 ;
     RECT  2.16 34.695 19.44 34.965 ;
     RECT  2.16 35.235 19.44 35.505 ;
     RECT  2.16 35.775 19.44 36.045 ;
     RECT  2.16 36.315 19.44 36.585 ;
     RECT  2.16 36.855 19.44 37.125 ;
     RECT  2.16 37.395 19.44 37.665 ;
     RECT  2.16 37.935 19.44 38.205 ;
     RECT  2.16 38.475 19.44 38.745 ;
     RECT  2.16 39.015 19.44 39.285 ;
     RECT  2.16 39.555 19.44 39.825 ;
     RECT  2.16 40.095 19.44 40.365 ;
     RECT  2.16 40.635 19.44 40.905 ;
     RECT  2.16 41.175 19.44 41.445 ;
     RECT  2.16 41.715 19.44 41.985 ;
     RECT  2.16 42.255 19.44 42.525 ;
     RECT  2.16 42.795 19.44 43.065 ;
     RECT  2.16 43.335 19.44 43.605 ;
     RECT  2.16 43.875 19.44 44.145 ;
     RECT  2.16 44.415 19.44 44.685 ;
     RECT  2.16 44.955 19.44 45.225 ;
     RECT  2.16 45.495 19.44 45.765 ;
     RECT  2.16 46.035 19.44 46.305 ;
     RECT  2.16 46.575 19.44 46.845 ;
     RECT  2.16 47.115 19.44 47.385 ;
     RECT  2.16 47.655 19.44 47.925 ;
     RECT  2.16 48.195 19.44 48.465 ;
     RECT  2.16 48.735 19.44 49.005 ;
     RECT  2.16 49.275 19.44 49.545 ;
     RECT  2.16 49.815 19.44 50.085 ;
     RECT  2.16 50.355 19.44 50.625 ;
     RECT  2.16 50.895 19.44 51.165 ;
     RECT  2.16 51.435 19.44 51.705 ;
     RECT  2.16 51.975 19.44 52.245 ;
     RECT  2.16 52.515 19.44 52.785 ;
     RECT  2.16 53.055 19.44 53.325 ;
     RECT  2.16 53.595 19.44 53.865 ;
     RECT  2.16 54.135 19.44 54.405 ;
     RECT  2.16 54.675 19.44 54.945 ;
     RECT  2.16 55.215 19.44 55.485 ;
     RECT  2.16 55.755 19.44 56.025 ;
     RECT  2.16 56.295 19.44 56.565 ;
     RECT  2.16 56.835 19.44 57.105 ;
     RECT  2.16 57.375 19.44 57.645 ;
     RECT  2.16 57.915 19.44 58.185 ;
     RECT  2.16 58.455 19.44 58.725 ;
     RECT  2.16 58.995 19.44 59.265 ;
     RECT  2.16 59.535 19.44 59.805 ;
     RECT  2.16 60.075 19.44 60.345 ;
     RECT  2.16 60.615 19.44 60.885 ;
     RECT  2.16 61.155 19.44 61.425 ;
     RECT  2.16 61.695 19.44 61.965 ;
     RECT  2.16 62.235 19.44 62.505 ;
     RECT  2.16 62.775 19.44 63.045 ;
     RECT  2.16 63.315 19.44 63.585 ;
     RECT  2.16 63.855 19.44 64.125 ;
     RECT  2.16 64.395 19.44 64.665 ;
     RECT  2.16 64.935 19.44 65.205 ;
     RECT  2.16 65.475 19.44 65.745 ;
     RECT  2.16 66.015 19.44 66.285 ;
     RECT  2.16 66.555 19.44 66.825 ;
     RECT  2.16 67.095 19.44 67.365 ;
     RECT  2.16 67.635 19.44 67.905 ;
     RECT  2.16 68.175 19.44 68.445 ;
     RECT  2.16 68.715 19.44 68.985 ;
     RECT  2.16 69.255 19.44 69.525 ;
     RECT  2.16 69.795 19.44 70.065 ;
     RECT  2.16 70.335 19.44 70.605 ;
     RECT  2.16 70.875 19.44 71.145 ;
     RECT  2.16 71.415 19.44 71.685 ;
     RECT  2.16 71.955 19.44 72.225 ;
     RECT  2.16 72.495 19.44 72.765 ;
     RECT  2.16 73.035 19.44 73.305 ;
     RECT  2.16 73.575 19.44 73.845 ;
     RECT  2.16 74.115 19.44 74.385 ;
     RECT  2.16 74.655 19.44 74.925 ;
     RECT  2.16 75.195 19.44 75.465 ;
    LAYER M1 ;
     RECT  2.16 2.151 19.44 75.609 ;
    LAYER M2 ;
     RECT  0.211 67.068 0.247 67.086 ;
     RECT  0.211 46.116 0.535 46.134 ;
     RECT  0.499 49.446 0.535 49.464 ;
     RECT  0.211 53.334 0.535 53.352 ;
     RECT  0.211 56.916 0.535 56.934 ;
     RECT  0.211 64.296 0.535 64.314 ;
     RECT  0.211 72.774 0.535 72.792 ;
     RECT  0.211 7.2 2.16 7.218 ;
     RECT  0.211 8.514 2.16 9.108 ;
     RECT  0.211 14.22 2.16 14.778 ;
     RECT  0.535 27.216 2.16 27.234 ;
     RECT  0.211 28.962 2.16 28.98 ;
     RECT  0.211 33.012 2.16 33.03 ;
     RECT  0.211 37.602 2.16 37.62 ;
     RECT  0.535 39.258 2.16 39.276 ;
     RECT  0.211 40.266 2.16 41.004 ;
     RECT  0.535 42.696 2.16 43.254 ;
     RECT  0.535 45.576 2.16 46.134 ;
     RECT  0.535 47.556 2.16 47.574 ;
     RECT  0.535 49.284 2.16 50.148 ;
     RECT  0.535 53.334 2.16 54.594 ;
     RECT  0.535 56.916 2.16 57.834 ;
     RECT  0.535 59.616 2.16 59.634 ;
     RECT  0.535 63.216 2.16 64.314 ;
     RECT  0.535 65.916 2.16 65.934 ;
     RECT  0.247 66.726 2.16 67.086 ;
     RECT  0.535 68.688 2.16 68.706 ;
     RECT  0.535 70.074 2.16 70.092 ;
     RECT  0.535 72.126 2.16 72.792 ;
     RECT  2.16 2.151 19.44 75.609 ;
     RECT  19.44 4.626 19.967 26.352 ;
     RECT  19.44 27.216 19.967 35.262 ;
     RECT  19.44 36.018 19.967 42.984 ;
     RECT  19.44 43.776 19.967 50.544 ;
     RECT  19.44 51.48 19.967 73.224 ;
     RECT  19.967 24.336 20.003 26.352 ;
     RECT  19.967 56.268 20.003 69.21 ;
     RECT  19.967 70.344 20.003 71.784 ;
     RECT  19.967 36.018 20.039 38.304 ;
     RECT  20.003 63.252 20.039 69.21 ;
     RECT  20.039 63.252 20.147 68.904 ;
     RECT  20.039 36.018 20.219 37.044 ;
     RECT  19.967 15.534 20.471 23.544 ;
     RECT  20.003 25.146 20.471 26.352 ;
     RECT  19.967 4.626 20.507 14.508 ;
     RECT  20.471 15.534 20.507 19.764 ;
     RECT  20.471 20.592 20.507 23.274 ;
     RECT  20.003 24.336 20.507 24.354 ;
     RECT  20.471 25.416 20.507 26.352 ;
     RECT  19.967 28.458 20.507 30.834 ;
     RECT  20.219 36.018 20.507 36.954 ;
     RECT  19.967 39.186 20.507 42.894 ;
     RECT  19.967 43.848 20.507 50.544 ;
     RECT  19.967 72.936 20.507 73.224 ;
     RECT  20.507 5.616 20.543 7.254 ;
     RECT  20.507 9.9 20.543 10.656 ;
     RECT  20.507 11.52 20.543 13.32 ;
     RECT  20.507 14.184 20.543 14.508 ;
     RECT  20.507 15.534 20.543 15.552 ;
     RECT  20.507 16.416 20.543 16.704 ;
     RECT  20.507 17.766 20.543 17.982 ;
     RECT  20.507 18.774 20.543 19.134 ;
     RECT  20.507 20.592 20.543 21.294 ;
     RECT  20.507 22.626 20.543 23.184 ;
     RECT  20.507 25.758 20.543 26.352 ;
     RECT  20.507 28.458 20.543 28.782 ;
     RECT  20.507 29.646 20.543 30.834 ;
     RECT  19.967 31.662 20.543 32.868 ;
     RECT  19.967 34.164 20.543 34.182 ;
     RECT  19.967 35.046 20.543 35.262 ;
     RECT  20.507 36.126 20.543 36.954 ;
     RECT  20.039 38.25 20.543 38.304 ;
     RECT  20.507 39.186 20.543 41.67 ;
     RECT  20.507 42.876 20.543 42.894 ;
     RECT  20.507 43.848 20.543 43.866 ;
     RECT  20.507 45.198 20.543 45.828 ;
     RECT  20.507 46.854 20.543 48.384 ;
     RECT  20.507 49.554 20.543 49.914 ;
     RECT  19.967 51.48 20.543 55.512 ;
     RECT  20.003 56.268 20.543 62.424 ;
     RECT  20.147 63.252 20.543 64.224 ;
     RECT  20.147 65.286 20.543 68.904 ;
     RECT  20.003 70.344 20.543 70.524 ;
     RECT  20.003 71.766 20.543 71.784 ;
     RECT  20.507 72.936 20.543 72.954 ;
     RECT  20.543 6.084 20.579 6.102 ;
     RECT  20.543 6.858 20.579 7.254 ;
     RECT  20.507 8.046 20.579 8.532 ;
     RECT  20.543 11.52 20.579 11.538 ;
     RECT  20.543 12.492 20.579 12.51 ;
     RECT  20.543 14.256 20.579 14.274 ;
     RECT  20.543 18.774 20.579 18.792 ;
     RECT  20.543 26.028 20.579 26.046 ;
     RECT  20.543 29.646 20.579 29.79 ;
     RECT  20.543 32.706 20.579 32.724 ;
     RECT  20.543 35.046 20.579 35.064 ;
     RECT  20.543 39.186 20.579 39.474 ;
     RECT  20.543 46.854 20.579 47.682 ;
     RECT  20.543 51.678 20.579 53.586 ;
     RECT  20.543 55.458 20.579 55.512 ;
     RECT  20.543 57.546 20.579 59.562 ;
     RECT  20.543 60.624 20.579 61.182 ;
     RECT  20.543 63.594 20.579 64.224 ;
     RECT  20.543 65.286 20.579 66.546 ;
     RECT  20.543 67.608 20.579 68.004 ;
     RECT  20.543 68.796 20.579 68.814 ;
     RECT  20.543 70.416 20.579 70.434 ;
     RECT  20.579 6.858 20.615 7.11 ;
     RECT  20.579 29.772 20.615 29.79 ;
     RECT  20.543 38.25 20.615 38.268 ;
     RECT  20.579 39.456 20.615 39.474 ;
     RECT  20.579 53.496 20.615 53.55 ;
     RECT  20.579 58.698 20.615 58.716 ;
     RECT  20.579 61.164 20.615 61.182 ;
     RECT  20.579 63.594 20.615 63.612 ;
     RECT  20.579 65.556 20.615 65.574 ;
     RECT  20.579 67.608 20.615 67.626 ;
     RECT  20.615 6.858 20.651 6.876 ;
     RECT  20.579 51.678 20.651 52.434 ;
     RECT  20.579 55.494 20.651 55.512 ;
     RECT  20.579 66.456 20.651 66.546 ;
     RECT  20.615 53.532 20.687 53.55 ;
     RECT  20.579 47.286 21.371 47.304 ;
     RECT  20.651 52.416 21.407 52.434 ;
     RECT  21.379 43.236 21.479 43.254 ;
     RECT  21.379 58.23 21.479 58.248 ;
    LAYER M3 ;
     RECT  10.404 1.723 10.422 2.143 ;
     RECT  10.404 2.143 10.605 2.255 ;
     RECT  2.415 2.143 2.505 2.413 ;
     RECT  5.115 2.143 5.205 2.413 ;
     RECT  7.815 2.143 7.905 2.413 ;
     RECT  10.512 2.255 10.605 2.413 ;
     RECT  13.215 2.143 13.305 2.413 ;
     RECT  15.915 2.143 16.005 2.413 ;
     RECT  18.615 2.143 18.705 2.413 ;
     RECT  10.512 2.413 10.797 2.525 ;
     RECT  2.415 2.413 2.697 4.225 ;
     RECT  2.376 4.225 2.697 4.261 ;
     RECT  2.376 4.261 2.898 4.507 ;
     RECT  9.396 2.641 9.414 4.685 ;
     RECT  18.615 2.413 18.897 4.699 ;
     RECT  18.504 4.699 18.897 4.729 ;
     RECT  5.115 2.413 5.397 4.765 ;
     RECT  18.504 4.729 19.098 4.765 ;
     RECT  6.84 4.729 6.858 4.801 ;
     RECT  9.252 4.729 9.27 4.801 ;
     RECT  15.915 2.413 16.197 4.801 ;
     RECT  9 4.801 9.27 4.829 ;
     RECT  17.748 4.765 19.098 4.829 ;
     RECT  2.304 4.507 2.898 4.999 ;
     RECT  4.032 4.765 5.397 4.999 ;
     RECT  6.336 4.801 6.858 4.999 ;
     RECT  7.815 2.413 8.097 4.999 ;
     RECT  2.304 4.999 5.397 5.035 ;
     RECT  6.336 4.999 8.097 5.035 ;
     RECT  20.484 4.507 20.502 5.179 ;
     RECT  2.304 5.035 8.097 5.189 ;
     RECT  17.748 4.829 18.897 5.225 ;
     RECT  20.484 5.179 20.538 5.371 ;
     RECT  6.624 5.189 8.097 5.431 ;
     RECT  9 4.829 9.018 5.431 ;
     RECT  18.576 5.225 18.897 5.459 ;
     RECT  14.256 4.765 14.274 5.503 ;
     RECT  14.256 5.503 14.922 5.701 ;
     RECT  15.915 4.801 16.686 5.701 ;
     RECT  20.484 5.371 20.574 5.707 ;
     RECT  14.256 5.701 16.686 5.737 ;
     RECT  10.515 2.525 10.797 5.773 ;
     RECT  10.515 5.773 10.854 5.873 ;
     RECT  17.748 5.225 17.802 5.971 ;
     RECT  6.624 5.431 9.018 6.043 ;
     RECT  2.304 5.189 5.742 6.151 ;
     RECT  6.624 6.043 9.558 6.151 ;
     RECT  13.215 2.413 13.497 6.241 ;
     RECT  2.304 6.151 9.558 6.269 ;
     RECT  2.304 6.269 8.097 6.305 ;
     RECT  2.304 6.305 5.397 6.313 ;
     RECT  14.256 5.737 16.758 6.385 ;
     RECT  17.532 5.971 17.802 6.385 ;
     RECT  18.615 5.459 18.897 6.385 ;
     RECT  14.256 6.385 17.802 6.421 ;
     RECT  18.615 6.385 19.062 6.421 ;
     RECT  10.515 5.873 10.797 6.619 ;
     RECT  2.268 6.313 5.397 6.647 ;
     RECT  2.304 6.647 5.397 6.845 ;
     RECT  10.515 6.619 10.854 6.845 ;
     RECT  19.944 5.707 20.574 6.853 ;
     RECT  14.256 6.421 19.062 6.925 ;
     RECT  13.14 6.241 13.497 6.961 ;
     RECT  14.256 6.925 19.098 6.961 ;
     RECT  19.944 6.853 20.646 7.037 ;
     RECT  13.14 6.961 19.098 7.087 ;
     RECT  19.944 7.037 20.61 7.115 ;
     RECT  6.264 6.305 8.097 7.195 ;
     RECT  9 6.269 9.018 7.195 ;
     RECT  19.944 7.115 20.574 7.259 ;
     RECT  3.744 6.845 5.397 7.321 ;
     RECT  6.264 7.195 9.018 7.321 ;
     RECT  13.14 7.087 19.17 7.321 ;
     RECT  19.944 7.259 20.538 7.321 ;
     RECT  13.14 7.321 20.538 7.373 ;
     RECT  3.744 7.321 9.018 7.421 ;
     RECT  19.944 7.373 20.538 7.421 ;
     RECT  7.128 7.421 9.018 7.501 ;
     RECT  7.128 7.501 9.594 7.517 ;
     RECT  0.216 7.195 0.234 7.565 ;
     RECT  2.304 6.845 2.97 7.591 ;
     RECT  3.744 7.421 6.282 7.591 ;
     RECT  9.576 7.517 9.594 7.619 ;
     RECT  7.128 7.517 8.838 7.763 ;
     RECT  10.515 6.845 10.797 7.771 ;
     RECT  10.515 7.771 10.854 7.925 ;
     RECT  20.484 7.421 20.538 8.011 ;
     RECT  13.14 7.373 18.954 8.041 ;
     RECT  2.304 7.591 6.282 8.395 ;
     RECT  7.128 7.763 8.586 8.395 ;
     RECT  12.564 8.041 18.954 8.465 ;
     RECT  20.484 8.011 20.574 8.537 ;
     RECT  2.304 8.395 8.586 8.545 ;
     RECT  12.816 8.465 18.954 8.545 ;
     RECT  20.484 8.537 20.538 8.573 ;
     RECT  12.816 8.545 19.098 8.683 ;
     RECT  2.304 8.545 8.838 8.843 ;
     RECT  20.484 8.573 20.502 9.019 ;
     RECT  12.816 8.683 19.422 9.211 ;
     RECT  20.448 9.019 20.502 9.211 ;
     RECT  0.216 8.509 0.234 9.341 ;
     RECT  12.816 9.211 20.502 9.419 ;
     RECT  20.448 9.419 20.502 9.499 ;
     RECT  20.448 9.499 20.538 9.509 ;
     RECT  2.304 8.843 8.586 9.625 ;
     RECT  2.304 9.625 8.838 10.253 ;
     RECT  3.924 10.253 8.838 10.471 ;
     RECT  3.924 10.471 9.594 10.589 ;
     RECT  12.816 9.419 19.422 10.699 ;
     RECT  20.484 9.509 20.538 10.699 ;
     RECT  5.004 10.589 9.306 10.733 ;
     RECT  2.304 10.253 3.114 10.795 ;
     RECT  7.2 10.733 9.306 10.859 ;
     RECT  12.816 10.699 20.538 10.859 ;
     RECT  2.268 10.795 3.114 10.895 ;
     RECT  2.304 10.895 3.114 11.011 ;
     RECT  3.924 10.589 4.266 11.011 ;
     RECT  12.816 10.859 19.422 11.039 ;
     RECT  0.216 11.035 0.234 11.165 ;
     RECT  20.484 10.859 20.538 11.371 ;
     RECT  2.304 11.011 4.266 11.419 ;
     RECT  5.004 10.733 6.39 11.419 ;
     RECT  20.484 11.371 20.574 11.543 ;
     RECT  2.304 11.419 6.39 11.551 ;
     RECT  7.2 10.859 8.874 11.551 ;
     RECT  20.484 11.543 20.538 11.677 ;
     RECT  2.304 11.551 8.874 11.705 ;
     RECT  10.515 7.925 10.797 11.713 ;
     RECT  20.448 11.677 20.538 11.741 ;
     RECT  12.816 11.039 19.062 11.785 ;
     RECT  10.515 11.713 10.854 11.939 ;
     RECT  12.816 11.785 19.098 11.995 ;
     RECT  12.816 11.995 19.422 12.055 ;
     RECT  12.816 12.055 19.494 12.221 ;
     RECT  20.484 11.741 20.538 12.331 ;
     RECT  20.484 12.331 20.574 12.515 ;
     RECT  2.304 11.705 8.586 12.623 ;
     RECT  7.2 12.623 8.586 12.631 ;
     RECT  9.684 12.631 9.702 12.749 ;
     RECT  7.2 12.631 8.874 12.901 ;
     RECT  12.816 12.221 19.422 12.929 ;
     RECT  20.484 12.515 20.538 13.003 ;
     RECT  20.448 13.003 20.538 13.333 ;
     RECT  19.944 13.333 20.538 13.373 ;
     RECT  2.304 12.623 6.462 13.441 ;
     RECT  7.2 12.901 9.522 13.441 ;
     RECT  2.304 13.441 9.522 13.469 ;
     RECT  2.304 13.469 9.342 13.559 ;
     RECT  12.816 12.929 18.897 13.675 ;
     RECT  2.304 13.559 8.838 13.703 ;
     RECT  12.816 13.675 18.954 13.801 ;
     RECT  12.816 13.801 19.098 13.901 ;
     RECT  20.484 13.373 20.538 14.203 ;
     RECT  20.484 14.203 20.574 14.279 ;
     RECT  10.515 11.939 10.797 14.341 ;
     RECT  2.304 13.703 8.586 14.485 ;
     RECT  20.484 14.279 20.538 14.513 ;
     RECT  10.515 14.341 10.854 14.747 ;
     RECT  2.304 14.485 8.838 14.783 ;
     RECT  12.816 13.901 18.954 14.818 ;
     RECT  0.216 14.215 0.234 14.861 ;
     RECT  12.816 14.818 18.99 15.151 ;
     RECT  19.944 14.683 19.962 15.151 ;
     RECT  12.816 15.151 19.962 15.355 ;
     RECT  12.816 15.355 20.538 15.533 ;
     RECT  2.304 14.783 8.766 15.565 ;
     RECT  0.216 15.595 0.234 15.773 ;
     RECT  12.816 15.533 19.314 15.872 ;
     RECT  2.304 15.565 8.838 16.411 ;
     RECT  9.576 15.601 9.594 16.411 ;
     RECT  2.304 16.411 9.594 16.529 ;
     RECT  12.816 15.872 19.026 16.541 ;
     RECT  2.304 16.529 8.874 16.565 ;
     RECT  20.484 15.533 20.538 16.733 ;
     RECT  20.484 16.733 20.502 16.771 ;
     RECT  2.304 16.565 8.586 17.491 ;
     RECT  19.944 16.771 20.502 17.515 ;
     RECT  19.944 17.515 20.538 17.519 ;
     RECT  2.304 17.491 9.594 17.609 ;
     RECT  2.304 17.609 8.874 17.645 ;
     RECT  12.816 16.541 18.99 17.659 ;
     RECT  20.52 17.519 20.538 17.995 ;
     RECT  20.52 17.995 20.61 18.173 ;
     RECT  2.304 17.645 8.586 18.331 ;
     RECT  20.52 18.173 20.574 18.331 ;
     RECT  10.515 14.747 10.797 18.427 ;
     RECT  10.515 18.427 10.854 18.527 ;
     RECT  2.268 18.331 8.586 18.571 ;
     RECT  12.816 17.659 19.026 18.667 ;
     RECT  2.268 18.571 8.874 18.725 ;
     RECT  20.484 18.331 20.574 18.797 ;
     RECT  2.304 18.725 8.586 19.103 ;
     RECT  20.484 18.797 20.538 19.139 ;
     RECT  12.816 18.667 19.422 19.195 ;
     RECT  20.484 19.139 20.502 19.195 ;
     RECT  12.816 19.195 20.502 19.337 ;
     RECT  4.176 19.103 8.586 19.651 ;
     RECT  19.944 19.337 20.502 19.769 ;
     RECT  4.176 19.651 8.874 19.805 ;
     RECT  2.304 19.103 3.438 19.885 ;
     RECT  4.176 19.805 8.838 19.885 ;
     RECT  2.304 19.885 8.838 20.183 ;
     RECT  12.816 19.337 19.062 20.347 ;
     RECT  19.944 19.769 20.466 20.347 ;
     RECT  12.816 20.347 20.466 20.453 ;
     RECT  20.448 20.453 20.466 20.491 ;
     RECT  12.816 20.453 19.422 20.579 ;
     RECT  10.515 18.527 10.797 20.587 ;
     RECT  10.515 20.587 10.854 20.687 ;
     RECT  4.068 20.183 8.838 20.723 ;
     RECT  2.304 20.183 3.33 20.849 ;
     RECT  4.068 20.723 8.586 21.119 ;
     RECT  4.068 21.119 4.194 21.271 ;
     RECT  20.448 20.491 20.538 21.389 ;
     RECT  4.968 21.119 8.586 21.505 ;
     RECT  2.304 20.849 3.258 21.631 ;
     RECT  3.996 21.271 4.194 21.631 ;
     RECT  4.968 21.505 8.838 21.803 ;
     RECT  20.448 21.389 20.502 21.835 ;
     RECT  2.304 21.631 4.194 22.009 ;
     RECT  4.968 21.803 8.586 22.009 ;
     RECT  12.816 20.579 18.99 22.363 ;
     RECT  19.944 21.835 20.502 22.363 ;
     RECT  12.816 22.363 20.502 22.379 ;
     RECT  12.816 22.379 19.422 22.469 ;
     RECT  10.515 20.687 10.797 22.513 ;
     RECT  20.484 22.379 20.502 22.621 ;
     RECT  10.515 22.513 10.854 22.739 ;
     RECT  2.304 22.009 8.586 22.891 ;
     RECT  2.304 22.891 9.306 23.009 ;
     RECT  2.304 23.009 8.874 23.045 ;
     RECT  20.484 22.621 20.538 23.179 ;
     RECT  20.448 23.179 20.538 23.189 ;
     RECT  2.304 23.045 8.838 23.279 ;
     RECT  20.448 23.189 20.502 23.279 ;
     RECT  20.448 23.279 20.466 23.515 ;
     RECT  10.515 22.739 10.797 23.593 ;
     RECT  12.816 22.469 19.062 23.665 ;
     RECT  10.515 23.593 10.818 23.729 ;
     RECT  4.968 23.279 8.838 23.963 ;
     RECT  2.304 23.279 4.194 24.133 ;
     RECT  4.968 23.963 8.586 24.133 ;
     RECT  19.944 23.515 20.466 24.187 ;
     RECT  12.816 23.665 19.134 24.523 ;
     RECT  19.944 24.187 20.502 24.523 ;
     RECT  2.304 24.133 8.586 24.629 ;
     RECT  6.912 24.629 8.586 24.745 ;
     RECT  6.912 24.745 8.838 24.809 ;
     RECT  2.304 24.629 5.814 24.859 ;
     RECT  7.164 24.809 8.838 25.043 ;
     RECT  12.816 24.523 20.502 25.313 ;
     RECT  12.816 25.313 19.458 25.349 ;
     RECT  2.268 24.859 5.814 25.531 ;
     RECT  2.268 25.531 6.39 25.675 ;
     RECT  20.484 25.313 20.502 25.675 ;
     RECT  10.515 23.729 10.797 25.753 ;
     RECT  7.164 25.043 8.586 25.825 ;
     RECT  2.268 25.675 6.426 25.853 ;
     RECT  2.304 25.853 6.426 25.861 ;
     RECT  7.164 25.825 8.838 25.861 ;
     RECT  20.484 25.675 20.538 26.011 ;
     RECT  0.216 25.867 0.234 26.045 ;
     RECT  20.484 26.011 20.574 26.051 ;
     RECT  12.816 25.349 19.422 26.155 ;
     RECT  20.484 26.051 20.538 26.155 ;
     RECT  12.816 26.155 20.538 26.357 ;
     RECT  2.304 25.861 8.838 26.599 ;
     RECT  2.304 26.599 9.126 26.699 ;
     RECT  10.515 25.753 10.854 26.699 ;
     RECT  2.304 26.699 8.838 27.329 ;
     RECT  0.54 27.211 0.558 27.437 ;
     RECT  3.96 27.329 8.838 27.751 ;
     RECT  3.96 27.751 8.874 27.869 ;
     RECT  7.128 27.869 8.874 27.905 ;
     RECT  2.304 27.329 3.222 28.291 ;
     RECT  3.96 27.869 6.39 28.291 ;
     RECT  12.816 26.357 20.322 28.411 ;
     RECT  12.816 28.411 20.538 28.787 ;
     RECT  2.304 28.291 6.39 28.795 ;
     RECT  7.128 27.905 8.586 28.795 ;
     RECT  2.304 28.795 8.586 28.831 ;
     RECT  10.515 26.699 10.797 28.831 ;
     RECT  2.304 28.831 8.874 28.985 ;
     RECT  0.216 28.651 0.234 29.165 ;
     RECT  2.304 28.985 8.586 29.219 ;
     RECT  3.96 29.219 8.586 29.255 ;
     RECT  2.304 29.219 3.222 29.291 ;
     RECT  10.515 28.831 10.854 29.291 ;
     RECT  11.844 22.207 11.862 29.641 ;
     RECT  12.816 28.787 20.502 29.641 ;
     RECT  12.816 29.641 20.574 29.767 ;
     RECT  4.932 29.255 8.586 29.911 ;
     RECT  11.52 29.641 11.862 30.029 ;
     RECT  4.932 29.911 8.874 30.065 ;
     RECT  12.816 29.767 20.61 30.077 ;
     RECT  2.304 29.291 2.862 30.181 ;
     RECT  3.96 29.255 4.194 30.181 ;
     RECT  4.932 30.065 8.586 30.181 ;
     RECT  2.304 30.181 8.586 30.875 ;
     RECT  2.415 30.875 8.586 30.883 ;
     RECT  2.415 30.883 9.018 31.019 ;
     RECT  4.068 31.019 9.018 31.289 ;
     RECT  10.515 29.291 10.797 31.459 ;
     RECT  11.52 30.029 11.538 31.459 ;
     RECT  2.415 31.019 3.33 31.675 ;
     RECT  2.304 31.675 3.33 31.765 ;
     RECT  4.068 31.289 8.838 31.765 ;
     RECT  12.816 30.077 20.538 31.801 ;
     RECT  10.515 31.459 11.538 31.829 ;
     RECT  2.304 31.765 8.838 32.063 ;
     RECT  11.52 31.829 11.538 32.197 ;
     RECT  12.564 31.801 20.538 32.197 ;
     RECT  11.52 32.197 20.538 32.225 ;
     RECT  10.515 31.829 10.797 32.611 ;
     RECT  11.52 32.225 11.934 32.611 ;
     RECT  12.816 32.225 20.538 32.701 ;
     RECT  10.515 32.611 11.934 32.765 ;
     RECT  2.304 32.063 8.586 32.845 ;
     RECT  9.612 32.881 9.63 32.999 ;
     RECT  12.816 32.701 20.574 33.101 ;
     RECT  2.304 32.845 8.838 33.143 ;
     RECT  0.216 33.007 0.234 33.197 ;
     RECT  12.816 33.101 20.286 33.583 ;
     RECT  2.304 33.143 8.586 33.925 ;
     RECT  10.515 32.765 10.797 33.961 ;
     RECT  11.52 32.765 11.934 33.961 ;
     RECT  12.78 33.583 20.286 34.075 ;
     RECT  10.515 33.961 11.934 34.079 ;
     RECT  12.78 34.075 20.538 34.187 ;
     RECT  2.304 33.925 8.838 34.771 ;
     RECT  10.515 34.079 10.797 34.897 ;
     RECT  11.52 34.079 11.934 34.897 ;
     RECT  2.304 34.771 8.874 35.041 ;
     RECT  10.515 34.897 11.934 35.041 ;
     RECT  12.78 34.187 20.286 35.041 ;
     RECT  2.304 35.041 9.018 35.267 ;
     RECT  10.515 35.041 20.574 35.405 ;
     RECT  2.304 35.267 8.874 35.429 ;
     RECT  2.304 35.429 4.194 35.465 ;
     RECT  10.515 35.405 20.538 35.609 ;
     RECT  4.968 35.429 8.874 36.005 ;
     RECT  4.032 35.465 4.194 36.319 ;
     RECT  4.968 36.005 8.586 36.319 ;
     RECT  10.515 35.609 10.797 36.553 ;
     RECT  11.52 35.609 20.538 36.553 ;
     RECT  2.304 35.465 3.294 36.589 ;
     RECT  4.032 36.319 8.586 36.589 ;
     RECT  10.515 36.553 20.538 36.689 ;
     RECT  9.468 36.661 9.486 36.779 ;
     RECT  11.52 36.689 20.538 36.779 ;
     RECT  2.304 36.589 8.586 36.931 ;
     RECT  2.304 36.931 9.27 37.049 ;
     RECT  2.304 37.049 8.874 37.085 ;
     RECT  20.196 36.779 20.538 37.085 ;
     RECT  2.304 37.085 8.586 37.195 ;
     RECT  2.268 37.195 8.586 37.355 ;
     RECT  11.52 36.779 19.422 37.597 ;
     RECT  0.216 37.597 0.234 37.709 ;
     RECT  2.304 37.355 8.586 38.003 ;
     RECT  4.392 38.003 8.586 38.011 ;
     RECT  4.392 38.011 8.874 38.165 ;
     RECT  10.515 36.689 10.797 38.209 ;
     RECT  11.52 37.597 20.034 38.209 ;
     RECT  10.515 38.209 20.034 38.245 ;
     RECT  10.515 38.245 20.61 38.579 ;
     RECT  4.392 38.165 8.838 38.705 ;
     RECT  2.304 38.003 3.402 38.911 ;
     RECT  2.304 38.911 4.014 38.939 ;
     RECT  4.932 38.705 8.838 39.083 ;
     RECT  10.515 38.579 19.422 39.101 ;
     RECT  2.304 38.939 2.754 39.209 ;
     RECT  4.932 39.083 8.37 39.209 ;
     RECT  0.54 39.253 0.558 39.389 ;
     RECT  6.12 39.209 8.37 39.389 ;
     RECT  3.996 38.939 4.014 39.559 ;
     RECT  10.515 39.101 19.278 39.587 ;
     RECT  2.304 39.209 2.697 39.659 ;
     RECT  3.996 39.559 4.05 39.659 ;
     RECT  6.192 39.389 8.37 39.659 ;
     RECT  20.52 38.579 20.61 39.773 ;
     RECT  3.852 39.721 3.978 39.821 ;
     RECT  9.72 39.721 9.738 39.829 ;
     RECT  4.932 39.209 5.397 39.857 ;
     RECT  6.912 39.659 8.37 39.857 ;
     RECT  9.684 39.829 9.738 39.901 ;
     RECT  10.515 39.587 10.797 39.901 ;
     RECT  2.415 39.659 2.697 39.991 ;
     RECT  11.52 39.587 19.278 39.991 ;
     RECT  20.52 39.773 20.538 39.991 ;
     RECT  9.684 39.901 10.797 40.019 ;
     RECT  7.272 39.857 8.37 40.135 ;
     RECT  3.96 39.821 3.978 40.163 ;
     RECT  9.684 40.019 9.702 40.199 ;
     RECT  7.272 40.135 8.55 40.289 ;
     RECT  4.968 39.857 5.397 40.363 ;
     RECT  4.968 40.363 5.634 40.405 ;
     RECT  4.968 40.405 5.994 40.559 ;
     RECT  4.968 40.559 5.922 40.711 ;
     RECT  4.176 40.639 4.194 40.829 ;
     RECT  4.932 40.711 5.922 40.865 ;
     RECT  7.272 40.289 8.097 40.873 ;
     RECT  6.804 40.873 8.097 41.009 ;
     RECT  0.216 40.261 0.234 41.117 ;
     RECT  3.744 41.215 4.014 41.377 ;
     RECT  2.415 39.991 2.826 41.521 ;
     RECT  4.968 40.865 5.922 41.521 ;
     RECT  2.415 41.521 2.862 41.611 ;
     RECT  10.515 40.019 10.797 41.611 ;
     RECT  11.52 39.991 20.538 41.611 ;
     RECT  3.672 41.377 4.014 41.639 ;
     RECT  4.968 41.521 6.03 41.675 ;
     RECT  10.515 41.611 20.538 41.783 ;
     RECT  6.948 41.009 8.097 41.917 ;
     RECT  2.304 41.611 2.898 41.989 ;
     RECT  3.672 41.639 3.942 41.989 ;
     RECT  6.804 41.917 8.097 42.017 ;
     RECT  2.304 41.989 3.942 42.053 ;
     RECT  2.304 42.053 3.33 42.089 ;
     RECT  4.968 41.675 5.397 42.421 ;
     RECT  7.128 42.017 8.097 42.421 ;
     RECT  7.128 42.421 8.154 42.449 ;
     RECT  2.304 42.089 3.294 42.485 ;
     RECT  2.304 42.485 2.862 42.557 ;
     RECT  7.272 42.449 8.154 42.557 ;
     RECT  10.515 41.783 10.797 42.601 ;
     RECT  11.52 41.783 20.538 42.601 ;
     RECT  2.304 42.557 2.697 42.653 ;
     RECT  4.968 42.421 5.778 42.871 ;
     RECT  3.744 42.835 3.762 42.989 ;
     RECT  4.824 42.871 5.778 43.099 ;
     RECT  10.515 42.601 20.538 43.133 ;
     RECT  3.78 43.099 5.778 43.141 ;
     RECT  3.78 43.141 6.354 43.231 ;
     RECT  7.272 42.557 8.097 43.231 ;
     RECT  21.384 43.195 21.402 43.231 ;
     RECT  3.78 43.231 8.097 43.259 ;
     RECT  21.384 43.231 21.474 43.259 ;
     RECT  21.456 43.259 21.474 43.277 ;
     RECT  6.66 43.259 8.097 43.331 ;
     RECT  0.54 42.691 0.558 43.373 ;
     RECT  3.78 43.259 5.886 43.403 ;
     RECT  3.78 43.403 5.814 43.439 ;
     RECT  2.415 42.653 2.697 43.771 ;
     RECT  3.78 43.439 5.706 43.799 ;
     RECT  11.52 43.133 20.538 43.871 ;
     RECT  2.304 43.771 2.697 43.901 ;
     RECT  3.996 43.799 5.706 44.221 ;
     RECT  3.996 44.221 5.922 44.311 ;
     RECT  6.804 43.331 8.097 44.311 ;
     RECT  3.996 44.311 8.097 44.411 ;
     RECT  3.996 44.411 5.778 44.447 ;
     RECT  2.415 43.901 2.697 44.581 ;
     RECT  2.415 44.581 2.826 44.669 ;
     RECT  3.996 44.447 5.397 44.681 ;
     RECT  10.515 43.133 10.797 44.761 ;
     RECT  11.52 43.871 20.502 44.761 ;
     RECT  3.708 44.761 3.726 44.951 ;
     RECT  4.464 44.681 5.397 45.059 ;
     RECT  4.716 45.059 5.397 45.149 ;
     RECT  10.515 44.761 20.502 45.193 ;
     RECT  2.415 44.669 2.79 45.355 ;
     RECT  4.968 45.149 5.397 45.391 ;
     RECT  3.636 45.301 3.654 45.419 ;
     RECT  2.304 45.355 2.79 45.427 ;
     RECT  4.968 45.391 5.562 45.563 ;
     RECT  2.304 45.427 3.15 45.599 ;
     RECT  0.54 45.571 0.558 45.629 ;
     RECT  10.515 45.193 20.538 45.833 ;
     RECT  4.968 45.563 5.454 45.931 ;
     RECT  0.216 46.111 0.234 46.157 ;
     RECT  4.716 45.931 5.454 46.201 ;
     RECT  3.996 46.201 5.454 46.373 ;
     RECT  2.304 45.599 2.862 46.409 ;
     RECT  2.412 46.409 2.862 46.579 ;
     RECT  2.412 46.579 3.258 46.679 ;
     RECT  3.996 46.373 5.397 46.849 ;
     RECT  10.515 45.833 20.502 46.849 ;
     RECT  3.852 46.849 5.397 46.949 ;
     RECT  6.84 44.411 8.097 47.111 ;
     RECT  6.372 47.191 6.39 47.309 ;
     RECT  3.996 46.949 5.397 47.353 ;
     RECT  3.996 47.353 5.85 47.405 ;
     RECT  4.356 47.405 5.85 47.489 ;
     RECT  2.415 46.679 2.697 47.587 ;
     RECT  2.415 47.587 3.078 47.849 ;
     RECT  0.54 47.551 0.558 47.933 ;
     RECT  10.515 46.849 20.574 47.933 ;
     RECT  4.356 47.489 5.454 48.173 ;
     RECT  4.968 48.173 5.454 48.271 ;
     RECT  4.968 48.271 6.03 48.361 ;
     RECT  7.272 47.111 8.097 48.361 ;
     RECT  4.968 48.361 8.097 48.389 ;
     RECT  10.515 47.933 20.538 48.413 ;
     RECT  2.415 47.849 2.826 48.631 ;
     RECT  3.96 48.433 4.05 48.631 ;
     RECT  2.376 48.631 4.05 48.731 ;
     RECT  2.376 48.731 2.79 49.147 ;
     RECT  4.968 48.389 5.397 49.171 ;
     RECT  6.336 48.389 8.097 49.171 ;
     RECT  2.304 49.147 2.79 49.199 ;
     RECT  4.968 49.171 8.097 49.271 ;
     RECT  4.968 49.271 6.318 49.343 ;
     RECT  3.6 48.731 4.05 49.351 ;
     RECT  4.968 49.343 5.67 49.351 ;
     RECT  2.415 49.199 2.79 49.379 ;
     RECT  3.6 49.351 5.67 49.379 ;
     RECT  0.54 49.279 0.558 49.441 ;
     RECT  7.272 49.271 8.097 49.541 ;
     RECT  10.515 48.413 20.502 49.549 ;
     RECT  3.6 49.379 5.397 49.577 ;
     RECT  3.996 49.577 5.397 49.739 ;
     RECT  0.504 49.441 0.558 49.901 ;
     RECT  10.515 49.549 20.538 49.919 ;
     RECT  4.248 49.739 5.397 50.117 ;
     RECT  0.54 49.901 0.558 50.189 ;
     RECT  4.644 50.117 5.397 50.359 ;
     RECT  4.644 50.359 5.598 50.395 ;
     RECT  6.84 50.161 6.858 50.395 ;
     RECT  4.644 50.395 6.858 50.459 ;
     RECT  6.192 50.459 6.858 50.521 ;
     RECT  7.776 49.541 8.097 50.521 ;
     RECT  6.192 50.521 8.298 50.549 ;
     RECT  10.515 49.919 20.502 50.549 ;
     RECT  6.84 50.549 8.298 50.621 ;
     RECT  6.84 50.621 8.097 50.729 ;
     RECT  2.415 49.379 2.697 50.791 ;
     RECT  2.415 50.791 3.006 50.891 ;
     RECT  6.84 50.729 6.858 50.927 ;
     RECT  21.348 47.281 21.366 50.957 ;
     RECT  4.644 50.459 5.397 51.16 ;
     RECT  4.464 51.16 5.397 51.169 ;
     RECT  4.392 51.169 5.397 51.403 ;
     RECT  10.515 50.549 20.214 51.451 ;
     RECT  3.996 51.403 5.397 51.511 ;
     RECT  10.515 51.451 20.538 51.629 ;
     RECT  20.52 51.629 20.538 51.673 ;
     RECT  3.996 51.511 5.49 51.809 ;
     RECT  2.415 50.891 2.697 51.871 ;
     RECT  3.996 51.809 4.05 51.871 ;
     RECT  5.004 51.809 5.49 51.871 ;
     RECT  2.415 51.871 2.826 51.883 ;
     RECT  3.708 51.871 4.05 51.971 ;
     RECT  2.304 51.883 2.826 52.015 ;
     RECT  20.52 51.673 20.646 52.157 ;
     RECT  5.004 51.871 6.03 52.169 ;
     RECT  6.768 52.015 6.786 52.241 ;
     RECT  6.228 52.321 6.246 52.475 ;
     RECT  21.384 52.411 21.402 52.493 ;
     RECT  5.004 52.169 5.397 52.591 ;
     RECT  7.776 50.729 8.097 52.681 ;
     RECT  10.515 51.629 19.458 52.825 ;
     RECT  20.52 52.157 20.538 52.825 ;
     RECT  2.304 52.015 3.546 52.861 ;
     RECT  4.608 52.591 5.397 52.861 ;
     RECT  2.304 52.861 5.397 52.979 ;
     RECT  10.515 52.825 20.538 53.059 ;
     RECT  2.304 52.979 3.366 53.131 ;
     RECT  2.232 53.131 3.366 53.159 ;
     RECT  4.464 52.979 5.397 53.221 ;
     RECT  2.232 53.159 2.862 53.249 ;
     RECT  4.464 53.221 5.454 53.249 ;
     RECT  7.2 52.681 8.097 53.257 ;
     RECT  5.04 53.249 5.454 53.357 ;
     RECT  6.48 53.257 8.097 53.401 ;
     RECT  8.82 52.753 8.838 53.401 ;
     RECT  0.216 53.329 0.234 53.453 ;
     RECT  10.515 53.059 20.574 53.491 ;
     RECT  6.48 53.401 8.838 53.519 ;
     RECT  10.515 53.491 20.61 53.527 ;
     RECT  2.304 53.249 2.862 53.591 ;
     RECT  6.48 53.519 8.097 53.591 ;
     RECT  4.068 53.761 4.086 53.861 ;
     RECT  2.304 53.591 2.697 53.969 ;
     RECT  5.04 53.357 5.397 54.059 ;
     RECT  6.48 53.591 6.822 54.059 ;
     RECT  6.48 54.059 6.57 54.211 ;
     RECT  6.228 54.211 6.57 54.329 ;
     RECT  6.552 54.329 6.57 54.401 ;
     RECT  5.115 54.059 5.397 54.427 ;
     RECT  5.115 54.427 5.67 54.509 ;
     RECT  7.704 53.591 8.097 54.509 ;
     RECT  10.515 53.527 20.682 54.653 ;
     RECT  7.776 54.509 8.097 54.701 ;
     RECT  3.852 54.607 3.87 54.751 ;
     RECT  3.528 54.751 3.87 54.841 ;
     RECT  5.115 54.509 5.634 54.841 ;
     RECT  3.528 54.841 5.634 54.869 ;
     RECT  0.54 53.491 0.558 54.941 ;
     RECT  10.515 54.653 20.538 55.453 ;
     RECT  4.176 54.869 5.634 55.469 ;
     RECT  10.515 55.453 20.574 55.489 ;
     RECT  5.004 55.469 5.634 55.553 ;
     RECT  4.176 55.469 4.194 55.589 ;
     RECT  5.115 55.553 5.634 55.759 ;
     RECT  6.84 55.381 6.858 55.823 ;
     RECT  2.415 53.969 2.697 55.912 ;
     RECT  2.196 55.912 2.697 55.949 ;
     RECT  3.744 55.921 3.762 56.021 ;
     RECT  5.115 55.759 6.03 56.101 ;
     RECT  10.515 55.489 20.646 56.141 ;
     RECT  2.232 55.949 2.697 56.399 ;
     RECT  5.115 56.101 6.534 56.489 ;
     RECT  6.228 56.489 6.534 56.525 ;
     RECT  2.304 56.399 2.697 56.539 ;
     RECT  10.515 56.141 20.538 56.561 ;
     RECT  6.228 56.525 6.39 56.573 ;
     RECT  7.815 54.701 8.097 56.875 ;
     RECT  8.82 53.519 8.838 56.875 ;
     RECT  12.78 56.561 20.538 56.903 ;
     RECT  0.216 56.911 0.234 56.957 ;
     RECT  7.815 56.875 8.838 57.029 ;
     RECT  2.304 56.539 2.862 57.109 ;
     RECT  2.304 57.109 3.546 57.209 ;
     RECT  5.115 56.489 5.397 57.403 ;
     RECT  19.944 56.903 20.538 57.541 ;
     RECT  6.228 56.573 6.318 57.605 ;
     RECT  4.464 57.403 5.397 57.649 ;
     RECT  7.815 57.029 8.097 57.685 ;
     RECT  4.464 57.649 5.742 57.839 ;
     RECT  7.308 57.685 8.097 57.847 ;
     RECT  7.236 57.847 8.097 57.919 ;
     RECT  2.415 57.209 3.222 57.955 ;
     RECT  6.768 57.919 8.097 58.019 ;
     RECT  12.78 56.903 19.098 58.117 ;
     RECT  19.944 57.541 20.574 58.117 ;
     RECT  0.54 57.541 0.558 58.205 ;
     RECT  12.78 58.117 20.574 58.217 ;
     RECT  21.456 58.216 21.474 58.225 ;
     RECT  12.78 58.217 19.098 58.253 ;
     RECT  21.384 58.225 21.474 58.253 ;
     RECT  21.384 58.253 21.402 58.301 ;
     RECT  2.415 57.955 3.618 58.621 ;
     RECT  4.356 58.351 4.374 58.621 ;
     RECT  5.115 57.839 5.397 58.621 ;
     RECT  19.944 58.217 20.574 58.637 ;
     RECT  19.98 58.637 20.574 58.693 ;
     RECT  5.115 58.621 5.814 58.721 ;
     RECT  6.84 58.019 6.858 58.721 ;
     RECT  7.815 58.019 8.097 58.891 ;
     RECT  2.415 58.621 4.374 58.999 ;
     RECT  5.115 58.721 5.397 58.999 ;
     RECT  7.308 58.891 8.097 59.071 ;
     RECT  8.82 57.029 8.838 59.071 ;
     RECT  7.308 59.071 8.838 59.099 ;
     RECT  19.98 58.693 20.61 59.117 ;
     RECT  2.415 58.999 5.397 59.189 ;
     RECT  2.415 59.189 2.826 59.213 ;
     RECT  3.78 59.189 5.397 59.261 ;
     RECT  7.704 59.099 8.838 59.261 ;
     RECT  3.996 59.261 5.397 59.333 ;
     RECT  2.415 59.213 2.697 59.341 ;
     RECT  3.996 59.333 4.014 59.357 ;
     RECT  7.704 59.261 8.097 59.369 ;
     RECT  8.82 59.261 8.838 59.369 ;
     RECT  2.304 59.341 2.697 59.453 ;
     RECT  19.98 59.117 20.574 59.605 ;
     RECT  5.115 59.333 5.397 59.611 ;
     RECT  5.115 59.611 5.886 59.773 ;
     RECT  6.84 59.611 6.93 59.773 ;
     RECT  0.54 59.611 0.558 59.981 ;
     RECT  19.944 59.605 20.574 59.981 ;
     RECT  5.115 59.773 6.93 59.999 ;
     RECT  6.84 59.999 6.93 60.143 ;
     RECT  12.78 58.253 19.026 60.151 ;
     RECT  5.115 59.999 5.562 60.241 ;
     RECT  7.815 59.369 8.097 60.421 ;
     RECT  2.415 59.453 2.697 60.427 ;
     RECT  2.304 60.427 2.697 60.511 ;
     RECT  4.536 60.241 5.562 60.557 ;
     RECT  6.984 60.421 8.097 60.809 ;
     RECT  2.304 60.511 2.826 60.859 ;
     RECT  6.984 60.809 7.002 60.893 ;
     RECT  12.78 60.151 19.422 60.941 ;
     RECT  2.304 60.859 2.862 60.989 ;
     RECT  12.78 60.941 19.314 60.989 ;
     RECT  4.824 60.557 5.562 61.051 ;
     RECT  6.84 61.051 6.858 61.151 ;
     RECT  20.52 59.981 20.574 61.159 ;
     RECT  3.996 61.051 4.014 61.229 ;
     RECT  4.824 61.051 5.67 61.435 ;
     RECT  4.356 61.435 5.67 61.591 ;
     RECT  4.356 61.591 6.21 61.619 ;
     RECT  4.5 61.619 6.21 61.691 ;
     RECT  5.115 61.691 6.21 61.763 ;
     RECT  5.115 61.763 5.778 61.799 ;
     RECT  20.52 61.159 20.61 61.805 ;
     RECT  7.815 60.809 8.097 61.963 ;
     RECT  20.52 61.805 20.538 62.041 ;
     RECT  2.415 60.989 2.697 62.131 ;
     RECT  2.376 62.131 2.697 62.167 ;
     RECT  2.304 62.167 3.15 62.239 ;
     RECT  7.704 61.963 8.097 62.239 ;
     RECT  7.56 62.239 8.097 62.311 ;
     RECT  7.488 62.311 8.097 62.401 ;
     RECT  12.78 60.989 19.098 62.509 ;
     RECT  19.944 62.041 20.538 62.509 ;
     RECT  5.115 61.799 5.397 62.581 ;
     RECT  2.304 62.239 3.438 62.671 ;
     RECT  2.304 62.671 4.014 63.121 ;
     RECT  2.304 63.121 4.266 63.275 ;
     RECT  12.78 62.509 20.538 63.293 ;
     RECT  5.115 62.581 5.994 63.481 ;
     RECT  6.804 62.401 8.097 63.481 ;
     RECT  19.944 63.293 20.538 63.589 ;
     RECT  19.944 63.589 20.61 63.629 ;
     RECT  10.515 56.561 12.042 63.689 ;
     RECT  3.96 63.275 4.266 63.751 ;
     RECT  3.96 63.751 4.302 63.779 ;
     RECT  5.115 63.481 8.097 63.779 ;
     RECT  11.628 63.689 12.042 63.779 ;
     RECT  6.552 63.779 8.097 63.815 ;
     RECT  4.284 63.779 4.302 63.851 ;
     RECT  6.84 63.815 8.097 63.851 ;
     RECT  0.54 63.211 0.558 63.965 ;
     RECT  5.115 63.779 5.397 64.021 ;
     RECT  20.52 63.629 20.61 64.109 ;
     RECT  4.392 64.021 5.397 64.121 ;
     RECT  6.84 63.851 6.858 64.121 ;
     RECT  2.304 63.275 2.862 64.253 ;
     RECT  12.78 63.293 19.17 64.363 ;
     RECT  2.415 64.253 2.862 64.391 ;
     RECT  20.52 64.109 20.574 64.445 ;
     RECT  0.216 64.291 0.234 64.493 ;
     RECT  5.115 64.121 5.397 64.561 ;
     RECT  5.115 64.561 5.454 64.705 ;
     RECT  5.115 64.705 6.102 64.741 ;
     RECT  12.78 64.363 19.314 64.741 ;
     RECT  20.124 64.603 20.142 64.741 ;
     RECT  12.78 64.741 20.142 64.781 ;
     RECT  7.815 63.851 8.097 64.831 ;
     RECT  5.115 64.741 6.822 64.859 ;
     RECT  7.704 64.831 8.097 64.973 ;
     RECT  5.115 64.859 5.397 65.101 ;
     RECT  3.708 65.011 3.726 65.165 ;
     RECT  4.464 65.101 5.397 65.309 ;
     RECT  12.78 64.781 19.458 65.309 ;
     RECT  2.415 64.391 2.826 65.501 ;
     RECT  20.52 65.281 20.574 65.551 ;
     RECT  5.115 65.309 5.397 65.641 ;
     RECT  6.804 64.859 6.822 65.641 ;
     RECT  20.52 65.551 20.61 65.749 ;
     RECT  5.115 65.641 6.858 65.813 ;
     RECT  7.815 64.973 8.097 65.821 ;
     RECT  5.115 65.813 5.67 65.849 ;
     RECT  19.944 65.749 20.61 65.849 ;
     RECT  7.815 65.821 8.442 65.939 ;
     RECT  6.48 65.813 6.858 65.981 ;
     RECT  3.996 65.947 4.014 66.019 ;
     RECT  3.42 66.019 4.014 66.119 ;
     RECT  3.996 66.119 4.014 66.181 ;
     RECT  5.115 65.849 5.397 66.181 ;
     RECT  11.916 63.779 12.042 66.245 ;
     RECT  0.54 65.911 0.558 66.269 ;
     RECT  3.996 66.181 5.397 66.281 ;
     RECT  12.78 65.309 19.134 66.281 ;
     RECT  19.98 65.849 20.61 66.451 ;
     RECT  6.84 65.981 6.858 66.479 ;
     RECT  11.952 66.245 12.042 66.515 ;
     RECT  19.98 66.451 20.646 66.551 ;
     RECT  0.252 66.712 0.27 66.749 ;
     RECT  3.996 66.281 4.374 66.749 ;
     RECT  10.515 63.689 10.797 66.793 ;
     RECT  19.98 66.551 20.574 66.797 ;
     RECT  7.815 65.939 8.097 66.829 ;
     RECT  2.415 65.501 2.697 66.859 ;
     RECT  10.515 66.793 10.854 66.893 ;
     RECT  19.98 66.797 20.538 66.901 ;
     RECT  7.272 66.829 8.097 66.929 ;
     RECT  2.415 66.859 2.862 66.955 ;
     RECT  2.304 66.955 2.862 67.037 ;
     RECT  5.115 66.281 5.397 67.135 ;
     RECT  0.216 67.063 0.234 67.229 ;
     RECT  4.572 67.135 5.397 67.261 ;
     RECT  3.636 67.261 3.654 67.361 ;
     RECT  4.572 67.261 5.454 67.469 ;
     RECT  4.608 67.469 5.454 67.531 ;
     RECT  19.944 66.901 20.538 67.603 ;
     RECT  19.944 67.603 20.61 67.613 ;
     RECT  4.608 67.531 6.03 67.631 ;
     RECT  6.84 67.531 6.858 67.631 ;
     RECT  12.78 66.281 18.99 67.675 ;
     RECT  2.304 67.037 2.697 67.963 ;
     RECT  2.304 67.963 2.862 68.009 ;
     RECT  4.608 67.631 5.397 68.099 ;
     RECT  2.415 68.009 2.862 68.107 ;
     RECT  7.815 66.929 8.097 68.107 ;
     RECT  20.52 67.613 20.61 68.141 ;
     RECT  2.415 68.107 3.582 68.279 ;
     RECT  7.815 68.107 8.19 68.341 ;
     RECT  7.815 68.341 8.262 68.441 ;
     RECT  5.115 68.099 5.397 68.485 ;
     RECT  7.815 68.441 8.097 68.485 ;
     RECT  3.996 68.341 4.014 68.525 ;
     RECT  5.115 68.485 5.526 68.611 ;
     RECT  6.444 68.071 6.606 68.611 ;
     RECT  5.115 68.611 6.606 68.719 ;
     RECT  10.515 66.893 10.797 68.719 ;
     RECT  7.668 68.485 8.097 68.755 ;
     RECT  12.024 66.515 12.042 68.755 ;
     RECT  12.78 67.675 19.422 68.755 ;
     RECT  12.024 68.755 19.422 68.791 ;
     RECT  5.115 68.719 6.678 68.819 ;
     RECT  10.515 68.719 10.854 68.819 ;
     RECT  11.988 68.791 19.422 68.819 ;
     RECT  7.488 68.755 8.097 68.909 ;
     RECT  11.988 68.819 13.878 68.945 ;
     RECT  14.652 68.819 19.422 68.953 ;
     RECT  0.54 68.683 0.558 69.005 ;
     RECT  5.115 68.819 6.03 69.061 ;
     RECT  14.652 68.953 19.458 69.061 ;
     RECT  20.52 68.141 20.574 69.061 ;
     RECT  2.415 68.279 2.697 69.151 ;
     RECT  4.608 69.061 6.03 69.251 ;
     RECT  14.652 69.061 20.574 69.293 ;
     RECT  2.415 69.151 2.826 69.331 ;
     RECT  3.636 69.223 3.654 69.331 ;
     RECT  2.415 69.331 3.654 69.421 ;
     RECT  2.415 69.421 4.158 69.449 ;
     RECT  2.415 69.449 2.826 69.533 ;
     RECT  5.115 69.251 6.03 69.565 ;
     RECT  10.515 68.819 10.797 69.799 ;
     RECT  3.6 69.449 4.158 69.863 ;
     RECT  10.515 69.799 10.854 69.899 ;
     RECT  5.115 69.565 6.858 69.961 ;
     RECT  5.115 69.961 6.894 69.989 ;
     RECT  5.115 69.989 5.67 70.013 ;
     RECT  2.415 69.533 2.79 70.025 ;
     RECT  12.528 68.945 13.878 70.033 ;
     RECT  12.456 70.033 13.878 70.069 ;
     RECT  14.652 69.293 20.034 70.069 ;
     RECT  6.876 69.989 6.894 70.097 ;
     RECT  12.456 70.069 20.034 70.097 ;
     RECT  13.215 70.097 20.034 70.109 ;
     RECT  4.14 69.863 4.158 70.141 ;
     RECT  2.415 70.025 2.697 70.231 ;
     RECT  0.54 70.069 0.558 70.253 ;
     RECT  12.456 70.097 12.474 70.259 ;
     RECT  4.14 70.141 4.266 70.403 ;
     RECT  20.52 70.339 20.538 70.411 ;
     RECT  13.215 70.109 19.422 70.643 ;
     RECT  5.115 70.013 5.397 70.681 ;
     RECT  3.636 70.645 3.87 70.799 ;
     RECT  7.815 68.909 8.097 70.807 ;
     RECT  13.215 70.643 18.897 70.829 ;
     RECT  7.164 70.807 8.097 70.907 ;
     RECT  3.852 70.799 3.87 70.943 ;
     RECT  20.52 70.411 20.574 70.951 ;
     RECT  19.944 70.951 20.574 70.973 ;
     RECT  2.376 70.231 2.697 71.041 ;
     RECT  2.304 71.041 2.697 71.077 ;
     RECT  6.84 71.077 6.858 71.177 ;
     RECT  2.304 71.077 2.934 71.213 ;
     RECT  4.968 70.681 5.397 71.221 ;
     RECT  4.788 71.221 5.397 71.347 ;
     RECT  13.215 70.829 13.878 71.375 ;
     RECT  4.788 71.347 5.85 71.519 ;
     RECT  14.796 70.829 18.897 71.581 ;
     RECT  19.944 70.973 20.538 71.581 ;
     RECT  14.796 71.581 20.538 71.597 ;
     RECT  14.796 71.597 19.458 71.645 ;
     RECT  2.304 71.213 2.862 71.789 ;
     RECT  3.924 71.311 4.05 71.789 ;
     RECT  4.788 71.519 5.397 71.887 ;
     RECT  15.624 71.645 19.458 71.915 ;
     RECT  20.52 71.597 20.538 71.933 ;
     RECT  14.796 71.645 14.814 71.959 ;
     RECT  4.5 71.887 5.397 72.029 ;
     RECT  2.415 71.789 2.862 72.031 ;
     RECT  6.768 71.995 6.786 72.031 ;
     RECT  4.824 72.029 5.397 72.059 ;
     RECT  2.415 72.031 3.078 72.121 ;
     RECT  15.915 71.915 19.458 72.149 ;
     RECT  14.724 71.959 14.814 72.185 ;
     RECT  17.028 72.149 19.458 72.221 ;
     RECT  6.408 72.031 6.858 72.301 ;
     RECT  2.415 72.121 3.618 72.329 ;
     RECT  18.216 72.221 19.458 72.391 ;
     RECT  6.192 72.301 6.858 72.455 ;
     RECT  17.028 72.221 17.262 72.491 ;
     RECT  5.112 72.059 5.397 72.599 ;
     RECT  17.1 72.491 17.262 72.689 ;
     RECT  6.84 72.455 6.858 72.761 ;
     RECT  0.54 72.121 0.558 72.769 ;
     RECT  18.216 72.391 19.962 72.797 ;
     RECT  3.924 72.571 4.05 72.841 ;
     RECT  18.216 72.797 19.422 72.941 ;
     RECT  17.1 72.689 17.19 72.959 ;
     RECT  0.216 72.769 0.558 73.037 ;
     RECT  3.924 72.841 4.158 73.103 ;
     RECT  2.415 72.329 3.078 73.139 ;
     RECT  3.924 73.103 3.942 73.139 ;
     RECT  17.1 72.959 17.118 73.229 ;
     RECT  20.484 72.931 20.538 73.229 ;
     RECT  0.54 73.037 0.558 73.277 ;
     RECT  20.52 73.229 20.538 73.277 ;
     RECT  18.216 72.941 18.897 73.381 ;
     RECT  18.18 73.381 18.897 73.535 ;
     RECT  2.415 73.139 2.697 75.347 ;
     RECT  5.115 72.599 5.397 75.347 ;
     RECT  7.815 70.907 8.097 75.347 ;
     RECT  10.515 69.899 10.797 75.347 ;
     RECT  13.215 71.375 13.497 75.347 ;
     RECT  15.915 72.149 16.197 75.347 ;
     RECT  18.615 73.535 18.897 75.347 ;
     RECT  2.415 75.347 2.505 75.617 ;
     RECT  5.115 75.347 5.205 75.617 ;
     RECT  7.815 75.347 7.905 75.617 ;
     RECT  10.515 75.347 10.605 75.617 ;
     RECT  13.215 75.347 13.305 75.617 ;
     RECT  15.915 75.347 16.005 75.617 ;
     RECT  18.615 75.347 18.705 75.617 ;
    LAYER M4 ;
     RECT  0.156 4.512 0.569 73.272 ;
     RECT  0.569 4.512 2.408 49.416 ;
     RECT  0.569 50.4 2.408 72.792 ;
     RECT  2.408 2.148 2.512 75.612 ;
     RECT  2.512 2.418 2.704 75.342 ;
     RECT  2.704 5.808 2.765 5.832 ;
     RECT  2.704 30.912 2.765 30.936 ;
     RECT  2.704 33.888 2.765 35.208 ;
     RECT  2.704 37.344 2.765 37.464 ;
     RECT  2.704 24.72 2.801 27.144 ;
     RECT  2.704 39.072 2.837 41.736 ;
     RECT  2.704 64.704 2.837 72.792 ;
     RECT  2.704 8.16 2.873 11.16 ;
     RECT  2.704 15.456 2.873 18.936 ;
     RECT  2.704 54.432 2.873 63.672 ;
     RECT  2.837 64.704 2.873 68.76 ;
     RECT  2.801 24.72 3.251 26.808 ;
     RECT  2.873 8.16 3.277 11.064 ;
     RECT  3.251 26.784 3.277 26.808 ;
     RECT  2.873 16.512 3.292 18.936 ;
     RECT  3.277 8.16 3.299 9.288 ;
     RECT  2.704 36.24 3.299 36.264 ;
     RECT  2.765 37.344 3.299 37.368 ;
     RECT  2.704 6.816 3.313 6.84 ;
     RECT  2.765 33.888 3.313 34.728 ;
     RECT  3.292 18.912 3.341 18.936 ;
     RECT  3.277 10.416 3.347 11.064 ;
     RECT  2.704 12.24 3.347 12.264 ;
     RECT  2.704 14.256 3.413 14.28 ;
     RECT  3.251 25.344 3.773 25.656 ;
     RECT  3.299 8.4 3.809 8.52 ;
     RECT  3.292 16.512 4.025 17.544 ;
     RECT  2.837 39.072 4.025 40.392 ;
     RECT  2.837 41.376 4.025 41.736 ;
     RECT  2.704 43.104 4.025 49.368 ;
     RECT  2.873 54.432 4.025 63.576 ;
     RECT  2.837 69.744 4.025 72.792 ;
     RECT  4.025 69.984 4.061 72.792 ;
     RECT  4.025 46.896 4.097 49.368 ;
     RECT  2.873 15.456 4.129 15.48 ;
     RECT  4.025 16.512 4.129 17.352 ;
     RECT  3.313 33.888 4.633 33.912 ;
     RECT  4.237 35.28 4.633 35.304 ;
     RECT  3.347 10.416 4.661 10.44 ;
     RECT  3.773 25.632 4.777 25.656 ;
     RECT  4.129 27.168 4.777 27.192 ;
     RECT  4.661 10.416 4.813 10.584 ;
     RECT  2.704 21.456 4.813 21.48 ;
     RECT  4.777 25.632 4.813 27.336 ;
     RECT  4.021 32.784 4.813 32.808 ;
     RECT  4.633 33.888 4.813 35.304 ;
     RECT  4.549 36.48 4.837 36.504 ;
     RECT  4.813 21.456 4.844 22.056 ;
     RECT  4.813 25.44 4.844 27.336 ;
     RECT  4.813 10.176 4.849 10.584 ;
     RECT  4.237 7.2 5.108 7.224 ;
     RECT  3.809 8.496 5.108 8.52 ;
     RECT  4.849 10.176 5.108 11.448 ;
     RECT  4.129 15.456 5.108 17.352 ;
     RECT  4.844 21.456 5.108 22.968 ;
     RECT  4.813 24.384 5.108 24.408 ;
     RECT  4.844 25.44 5.108 27.864 ;
     RECT  4.844 28.896 5.108 28.92 ;
     RECT  4.813 32.784 5.108 35.304 ;
     RECT  4.837 36.48 5.108 37.032 ;
     RECT  4.561 38.208 5.108 38.232 ;
     RECT  4.025 39.84 5.108 40.392 ;
     RECT  4.025 41.712 5.108 41.736 ;
     RECT  4.025 43.104 5.108 45.432 ;
     RECT  4.097 47.616 5.108 49.368 ;
     RECT  2.704 50.4 5.108 52.44 ;
     RECT  4.025 54.432 5.108 57.96 ;
     RECT  4.025 58.944 5.108 61.992 ;
     RECT  4.025 62.976 5.108 63.576 ;
     RECT  2.873 64.704 5.108 66.888 ;
     RECT  2.873 68.112 5.108 68.76 ;
     RECT  4.061 69.984 5.108 70.872 ;
     RECT  4.061 72 5.108 72.792 ;
     RECT  5.108 2.148 5.212 75.612 ;
     RECT  5.212 2.418 5.404 75.342 ;
     RECT  5.404 47.616 5.465 47.64 ;
     RECT  5.404 64.704 5.465 66.888 ;
     RECT  5.404 68.112 5.573 68.76 ;
     RECT  5.404 39.84 5.645 40.392 ;
     RECT  5.404 50.4 5.681 50.664 ;
     RECT  5.404 54.432 5.681 54.696 ;
     RECT  5.404 69.984 5.681 70.008 ;
     RECT  5.404 43.632 5.717 43.656 ;
     RECT  5.404 16.368 5.747 17.112 ;
     RECT  5.465 64.944 5.753 66.888 ;
     RECT  5.404 10.416 5.843 10.728 ;
     RECT  5.404 60.864 5.861 61.992 ;
     RECT  5.404 27.072 5.939 28.248 ;
     RECT  5.404 20.592 6.221 22.152 ;
     RECT  5.404 32.784 6.275 33.096 ;
     RECT  5.404 62.976 6.293 63.576 ;
     RECT  5.404 25.536 6.373 25.56 ;
     RECT  5.404 9.168 6.38 9.192 ;
     RECT  5.747 17.088 6.397 17.112 ;
     RECT  6.38 19.584 6.397 19.608 ;
     RECT  5.404 56.544 6.401 56.568 ;
     RECT  5.404 34.368 6.433 34.392 ;
     RECT  5.404 11.952 6.437 11.976 ;
     RECT  6.373 24.144 6.46 24.168 ;
     RECT  6.373 25.536 6.46 25.704 ;
     RECT  6.38 6.624 6.467 6.648 ;
     RECT  6.38 8.4 6.467 9.192 ;
     RECT  6.397 17.088 6.467 19.608 ;
     RECT  6.221 20.592 6.467 21.48 ;
     RECT  6.389 5.088 6.473 5.112 ;
     RECT  6.467 17.088 6.481 18.744 ;
     RECT  5.753 65.952 6.509 66.888 ;
     RECT  5.404 48.72 6.545 48.744 ;
     RECT  6.467 9.168 6.617 9.192 ;
     RECT  5.573 68.112 6.617 68.136 ;
     RECT  5.939 27.216 6.653 28.248 ;
     RECT  6.481 17.088 6.805 18.072 ;
     RECT  6.805 16.944 7.189 18.072 ;
     RECT  6.433 34.368 7.58 34.824 ;
     RECT  6.275 33.072 7.621 33.096 ;
     RECT  6.653 27.216 7.657 27.24 ;
     RECT  6.653 28.224 7.657 28.248 ;
     RECT  7.657 27.216 7.669 28.248 ;
     RECT  7.801 7.92 7.808 7.944 ;
     RECT  7.549 9.024 7.808 9.048 ;
     RECT  5.843 10.704 7.808 10.728 ;
     RECT  7.693 11.952 7.808 11.976 ;
     RECT  7.189 16.32 7.808 18.072 ;
     RECT  6.467 21.456 7.808 21.48 ;
     RECT  6.46 25.536 7.808 25.56 ;
     RECT  7.669 26.544 7.808 28.248 ;
     RECT  6.829 30.816 7.808 30.84 ;
     RECT  7.621 33.072 7.808 33.288 ;
     RECT  7.58 34.32 7.808 34.824 ;
     RECT  5.645 39.84 7.808 39.864 ;
     RECT  5.404 41.712 7.808 41.736 ;
     RECT  5.681 50.64 7.808 50.664 ;
     RECT  5.681 54.672 7.808 54.696 ;
     RECT  5.404 57.936 7.808 57.96 ;
     RECT  5.404 58.944 7.808 58.968 ;
     RECT  5.861 60.864 7.808 60.888 ;
     RECT  5.861 61.968 7.808 61.992 ;
     RECT  6.293 62.976 7.808 63 ;
     RECT  5.753 64.944 7.808 64.968 ;
     RECT  6.509 66.864 7.808 66.888 ;
     RECT  7.808 2.148 7.912 75.612 ;
     RECT  7.912 2.418 8.104 75.342 ;
     RECT  8.104 11.712 8.129 12.792 ;
     RECT  8.104 19.776 8.165 19.8 ;
     RECT  8.104 34.368 8.165 34.92 ;
     RECT  8.104 38.16 8.165 38.184 ;
     RECT  8.104 7.488 8.243 9.048 ;
     RECT  8.129 11.712 8.243 11.736 ;
     RECT  8.129 12.768 8.243 12.792 ;
     RECT  8.104 21.456 8.243 21.816 ;
     RECT  8.104 22.848 8.243 22.872 ;
     RECT  8.104 27.888 8.243 27.912 ;
     RECT  8.104 28.992 8.243 29.016 ;
     RECT  8.104 30.048 8.243 30.072 ;
     RECT  8.104 6.048 8.245 6.168 ;
     RECT  8.243 7.488 8.273 7.944 ;
     RECT  8.243 9.024 8.273 9.048 ;
     RECT  8.104 17.088 8.273 17.112 ;
     RECT  8.104 39.84 8.381 39.864 ;
     RECT  8.273 7.488 8.921 7.512 ;
     RECT  10.393 1.728 10.508 1.752 ;
     RECT  8.245 6.048 10.508 6.072 ;
     RECT  8.243 21.456 10.508 21.48 ;
     RECT  8.104 25.536 10.508 25.56 ;
     RECT  8.165 34.368 10.508 34.392 ;
     RECT  10.508 1.728 10.612 75.612 ;
     RECT  10.612 1.728 10.804 75.342 ;
     RECT  10.804 1.728 10.835 1.752 ;
     RECT  13.021 31.344 13.093 31.368 ;
     RECT  10.804 21.456 13.208 21.48 ;
     RECT  10.804 25.536 13.208 25.56 ;
     RECT  13.093 31.344 13.208 31.512 ;
     RECT  10.804 34.368 13.208 34.392 ;
     RECT  13.093 36 13.208 36.024 ;
     RECT  12.949 44.4 13.208 44.424 ;
     RECT  13.052 50.736 13.208 50.76 ;
     RECT  13.165 54.672 13.208 54.696 ;
     RECT  13.208 2.148 13.312 75.612 ;
     RECT  13.312 2.418 13.504 75.342 ;
     RECT  13.504 34.368 13.619 36.024 ;
     RECT  13.504 54.672 13.637 54.696 ;
     RECT  13.504 15.984 13.673 16.536 ;
     RECT  13.504 21.072 13.811 21.672 ;
     RECT  13.504 55.872 13.825 55.896 ;
     RECT  13.504 38.736 13.852 40.008 ;
     RECT  13.504 12.912 13.907 13.8 ;
     RECT  13.504 32.688 13.907 33.24 ;
     RECT  13.504 11.376 13.925 11.4 ;
     RECT  13.673 15.984 13.955 16.344 ;
     RECT  13.504 50.304 13.955 50.712 ;
     RECT  13.504 29.04 13.997 29.064 ;
     RECT  13.504 23.376 14.099 25.56 ;
     RECT  13.907 33.072 14.177 33.24 ;
     RECT  13.955 50.688 14.213 50.712 ;
     RECT  13.504 57.6 14.243 58.152 ;
     RECT  13.619 34.368 14.249 35.112 ;
     RECT  13.852 39.408 14.249 40.008 ;
     RECT  14.243 58.128 14.249 58.152 ;
     RECT  14.177 33.12 14.462 33.24 ;
     RECT  13.811 21.072 14.465 21.48 ;
     RECT  14.462 33.216 14.465 33.24 ;
     RECT  13.504 52.992 14.501 53.016 ;
     RECT  14.099 23.376 14.537 23.976 ;
     RECT  14.537 23.952 14.645 23.976 ;
     RECT  13.504 41.904 14.819 41.928 ;
     RECT  13.504 37.008 14.821 37.032 ;
     RECT  14.713 50.736 14.88 51.432 ;
     RECT  13.504 44.4 14.893 44.424 ;
     RECT  14.821 36.576 14.929 37.032 ;
     RECT  14.857 46.752 15.037 46.776 ;
     RECT  15.001 40.752 15.145 40.776 ;
     RECT  14.929 36.576 15.205 37.08 ;
     RECT  14.857 42.672 15.356 42.696 ;
     RECT  14.677 10.512 15.361 10.536 ;
     RECT  13.907 13.776 15.397 13.8 ;
     RECT  13.955 15.984 15.397 16.104 ;
     RECT  15.356 17.232 15.397 17.256 ;
     RECT  14.821 58.224 15.397 58.248 ;
     RECT  15.349 27.216 15.433 27.24 ;
     RECT  15.397 58.224 15.577 58.728 ;
     RECT  15.037 46.656 15.613 46.776 ;
     RECT  13.504 70.8 15.613 70.824 ;
     RECT  14.465 21.456 15.637 21.48 ;
     RECT  15.301 48.624 15.692 48.648 ;
     RECT  15.433 27.216 15.733 28.2 ;
     RECT  14.857 7.488 15.908 7.512 ;
     RECT  15.361 9.84 15.908 10.536 ;
     RECT  15.397 13.296 15.908 13.8 ;
     RECT  15.145 14.928 15.908 14.952 ;
     RECT  15.397 15.984 15.908 17.256 ;
     RECT  15.637 20.88 15.908 21.48 ;
     RECT  15.001 22.512 15.908 22.536 ;
     RECT  14.099 25.104 15.908 25.56 ;
     RECT  15.733 26.544 15.908 28.2 ;
     RECT  14.773 29.952 15.908 29.976 ;
     RECT  14.965 31.056 15.908 31.32 ;
     RECT  15.649 33.072 15.908 33.096 ;
     RECT  14.249 34.368 15.908 34.392 ;
     RECT  15.205 35.568 15.908 37.08 ;
     RECT  15.433 39.168 15.908 39.192 ;
     RECT  15.145 40.752 15.908 41.016 ;
     RECT  15.356 42.672 15.908 43.32 ;
     RECT  14.893 44.4 15.908 44.52 ;
     RECT  15.613 46.656 15.908 46.872 ;
     RECT  15.692 48.624 15.908 49.176 ;
     RECT  14.88 50.736 15.908 50.856 ;
     RECT  15.397 52.032 15.908 52.056 ;
     RECT  14.957 53.568 15.908 53.592 ;
     RECT  15.505 54.72 15.908 54.744 ;
     RECT  15.577 57.6 15.908 58.728 ;
     RECT  15.356 62.544 15.908 62.568 ;
     RECT  15.613 70.8 15.908 71.064 ;
     RECT  15.908 2.148 16.012 75.612 ;
     RECT  16.012 2.418 16.204 75.342 ;
     RECT  16.204 13.296 16.265 13.32 ;
     RECT  16.204 59.856 16.373 59.88 ;
     RECT  16.204 53.04 16.444 53.592 ;
     RECT  16.204 50.736 16.445 51.72 ;
     RECT  16.445 50.832 16.481 51.72 ;
     RECT  16.204 24.816 16.489 25.56 ;
     RECT  16.204 19.92 16.492 22.824 ;
     RECT  16.204 45.456 16.499 45.528 ;
     RECT  16.444 53.04 16.499 53.064 ;
     RECT  16.204 29.472 16.517 33.24 ;
     RECT  16.204 46.752 16.517 46.92 ;
     RECT  16.517 29.472 16.547 30.936 ;
     RECT  16.204 43.104 16.547 44.472 ;
     RECT  16.204 36.048 16.553 37.56 ;
     RECT  16.481 51.312 16.561 51.72 ;
     RECT  16.492 20.496 16.595 22.824 ;
     RECT  16.204 9.84 16.625 9.96 ;
     RECT  16.204 18.24 16.625 18.792 ;
     RECT  16.204 8.544 16.661 8.568 ;
     RECT  16.489 24.816 16.732 24.84 ;
     RECT  16.547 30.24 17.093 30.936 ;
     RECT  16.553 36.048 17.123 37.176 ;
     RECT  16.204 40.992 17.123 41.064 ;
     RECT  16.517 31.92 17.219 33.24 ;
     RECT  16.204 63.648 17.221 63.672 ;
     RECT  16.204 64.752 17.221 64.776 ;
     RECT  16.204 26.544 17.269 26.568 ;
     RECT  17.269 26.256 17.315 26.568 ;
     RECT  17.228 41.856 17.315 41.88 ;
     RECT  17.228 60.96 17.315 60.984 ;
     RECT  17.093 30.72 17.389 30.936 ;
     RECT  16.204 38.784 17.453 38.808 ;
     RECT  16.625 18.768 17.509 18.792 ;
     RECT  17.389 30.816 17.509 30.936 ;
     RECT  17.219 31.92 17.509 33.096 ;
     RECT  17.461 53.04 17.509 53.064 ;
     RECT  17.315 26.256 17.555 26.28 ;
     RECT  16.499 45.456 17.555 45.48 ;
     RECT  17.509 18.768 17.597 19.128 ;
     RECT  16.204 34.32 17.601 34.776 ;
     RECT  17.123 36.048 17.601 37.032 ;
     RECT  17.509 53.04 17.605 53.592 ;
     RECT  16.204 57.12 17.629 58.248 ;
     RECT  17.605 52.992 17.633 53.592 ;
     RECT  17.557 47.904 17.641 47.928 ;
     RECT  16.561 51.696 17.653 51.72 ;
     RECT  16.517 46.752 17.66 46.776 ;
     RECT  17.621 11.952 17.665 11.976 ;
     RECT  16.204 14.448 17.665 14.952 ;
     RECT  17.66 46.752 17.665 47.304 ;
     RECT  16.547 43.872 17.693 44.472 ;
     RECT  16.625 9.84 17.701 9.864 ;
     RECT  17.665 11.568 17.701 11.976 ;
     RECT  17.693 43.872 17.708 44.76 ;
     RECT  17.221 63.648 17.749 64.776 ;
     RECT  17.653 51.696 17.773 51.864 ;
     RECT  17.665 55.824 17.773 55.848 ;
     RECT  16.204 70.8 17.845 70.824 ;
     RECT  17.701 9.072 17.852 11.976 ;
     RECT  17.665 13.152 17.852 13.176 ;
     RECT  17.773 55.296 17.873 55.848 ;
     RECT  17.601 34.32 17.893 37.032 ;
     RECT  16.595 21.456 17.917 22.824 ;
     RECT  17.629 57.12 18.025 58.44 ;
     RECT  17.893 34.128 18.241 37.032 ;
     RECT  17.665 14.448 18.373 15.768 ;
     RECT  18.241 34.128 18.373 37.608 ;
     RECT  17.953 38.736 18.373 38.76 ;
     RECT  18.493 4.704 18.608 4.728 ;
     RECT  17.852 9.072 18.608 13.176 ;
     RECT  18.373 14.448 18.608 15.864 ;
     RECT  16.204 17.088 18.608 17.112 ;
     RECT  17.597 18.768 18.608 18.792 ;
     RECT  17.917 21.456 18.608 23.688 ;
     RECT  17.557 26.16 18.608 26.184 ;
     RECT  18.025 27.6 18.608 27.624 ;
     RECT  17.665 29.088 18.608 29.112 ;
     RECT  17.509 30.816 18.608 33.096 ;
     RECT  18.373 34.128 18.608 38.76 ;
     RECT  17.708 43.776 18.608 44.76 ;
     RECT  17.665 46.272 18.608 47.304 ;
     RECT  17.804 49.536 18.608 49.56 ;
     RECT  17.773 50.736 18.608 51.864 ;
     RECT  17.633 52.992 18.608 53.064 ;
     RECT  17.873 55.296 18.608 55.896 ;
     RECT  18.025 57.12 18.608 58.728 ;
     RECT  18.341 60.432 18.608 60.456 ;
     RECT  17.749 63.216 18.608 64.776 ;
     RECT  17.701 68.4 18.608 68.424 ;
     RECT  17.845 70.8 18.608 71.064 ;
     RECT  18.608 2.148 18.712 75.612 ;
     RECT  18.712 2.418 18.904 75.342 ;
     RECT  18.904 55.296 19.897 55.32 ;
     RECT  18.904 7.344 19.933 7.368 ;
     RECT  18.904 8.688 19.933 12.696 ;
     RECT  18.904 14.544 19.933 18.696 ;
     RECT  18.904 20.16 19.933 29.112 ;
     RECT  18.904 30.912 19.933 39.096 ;
     RECT  18.904 43.056 19.933 46.392 ;
     RECT  18.904 49.056 19.933 49.56 ;
     RECT  18.904 50.784 19.933 51.288 ;
     RECT  18.904 52.272 19.933 52.968 ;
     RECT  19.897 54.768 19.933 55.32 ;
     RECT  18.904 57.12 19.933 58.44 ;
     RECT  18.904 60.288 19.933 63.288 ;
     RECT  18.904 64.944 19.933 65.304 ;
     RECT  18.904 67.104 19.933 67.128 ;
     RECT  18.904 68.256 19.933 70.776 ;
     RECT  18.904 71.76 19.933 72.936 ;
     RECT  19.933 64.752 19.969 65.784 ;
     RECT  19.933 67.104 19.969 72.936 ;
     RECT  19.969 64.752 20.113 72.936 ;
     RECT  18.904 4.704 20.473 4.728 ;
     RECT  19.933 5.712 20.473 7.368 ;
     RECT  19.933 8.688 20.473 13.368 ;
     RECT  19.933 14.544 20.473 39.096 ;
     RECT  19.933 40.08 20.473 49.56 ;
     RECT  19.933 50.592 20.473 58.632 ;
     RECT  20.113 64.608 20.473 72.936 ;
     RECT  20.473 4.512 20.509 39.096 ;
     RECT  20.473 40.08 20.509 58.632 ;
     RECT  19.933 59.616 20.509 63.624 ;
     RECT  20.473 64.608 20.509 73.128 ;
     RECT  20.509 4.512 21.42 73.272 ;
     RECT  21.42 43.248 21.485 43.272 ;
     RECT  21.42 58.224 21.485 58.248 ;
    LAYER M5 ;
     RECT  10.8 0.144 10.824 1.763 ;
     RECT  10.8 1.763 10.812 2.137 ;
     RECT  2.4 2.137 2.52 2.151 ;
     RECT  5.1 2.137 5.22 2.151 ;
     RECT  7.8 2.137 7.92 2.151 ;
     RECT  13.2 2.137 13.32 2.151 ;
     RECT  15.9 2.137 16.02 2.151 ;
     RECT  18.6 2.137 18.72 2.151 ;
     RECT  7.8 2.151 8.112 6.133 ;
     RECT  2.4 2.151 2.712 6.805 ;
     RECT  15.9 2.151 16.212 7.477 ;
     RECT  5.1 2.151 5.412 8.485 ;
     RECT  14.976 7.477 16.212 8.533 ;
     RECT  7.8 6.133 8.232 8.819 ;
     RECT  18.6 2.151 18.912 9.061 ;
     RECT  6.432 5.077 6.456 9.203 ;
     RECT  2.4 6.805 3.288 9.299 ;
     RECT  4.704 8.485 5.412 10.405 ;
     RECT  4.704 10.405 5.832 10.595 ;
     RECT  4.896 10.595 5.832 10.739 ;
     RECT  2.4 9.299 3.24 11.029 ;
     RECT  13.2 2.151 13.512 11.365 ;
     RECT  4.896 10.739 5.736 11.459 ;
     RECT  7.8 8.819 8.112 11.701 ;
     RECT  17.712 9.061 18.912 11.941 ;
     RECT  7.8 11.701 8.232 12.803 ;
     RECT  13.2 11.365 13.896 13.765 ;
     RECT  14.976 8.533 16.536 13.765 ;
     RECT  2.4 11.029 3.336 14.291 ;
     RECT  17.664 11.941 18.912 14.533 ;
     RECT  5.1 11.459 5.736 16.453 ;
     RECT  2.4 14.291 2.712 16.501 ;
     RECT  7.8 12.803 8.112 16.933 ;
     RECT  4.992 16.453 5.736 17.077 ;
     RECT  6.816 16.933 8.112 17.077 ;
     RECT  4.992 17.077 8.112 17.363 ;
     RECT  5.1 17.363 8.112 17.699 ;
     RECT  5.1 17.699 5.928 18.709 ;
     RECT  2.4 16.501 3.24 18.947 ;
     RECT  17.616 14.533 18.912 19.093 ;
     RECT  13.2 13.765 16.536 20.485 ;
     RECT  17.52 19.093 18.912 20.485 ;
     RECT  5.1 18.709 6.456 20.627 ;
     RECT  2.4 18.947 2.712 21.445 ;
     RECT  2.304 21.445 2.856 21.635 ;
     RECT  7.8 17.699 8.112 21.781 ;
     RECT  5.1 20.627 5.928 22.021 ;
     RECT  7.8 21.781 8.232 22.883 ;
     RECT  4.896 22.021 5.928 24.133 ;
     RECT  2.4 21.635 2.856 24.709 ;
     RECT  4.896 24.133 6.408 25.621 ;
     RECT  4.8 25.621 6.408 25.715 ;
     RECT  7.8 22.883 8.112 26.533 ;
     RECT  2.4 24.709 3.24 26.819 ;
     RECT  4.8 25.715 5.928 27.301 ;
     RECT  4.8 27.301 5.976 27.347 ;
     RECT  7.68 26.533 8.112 27.877 ;
     RECT  7.68 27.877 8.232 28.115 ;
     RECT  4.896 27.347 5.976 28.931 ;
     RECT  7.8 28.115 8.232 30.083 ;
     RECT  5.1 28.931 5.976 32.773 ;
     RECT  5.1 32.773 6.264 33.013 ;
     RECT  4.944 33.013 6.264 33.107 ;
     RECT  7.8 30.083 8.112 33.253 ;
     RECT  4.944 33.107 5.412 34.259 ;
     RECT  7.632 33.253 8.112 34.355 ;
     RECT  2.4 26.819 2.856 34.693 ;
     RECT  5.1 34.259 5.412 35.269 ;
     RECT  13.2 20.485 18.912 35.989 ;
     RECT  4.56 35.269 5.412 36.515 ;
     RECT  2.4 34.693 3.288 37.379 ;
     RECT  13.104 35.989 18.912 38.149 ;
     RECT  4.848 36.515 5.412 38.243 ;
     RECT  13.104 38.149 19.368 38.915 ;
     RECT  2.4 37.379 2.856 48.613 ;
     RECT  2.304 48.613 2.856 48.755 ;
     RECT  13.104 38.915 18.912 50.771 ;
     RECT  13.2 50.771 18.912 53.603 ;
     RECT  2.4 48.755 2.856 56.003 ;
     RECT  13.2 53.603 14.232 57.635 ;
     RECT  13.2 57.635 14.088 58.163 ;
     RECT  15.408 53.603 18.912 59.891 ;
     RECT  17.232 59.891 18.912 60.949 ;
     RECT  17.232 60.949 19.368 61.955 ;
     RECT  15.408 59.891 16.212 62.579 ;
     RECT  0.192 62.677 0.216 62.819 ;
     RECT  17.232 61.955 18.912 63.827 ;
     RECT  17.328 63.827 18.912 64.787 ;
     RECT  17.712 64.787 18.912 68.435 ;
     RECT  2.4 56.003 2.712 70.741 ;
     RECT  2.304 70.741 2.712 70.883 ;
     RECT  15.744 62.579 16.212 71.075 ;
     RECT  17.856 68.435 18.912 71.075 ;
     RECT  2.4 70.883 2.712 75.609 ;
     RECT  5.1 38.243 5.412 75.609 ;
     RECT  7.8 34.355 8.112 75.609 ;
     RECT  10.5 2.137 10.812 75.609 ;
     RECT  13.2 58.163 13.512 75.609 ;
     RECT  15.9 71.075 16.212 75.609 ;
     RECT  18.6 71.075 18.912 75.609 ;
     RECT  2.4 75.609 2.52 75.623 ;
     RECT  5.1 75.609 5.22 75.623 ;
     RECT  7.8 75.609 7.92 75.623 ;
     RECT  10.5 75.609 10.62 75.623 ;
     RECT  13.2 75.609 13.32 75.623 ;
     RECT  15.9 75.609 16.02 75.623 ;
     RECT  18.6 75.609 18.72 75.623 ;
  END
END hbfd_rly_136_WE_fc_f4
END LIBRARY
